VERSION 5.8 ;
BUSBITCHARS "[]" ;
DIVIDERCHAR "/" ;
UNITS
    DATABASE MICRONS 1000 ;
END UNITS

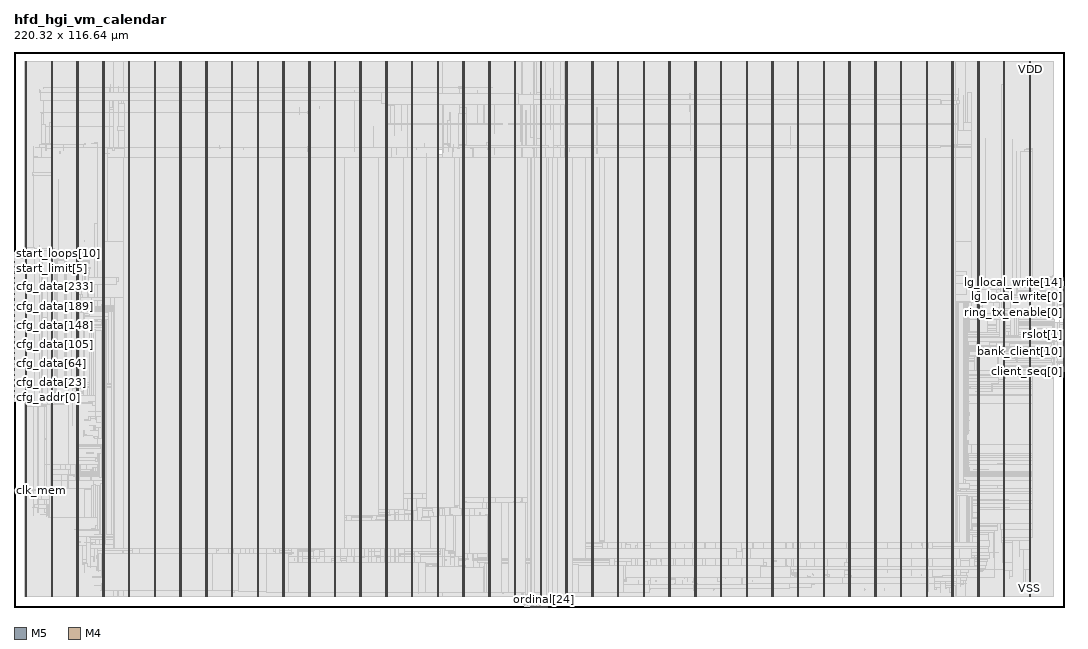
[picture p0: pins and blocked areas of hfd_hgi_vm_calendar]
MACRO hfd_hgi_vm_calendar
  FOREIGN hfd_hgi_vm_calendar 0 0 ;
  CLASS BLOCK ;
  SIZE 220.32 BY 116.64 ;
  PIN active
    DIRECTION OUTPUT ;
    USE SIGNAL ;
    PORT
      LAYER M5 ;
        RECT  108.576 0 108.6 0.084 ;
    END
  END active
  PIN bank_client[0]
    DIRECTION OUTPUT ;
    USE SIGNAL ;
    PORT
      LAYER M4 ;
        RECT  220.236 52.56 220.32 52.584 ;
    END
  END bank_client[0]
  PIN bank_client[10]
    DIRECTION OUTPUT ;
    USE SIGNAL ;
    PORT
      LAYER M4 ;
        RECT  220.236 53.52 220.32 53.544 ;
    END
  END bank_client[10]
  PIN bank_client[11]
    DIRECTION OUTPUT ;
    USE SIGNAL ;
    PORT
      LAYER M4 ;
        RECT  220.236 53.616 220.32 53.64 ;
    END
  END bank_client[11]
  PIN bank_client[12]
    DIRECTION OUTPUT ;
    USE SIGNAL ;
    PORT
      LAYER M4 ;
        RECT  220.236 53.712 220.32 53.736 ;
    END
  END bank_client[12]
  PIN bank_client[13]
    DIRECTION OUTPUT ;
    USE SIGNAL ;
    PORT
      LAYER M4 ;
        RECT  220.236 53.808 220.32 53.832 ;
    END
  END bank_client[13]
  PIN bank_client[14]
    DIRECTION OUTPUT ;
    USE SIGNAL ;
    PORT
      LAYER M4 ;
        RECT  220.236 53.904 220.32 53.928 ;
    END
  END bank_client[14]
  PIN bank_client[15]
    DIRECTION OUTPUT ;
    USE SIGNAL ;
    PORT
      LAYER M4 ;
        RECT  220.236 54 220.32 54.024 ;
    END
  END bank_client[15]
  PIN bank_client[16]
    DIRECTION OUTPUT ;
    USE SIGNAL ;
    PORT
      LAYER M4 ;
        RECT  220.236 54.096 220.32 54.12 ;
    END
  END bank_client[16]
  PIN bank_client[17]
    DIRECTION OUTPUT ;
    USE SIGNAL ;
    PORT
      LAYER M4 ;
        RECT  220.236 54.192 220.32 54.216 ;
    END
  END bank_client[17]
  PIN bank_client[18]
    DIRECTION OUTPUT ;
    USE SIGNAL ;
    PORT
      LAYER M4 ;
        RECT  220.236 54.288 220.32 54.312 ;
    END
  END bank_client[18]
  PIN bank_client[19]
    DIRECTION OUTPUT ;
    USE SIGNAL ;
    PORT
      LAYER M4 ;
        RECT  220.236 54.384 220.32 54.408 ;
    END
  END bank_client[19]
  PIN bank_client[1]
    DIRECTION OUTPUT ;
    USE SIGNAL ;
    PORT
      LAYER M4 ;
        RECT  220.236 52.656 220.32 52.68 ;
    END
  END bank_client[1]
  PIN bank_client[20]
    DIRECTION OUTPUT ;
    USE SIGNAL ;
    PORT
      LAYER M4 ;
        RECT  220.236 54.48 220.32 54.504 ;
    END
  END bank_client[20]
  PIN bank_client[21]
    DIRECTION OUTPUT ;
    USE SIGNAL ;
    PORT
      LAYER M4 ;
        RECT  220.236 54.576 220.32 54.6 ;
    END
  END bank_client[21]
  PIN bank_client[22]
    DIRECTION OUTPUT ;
    USE SIGNAL ;
    PORT
      LAYER M4 ;
        RECT  220.236 54.672 220.32 54.696 ;
    END
  END bank_client[22]
  PIN bank_client[23]
    DIRECTION OUTPUT ;
    USE SIGNAL ;
    PORT
      LAYER M4 ;
        RECT  220.236 54.768 220.32 54.792 ;
    END
  END bank_client[23]
  PIN bank_client[2]
    DIRECTION OUTPUT ;
    USE SIGNAL ;
    PORT
      LAYER M4 ;
        RECT  220.236 52.752 220.32 52.776 ;
    END
  END bank_client[2]
  PIN bank_client[3]
    DIRECTION OUTPUT ;
    USE SIGNAL ;
    PORT
      LAYER M4 ;
        RECT  220.236 52.848 220.32 52.872 ;
    END
  END bank_client[3]
  PIN bank_client[4]
    DIRECTION OUTPUT ;
    USE SIGNAL ;
    PORT
      LAYER M4 ;
        RECT  220.236 52.944 220.32 52.968 ;
    END
  END bank_client[4]
  PIN bank_client[5]
    DIRECTION OUTPUT ;
    USE SIGNAL ;
    PORT
      LAYER M4 ;
        RECT  220.236 53.04 220.32 53.064 ;
    END
  END bank_client[5]
  PIN bank_client[6]
    DIRECTION OUTPUT ;
    USE SIGNAL ;
    PORT
      LAYER M4 ;
        RECT  220.236 53.136 220.32 53.16 ;
    END
  END bank_client[6]
  PIN bank_client[7]
    DIRECTION OUTPUT ;
    USE SIGNAL ;
    PORT
      LAYER M4 ;
        RECT  220.236 53.232 220.32 53.256 ;
    END
  END bank_client[7]
  PIN bank_client[8]
    DIRECTION OUTPUT ;
    USE SIGNAL ;
    PORT
      LAYER M4 ;
        RECT  220.236 53.328 220.32 53.352 ;
    END
  END bank_client[8]
  PIN bank_client[9]
    DIRECTION OUTPUT ;
    USE SIGNAL ;
    PORT
      LAYER M4 ;
        RECT  220.236 53.424 220.32 53.448 ;
    END
  END bank_client[9]
  PIN bank_enable[0]
    DIRECTION OUTPUT ;
    USE SIGNAL ;
    PORT
      LAYER M4 ;
        RECT  220.236 51.792 220.32 51.816 ;
    END
  END bank_enable[0]
  PIN bank_enable[1]
    DIRECTION OUTPUT ;
    USE SIGNAL ;
    PORT
      LAYER M4 ;
        RECT  220.236 51.888 220.32 51.912 ;
    END
  END bank_enable[1]
  PIN bank_enable[2]
    DIRECTION OUTPUT ;
    USE SIGNAL ;
    PORT
      LAYER M4 ;
        RECT  220.236 51.984 220.32 52.008 ;
    END
  END bank_enable[2]
  PIN bank_enable[3]
    DIRECTION OUTPUT ;
    USE SIGNAL ;
    PORT
      LAYER M4 ;
        RECT  220.236 52.08 220.32 52.104 ;
    END
  END bank_enable[3]
  PIN bank_enable[4]
    DIRECTION OUTPUT ;
    USE SIGNAL ;
    PORT
      LAYER M4 ;
        RECT  220.236 52.176 220.32 52.2 ;
    END
  END bank_enable[4]
  PIN bank_enable[5]
    DIRECTION OUTPUT ;
    USE SIGNAL ;
    PORT
      LAYER M4 ;
        RECT  220.236 52.272 220.32 52.296 ;
    END
  END bank_enable[5]
  PIN bank_enable[6]
    DIRECTION OUTPUT ;
    USE SIGNAL ;
    PORT
      LAYER M4 ;
        RECT  220.236 52.368 220.32 52.392 ;
    END
  END bank_enable[6]
  PIN bank_enable[7]
    DIRECTION OUTPUT ;
    USE SIGNAL ;
    PORT
      LAYER M4 ;
        RECT  220.236 52.464 220.32 52.488 ;
    END
  END bank_enable[7]
  PIN calendar_v
    DIRECTION OUTPUT ;
    USE SIGNAL ;
    PORT
      LAYER M5 ;
        RECT  108.48 0 108.504 0.084 ;
    END
  END calendar_v
  PIN cfg_addr[0]
    DIRECTION INPUT ;
    USE SIGNAL ;
    PORT
      LAYER M4 ;
        RECT  0 43.968 0.084 43.992 ;
    END
  END cfg_addr[0]
  PIN cfg_addr[1]
    DIRECTION INPUT ;
    USE SIGNAL ;
    PORT
      LAYER M4 ;
        RECT  0 44.064 0.084 44.088 ;
    END
  END cfg_addr[1]
  PIN cfg_addr[2]
    DIRECTION INPUT ;
    USE SIGNAL ;
    PORT
      LAYER M4 ;
        RECT  0 44.16 0.084 44.184 ;
    END
  END cfg_addr[2]
  PIN cfg_addr[3]
    DIRECTION INPUT ;
    USE SIGNAL ;
    PORT
      LAYER M4 ;
        RECT  0 44.256 0.084 44.28 ;
    END
  END cfg_addr[3]
  PIN cfg_addr[4]
    DIRECTION INPUT ;
    USE SIGNAL ;
    PORT
      LAYER M4 ;
        RECT  0 44.352 0.084 44.376 ;
    END
  END cfg_addr[4]
  PIN cfg_addr[5]
    DIRECTION INPUT ;
    USE SIGNAL ;
    PORT
      LAYER M4 ;
        RECT  0 44.448 0.084 44.472 ;
    END
  END cfg_addr[5]
  PIN cfg_addr[6]
    DIRECTION INPUT ;
    USE SIGNAL ;
    PORT
      LAYER M4 ;
        RECT  0 44.544 0.084 44.568 ;
    END
  END cfg_addr[6]
  PIN cfg_addr[7]
    DIRECTION INPUT ;
    USE SIGNAL ;
    PORT
      LAYER M4 ;
        RECT  0 44.64 0.084 44.664 ;
    END
  END cfg_addr[7]
  PIN cfg_addr[8]
    DIRECTION INPUT ;
    USE SIGNAL ;
    PORT
      LAYER M4 ;
        RECT  0 44.736 0.084 44.76 ;
    END
  END cfg_addr[8]
  PIN cfg_addr[9]
    DIRECTION INPUT ;
    USE SIGNAL ;
    PORT
      LAYER M4 ;
        RECT  0 44.832 0.084 44.856 ;
    END
  END cfg_addr[9]
  PIN cfg_data[0]
    DIRECTION INPUT ;
    USE SIGNAL ;
    PORT
      LAYER M4 ;
        RECT  0 44.928 0.084 44.952 ;
    END
  END cfg_data[0]
  PIN cfg_data[100]
    DIRECTION INPUT ;
    USE SIGNAL ;
    PORT
      LAYER M4 ;
        RECT  0 54.528 0.084 54.552 ;
    END
  END cfg_data[100]
  PIN cfg_data[101]
    DIRECTION INPUT ;
    USE SIGNAL ;
    PORT
      LAYER M4 ;
        RECT  0 54.624 0.084 54.648 ;
    END
  END cfg_data[101]
  PIN cfg_data[102]
    DIRECTION INPUT ;
    USE SIGNAL ;
    PORT
      LAYER M4 ;
        RECT  0 54.72 0.084 54.744 ;
    END
  END cfg_data[102]
  PIN cfg_data[103]
    DIRECTION INPUT ;
    USE SIGNAL ;
    PORT
      LAYER M4 ;
        RECT  0 54.816 0.084 54.84 ;
    END
  END cfg_data[103]
  PIN cfg_data[104]
    DIRECTION INPUT ;
    USE SIGNAL ;
    PORT
      LAYER M4 ;
        RECT  0 54.912 0.084 54.936 ;
    END
  END cfg_data[104]
  PIN cfg_data[105]
    DIRECTION INPUT ;
    USE SIGNAL ;
    PORT
      LAYER M4 ;
        RECT  0 55.008 0.084 55.032 ;
    END
  END cfg_data[105]
  PIN cfg_data[106]
    DIRECTION INPUT ;
    USE SIGNAL ;
    PORT
      LAYER M4 ;
        RECT  0 55.104 0.084 55.128 ;
    END
  END cfg_data[106]
  PIN cfg_data[107]
    DIRECTION INPUT ;
    USE SIGNAL ;
    PORT
      LAYER M4 ;
        RECT  0 55.2 0.084 55.224 ;
    END
  END cfg_data[107]
  PIN cfg_data[108]
    DIRECTION INPUT ;
    USE SIGNAL ;
    PORT
      LAYER M4 ;
        RECT  0 55.296 0.084 55.32 ;
    END
  END cfg_data[108]
  PIN cfg_data[109]
    DIRECTION INPUT ;
    USE SIGNAL ;
    PORT
      LAYER M4 ;
        RECT  0 55.392 0.084 55.416 ;
    END
  END cfg_data[109]
  PIN cfg_data[10]
    DIRECTION INPUT ;
    USE SIGNAL ;
    PORT
      LAYER M4 ;
        RECT  0 45.888 0.084 45.912 ;
    END
  END cfg_data[10]
  PIN cfg_data[110]
    DIRECTION INPUT ;
    USE SIGNAL ;
    PORT
      LAYER M4 ;
        RECT  0 55.488 0.084 55.512 ;
    END
  END cfg_data[110]
  PIN cfg_data[111]
    DIRECTION INPUT ;
    USE SIGNAL ;
    PORT
      LAYER M4 ;
        RECT  0 55.584 0.084 55.608 ;
    END
  END cfg_data[111]
  PIN cfg_data[112]
    DIRECTION INPUT ;
    USE SIGNAL ;
    PORT
      LAYER M4 ;
        RECT  0 55.68 0.084 55.704 ;
    END
  END cfg_data[112]
  PIN cfg_data[113]
    DIRECTION INPUT ;
    USE SIGNAL ;
    PORT
      LAYER M4 ;
        RECT  0 55.776 0.084 55.8 ;
    END
  END cfg_data[113]
  PIN cfg_data[114]
    DIRECTION INPUT ;
    USE SIGNAL ;
    PORT
      LAYER M4 ;
        RECT  0 55.872 0.084 55.896 ;
    END
  END cfg_data[114]
  PIN cfg_data[115]
    DIRECTION INPUT ;
    USE SIGNAL ;
    PORT
      LAYER M4 ;
        RECT  0 55.968 0.084 55.992 ;
    END
  END cfg_data[115]
  PIN cfg_data[116]
    DIRECTION INPUT ;
    USE SIGNAL ;
    PORT
      LAYER M4 ;
        RECT  0 56.064 0.084 56.088 ;
    END
  END cfg_data[116]
  PIN cfg_data[117]
    DIRECTION INPUT ;
    USE SIGNAL ;
    PORT
      LAYER M4 ;
        RECT  0 56.16 0.084 56.184 ;
    END
  END cfg_data[117]
  PIN cfg_data[118]
    DIRECTION INPUT ;
    USE SIGNAL ;
    PORT
      LAYER M4 ;
        RECT  0 56.256 0.084 56.28 ;
    END
  END cfg_data[118]
  PIN cfg_data[119]
    DIRECTION INPUT ;
    USE SIGNAL ;
    PORT
      LAYER M4 ;
        RECT  0 56.352 0.084 56.376 ;
    END
  END cfg_data[119]
  PIN cfg_data[11]
    DIRECTION INPUT ;
    USE SIGNAL ;
    PORT
      LAYER M4 ;
        RECT  0 45.984 0.084 46.008 ;
    END
  END cfg_data[11]
  PIN cfg_data[120]
    DIRECTION INPUT ;
    USE SIGNAL ;
    PORT
      LAYER M4 ;
        RECT  0 56.448 0.084 56.472 ;
    END
  END cfg_data[120]
  PIN cfg_data[121]
    DIRECTION INPUT ;
    USE SIGNAL ;
    PORT
      LAYER M4 ;
        RECT  0 56.544 0.084 56.568 ;
    END
  END cfg_data[121]
  PIN cfg_data[122]
    DIRECTION INPUT ;
    USE SIGNAL ;
    PORT
      LAYER M4 ;
        RECT  0 56.64 0.084 56.664 ;
    END
  END cfg_data[122]
  PIN cfg_data[123]
    DIRECTION INPUT ;
    USE SIGNAL ;
    PORT
      LAYER M4 ;
        RECT  0 56.736 0.084 56.76 ;
    END
  END cfg_data[123]
  PIN cfg_data[124]
    DIRECTION INPUT ;
    USE SIGNAL ;
    PORT
      LAYER M4 ;
        RECT  0 56.832 0.084 56.856 ;
    END
  END cfg_data[124]
  PIN cfg_data[125]
    DIRECTION INPUT ;
    USE SIGNAL ;
    PORT
      LAYER M4 ;
        RECT  0 56.928 0.084 56.952 ;
    END
  END cfg_data[125]
  PIN cfg_data[126]
    DIRECTION INPUT ;
    USE SIGNAL ;
    PORT
      LAYER M4 ;
        RECT  0 57.024 0.084 57.048 ;
    END
  END cfg_data[126]
  PIN cfg_data[127]
    DIRECTION INPUT ;
    USE SIGNAL ;
    PORT
      LAYER M4 ;
        RECT  0 57.12 0.084 57.144 ;
    END
  END cfg_data[127]
  PIN cfg_data[128]
    DIRECTION INPUT ;
    USE SIGNAL ;
    PORT
      LAYER M4 ;
        RECT  0 57.216 0.084 57.24 ;
    END
  END cfg_data[128]
  PIN cfg_data[129]
    DIRECTION INPUT ;
    USE SIGNAL ;
    PORT
      LAYER M4 ;
        RECT  0 57.312 0.084 57.336 ;
    END
  END cfg_data[129]
  PIN cfg_data[12]
    DIRECTION INPUT ;
    USE SIGNAL ;
    PORT
      LAYER M4 ;
        RECT  0 46.08 0.084 46.104 ;
    END
  END cfg_data[12]
  PIN cfg_data[130]
    DIRECTION INPUT ;
    USE SIGNAL ;
    PORT
      LAYER M4 ;
        RECT  0 57.408 0.084 57.432 ;
    END
  END cfg_data[130]
  PIN cfg_data[131]
    DIRECTION INPUT ;
    USE SIGNAL ;
    PORT
      LAYER M4 ;
        RECT  0 57.504 0.084 57.528 ;
    END
  END cfg_data[131]
  PIN cfg_data[132]
    DIRECTION INPUT ;
    USE SIGNAL ;
    PORT
      LAYER M4 ;
        RECT  0 57.6 0.084 57.624 ;
    END
  END cfg_data[132]
  PIN cfg_data[133]
    DIRECTION INPUT ;
    USE SIGNAL ;
    PORT
      LAYER M4 ;
        RECT  0 57.696 0.084 57.72 ;
    END
  END cfg_data[133]
  PIN cfg_data[134]
    DIRECTION INPUT ;
    USE SIGNAL ;
    PORT
      LAYER M4 ;
        RECT  0 57.792 0.084 57.816 ;
    END
  END cfg_data[134]
  PIN cfg_data[135]
    DIRECTION INPUT ;
    USE SIGNAL ;
    PORT
      LAYER M4 ;
        RECT  0 57.888 0.084 57.912 ;
    END
  END cfg_data[135]
  PIN cfg_data[136]
    DIRECTION INPUT ;
    USE SIGNAL ;
    PORT
      LAYER M4 ;
        RECT  0 57.984 0.084 58.008 ;
    END
  END cfg_data[136]
  PIN cfg_data[137]
    DIRECTION INPUT ;
    USE SIGNAL ;
    PORT
      LAYER M4 ;
        RECT  0 58.08 0.084 58.104 ;
    END
  END cfg_data[137]
  PIN cfg_data[138]
    DIRECTION INPUT ;
    USE SIGNAL ;
    PORT
      LAYER M4 ;
        RECT  0 58.176 0.084 58.2 ;
    END
  END cfg_data[138]
  PIN cfg_data[139]
    DIRECTION INPUT ;
    USE SIGNAL ;
    PORT
      LAYER M4 ;
        RECT  0 58.272 0.084 58.296 ;
    END
  END cfg_data[139]
  PIN cfg_data[13]
    DIRECTION INPUT ;
    USE SIGNAL ;
    PORT
      LAYER M4 ;
        RECT  0 46.176 0.084 46.2 ;
    END
  END cfg_data[13]
  PIN cfg_data[140]
    DIRECTION INPUT ;
    USE SIGNAL ;
    PORT
      LAYER M4 ;
        RECT  0 58.368 0.084 58.392 ;
    END
  END cfg_data[140]
  PIN cfg_data[141]
    DIRECTION INPUT ;
    USE SIGNAL ;
    PORT
      LAYER M4 ;
        RECT  0 58.464 0.084 58.488 ;
    END
  END cfg_data[141]
  PIN cfg_data[142]
    DIRECTION INPUT ;
    USE SIGNAL ;
    PORT
      LAYER M4 ;
        RECT  0 58.56 0.084 58.584 ;
    END
  END cfg_data[142]
  PIN cfg_data[143]
    DIRECTION INPUT ;
    USE SIGNAL ;
    PORT
      LAYER M4 ;
        RECT  0 58.656 0.084 58.68 ;
    END
  END cfg_data[143]
  PIN cfg_data[144]
    DIRECTION INPUT ;
    USE SIGNAL ;
    PORT
      LAYER M4 ;
        RECT  0 58.752 0.084 58.776 ;
    END
  END cfg_data[144]
  PIN cfg_data[145]
    DIRECTION INPUT ;
    USE SIGNAL ;
    PORT
      LAYER M4 ;
        RECT  0 58.848 0.084 58.872 ;
    END
  END cfg_data[145]
  PIN cfg_data[146]
    DIRECTION INPUT ;
    USE SIGNAL ;
    PORT
      LAYER M4 ;
        RECT  0 58.944 0.084 58.968 ;
    END
  END cfg_data[146]
  PIN cfg_data[147]
    DIRECTION INPUT ;
    USE SIGNAL ;
    PORT
      LAYER M4 ;
        RECT  0 59.04 0.084 59.064 ;
    END
  END cfg_data[147]
  PIN cfg_data[148]
    DIRECTION INPUT ;
    USE SIGNAL ;
    PORT
      LAYER M4 ;
        RECT  0 59.136 0.084 59.16 ;
    END
  END cfg_data[148]
  PIN cfg_data[149]
    DIRECTION INPUT ;
    USE SIGNAL ;
    PORT
      LAYER M4 ;
        RECT  0 59.232 0.084 59.256 ;
    END
  END cfg_data[149]
  PIN cfg_data[14]
    DIRECTION INPUT ;
    USE SIGNAL ;
    PORT
      LAYER M4 ;
        RECT  0 46.272 0.084 46.296 ;
    END
  END cfg_data[14]
  PIN cfg_data[150]
    DIRECTION INPUT ;
    USE SIGNAL ;
    PORT
      LAYER M4 ;
        RECT  0 59.328 0.084 59.352 ;
    END
  END cfg_data[150]
  PIN cfg_data[151]
    DIRECTION INPUT ;
    USE SIGNAL ;
    PORT
      LAYER M4 ;
        RECT  0 59.424 0.084 59.448 ;
    END
  END cfg_data[151]
  PIN cfg_data[152]
    DIRECTION INPUT ;
    USE SIGNAL ;
    PORT
      LAYER M4 ;
        RECT  0 59.52 0.084 59.544 ;
    END
  END cfg_data[152]
  PIN cfg_data[153]
    DIRECTION INPUT ;
    USE SIGNAL ;
    PORT
      LAYER M4 ;
        RECT  0 59.616 0.084 59.64 ;
    END
  END cfg_data[153]
  PIN cfg_data[154]
    DIRECTION INPUT ;
    USE SIGNAL ;
    PORT
      LAYER M4 ;
        RECT  0 59.712 0.084 59.736 ;
    END
  END cfg_data[154]
  PIN cfg_data[155]
    DIRECTION INPUT ;
    USE SIGNAL ;
    PORT
      LAYER M4 ;
        RECT  0 59.808 0.084 59.832 ;
    END
  END cfg_data[155]
  PIN cfg_data[156]
    DIRECTION INPUT ;
    USE SIGNAL ;
    PORT
      LAYER M4 ;
        RECT  0 59.904 0.084 59.928 ;
    END
  END cfg_data[156]
  PIN cfg_data[157]
    DIRECTION INPUT ;
    USE SIGNAL ;
    PORT
      LAYER M4 ;
        RECT  0 60 0.084 60.024 ;
    END
  END cfg_data[157]
  PIN cfg_data[158]
    DIRECTION INPUT ;
    USE SIGNAL ;
    PORT
      LAYER M4 ;
        RECT  0 60.096 0.084 60.12 ;
    END
  END cfg_data[158]
  PIN cfg_data[159]
    DIRECTION INPUT ;
    USE SIGNAL ;
    PORT
      LAYER M4 ;
        RECT  0 60.192 0.084 60.216 ;
    END
  END cfg_data[159]
  PIN cfg_data[15]
    DIRECTION INPUT ;
    USE SIGNAL ;
    PORT
      LAYER M4 ;
        RECT  0 46.368 0.084 46.392 ;
    END
  END cfg_data[15]
  PIN cfg_data[160]
    DIRECTION INPUT ;
    USE SIGNAL ;
    PORT
      LAYER M4 ;
        RECT  0 60.288 0.084 60.312 ;
    END
  END cfg_data[160]
  PIN cfg_data[161]
    DIRECTION INPUT ;
    USE SIGNAL ;
    PORT
      LAYER M4 ;
        RECT  0 60.384 0.084 60.408 ;
    END
  END cfg_data[161]
  PIN cfg_data[162]
    DIRECTION INPUT ;
    USE SIGNAL ;
    PORT
      LAYER M4 ;
        RECT  0 60.48 0.084 60.504 ;
    END
  END cfg_data[162]
  PIN cfg_data[163]
    DIRECTION INPUT ;
    USE SIGNAL ;
    PORT
      LAYER M4 ;
        RECT  0 60.576 0.084 60.6 ;
    END
  END cfg_data[163]
  PIN cfg_data[164]
    DIRECTION INPUT ;
    USE SIGNAL ;
    PORT
      LAYER M4 ;
        RECT  0 60.672 0.084 60.696 ;
    END
  END cfg_data[164]
  PIN cfg_data[165]
    DIRECTION INPUT ;
    USE SIGNAL ;
    PORT
      LAYER M4 ;
        RECT  0 60.768 0.084 60.792 ;
    END
  END cfg_data[165]
  PIN cfg_data[166]
    DIRECTION INPUT ;
    USE SIGNAL ;
    PORT
      LAYER M4 ;
        RECT  0 60.864 0.084 60.888 ;
    END
  END cfg_data[166]
  PIN cfg_data[167]
    DIRECTION INPUT ;
    USE SIGNAL ;
    PORT
      LAYER M4 ;
        RECT  0 60.96 0.084 60.984 ;
    END
  END cfg_data[167]
  PIN cfg_data[168]
    DIRECTION INPUT ;
    USE SIGNAL ;
    PORT
      LAYER M4 ;
        RECT  0 61.056 0.084 61.08 ;
    END
  END cfg_data[168]
  PIN cfg_data[169]
    DIRECTION INPUT ;
    USE SIGNAL ;
    PORT
      LAYER M4 ;
        RECT  0 61.152 0.084 61.176 ;
    END
  END cfg_data[169]
  PIN cfg_data[16]
    DIRECTION INPUT ;
    USE SIGNAL ;
    PORT
      LAYER M4 ;
        RECT  0 46.464 0.084 46.488 ;
    END
  END cfg_data[16]
  PIN cfg_data[170]
    DIRECTION INPUT ;
    USE SIGNAL ;
    PORT
      LAYER M4 ;
        RECT  0 61.248 0.084 61.272 ;
    END
  END cfg_data[170]
  PIN cfg_data[171]
    DIRECTION INPUT ;
    USE SIGNAL ;
    PORT
      LAYER M4 ;
        RECT  0 61.344 0.084 61.368 ;
    END
  END cfg_data[171]
  PIN cfg_data[172]
    DIRECTION INPUT ;
    USE SIGNAL ;
    PORT
      LAYER M4 ;
        RECT  0 61.44 0.084 61.464 ;
    END
  END cfg_data[172]
  PIN cfg_data[173]
    DIRECTION INPUT ;
    USE SIGNAL ;
    PORT
      LAYER M4 ;
        RECT  0 61.536 0.084 61.56 ;
    END
  END cfg_data[173]
  PIN cfg_data[174]
    DIRECTION INPUT ;
    USE SIGNAL ;
    PORT
      LAYER M4 ;
        RECT  0 61.632 0.084 61.656 ;
    END
  END cfg_data[174]
  PIN cfg_data[175]
    DIRECTION INPUT ;
    USE SIGNAL ;
    PORT
      LAYER M4 ;
        RECT  0 61.728 0.084 61.752 ;
    END
  END cfg_data[175]
  PIN cfg_data[176]
    DIRECTION INPUT ;
    USE SIGNAL ;
    PORT
      LAYER M4 ;
        RECT  0 61.824 0.084 61.848 ;
    END
  END cfg_data[176]
  PIN cfg_data[177]
    DIRECTION INPUT ;
    USE SIGNAL ;
    PORT
      LAYER M4 ;
        RECT  0 61.92 0.084 61.944 ;
    END
  END cfg_data[177]
  PIN cfg_data[178]
    DIRECTION INPUT ;
    USE SIGNAL ;
    PORT
      LAYER M4 ;
        RECT  0 62.016 0.084 62.04 ;
    END
  END cfg_data[178]
  PIN cfg_data[179]
    DIRECTION INPUT ;
    USE SIGNAL ;
    PORT
      LAYER M4 ;
        RECT  0 62.112 0.084 62.136 ;
    END
  END cfg_data[179]
  PIN cfg_data[17]
    DIRECTION INPUT ;
    USE SIGNAL ;
    PORT
      LAYER M4 ;
        RECT  0 46.56 0.084 46.584 ;
    END
  END cfg_data[17]
  PIN cfg_data[180]
    DIRECTION INPUT ;
    USE SIGNAL ;
    PORT
      LAYER M4 ;
        RECT  0 62.208 0.084 62.232 ;
    END
  END cfg_data[180]
  PIN cfg_data[181]
    DIRECTION INPUT ;
    USE SIGNAL ;
    PORT
      LAYER M4 ;
        RECT  0 62.304 0.084 62.328 ;
    END
  END cfg_data[181]
  PIN cfg_data[182]
    DIRECTION INPUT ;
    USE SIGNAL ;
    PORT
      LAYER M4 ;
        RECT  0 62.4 0.084 62.424 ;
    END
  END cfg_data[182]
  PIN cfg_data[183]
    DIRECTION INPUT ;
    USE SIGNAL ;
    PORT
      LAYER M4 ;
        RECT  0 62.496 0.084 62.52 ;
    END
  END cfg_data[183]
  PIN cfg_data[184]
    DIRECTION INPUT ;
    USE SIGNAL ;
    PORT
      LAYER M4 ;
        RECT  0 62.592 0.084 62.616 ;
    END
  END cfg_data[184]
  PIN cfg_data[185]
    DIRECTION INPUT ;
    USE SIGNAL ;
    PORT
      LAYER M4 ;
        RECT  0 62.688 0.084 62.712 ;
    END
  END cfg_data[185]
  PIN cfg_data[186]
    DIRECTION INPUT ;
    USE SIGNAL ;
    PORT
      LAYER M4 ;
        RECT  0 62.784 0.084 62.808 ;
    END
  END cfg_data[186]
  PIN cfg_data[187]
    DIRECTION INPUT ;
    USE SIGNAL ;
    PORT
      LAYER M4 ;
        RECT  0 62.88 0.084 62.904 ;
    END
  END cfg_data[187]
  PIN cfg_data[188]
    DIRECTION INPUT ;
    USE SIGNAL ;
    PORT
      LAYER M4 ;
        RECT  0 62.976 0.084 63 ;
    END
  END cfg_data[188]
  PIN cfg_data[189]
    DIRECTION INPUT ;
    USE SIGNAL ;
    PORT
      LAYER M4 ;
        RECT  0 63.072 0.084 63.096 ;
    END
  END cfg_data[189]
  PIN cfg_data[18]
    DIRECTION INPUT ;
    USE SIGNAL ;
    PORT
      LAYER M4 ;
        RECT  0 46.656 0.084 46.68 ;
    END
  END cfg_data[18]
  PIN cfg_data[190]
    DIRECTION INPUT ;
    USE SIGNAL ;
    PORT
      LAYER M4 ;
        RECT  0 63.168 0.084 63.192 ;
    END
  END cfg_data[190]
  PIN cfg_data[191]
    DIRECTION INPUT ;
    USE SIGNAL ;
    PORT
      LAYER M4 ;
        RECT  0 63.264 0.084 63.288 ;
    END
  END cfg_data[191]
  PIN cfg_data[192]
    DIRECTION INPUT ;
    USE SIGNAL ;
    PORT
      LAYER M4 ;
        RECT  0 63.36 0.084 63.384 ;
    END
  END cfg_data[192]
  PIN cfg_data[193]
    DIRECTION INPUT ;
    USE SIGNAL ;
    PORT
      LAYER M4 ;
        RECT  0 63.456 0.084 63.48 ;
    END
  END cfg_data[193]
  PIN cfg_data[194]
    DIRECTION INPUT ;
    USE SIGNAL ;
    PORT
      LAYER M4 ;
        RECT  0 63.552 0.084 63.576 ;
    END
  END cfg_data[194]
  PIN cfg_data[195]
    DIRECTION INPUT ;
    USE SIGNAL ;
    PORT
      LAYER M4 ;
        RECT  0 63.648 0.084 63.672 ;
    END
  END cfg_data[195]
  PIN cfg_data[196]
    DIRECTION INPUT ;
    USE SIGNAL ;
    PORT
      LAYER M4 ;
        RECT  0 63.744 0.084 63.768 ;
    END
  END cfg_data[196]
  PIN cfg_data[197]
    DIRECTION INPUT ;
    USE SIGNAL ;
    PORT
      LAYER M4 ;
        RECT  0 63.84 0.084 63.864 ;
    END
  END cfg_data[197]
  PIN cfg_data[198]
    DIRECTION INPUT ;
    USE SIGNAL ;
    PORT
      LAYER M4 ;
        RECT  0 63.936 0.084 63.96 ;
    END
  END cfg_data[198]
  PIN cfg_data[199]
    DIRECTION INPUT ;
    USE SIGNAL ;
    PORT
      LAYER M4 ;
        RECT  0 64.032 0.084 64.056 ;
    END
  END cfg_data[199]
  PIN cfg_data[19]
    DIRECTION INPUT ;
    USE SIGNAL ;
    PORT
      LAYER M4 ;
        RECT  0 46.752 0.084 46.776 ;
    END
  END cfg_data[19]
  PIN cfg_data[1]
    DIRECTION INPUT ;
    USE SIGNAL ;
    PORT
      LAYER M4 ;
        RECT  0 45.024 0.084 45.048 ;
    END
  END cfg_data[1]
  PIN cfg_data[200]
    DIRECTION INPUT ;
    USE SIGNAL ;
    PORT
      LAYER M4 ;
        RECT  0 64.128 0.084 64.152 ;
    END
  END cfg_data[200]
  PIN cfg_data[201]
    DIRECTION INPUT ;
    USE SIGNAL ;
    PORT
      LAYER M4 ;
        RECT  0 64.224 0.084 64.248 ;
    END
  END cfg_data[201]
  PIN cfg_data[202]
    DIRECTION INPUT ;
    USE SIGNAL ;
    PORT
      LAYER M4 ;
        RECT  0 64.32 0.084 64.344 ;
    END
  END cfg_data[202]
  PIN cfg_data[203]
    DIRECTION INPUT ;
    USE SIGNAL ;
    PORT
      LAYER M4 ;
        RECT  0 64.416 0.084 64.44 ;
    END
  END cfg_data[203]
  PIN cfg_data[204]
    DIRECTION INPUT ;
    USE SIGNAL ;
    PORT
      LAYER M4 ;
        RECT  0 64.512 0.084 64.536 ;
    END
  END cfg_data[204]
  PIN cfg_data[205]
    DIRECTION INPUT ;
    USE SIGNAL ;
    PORT
      LAYER M4 ;
        RECT  0 64.608 0.084 64.632 ;
    END
  END cfg_data[205]
  PIN cfg_data[206]
    DIRECTION INPUT ;
    USE SIGNAL ;
    PORT
      LAYER M4 ;
        RECT  0 64.704 0.084 64.728 ;
    END
  END cfg_data[206]
  PIN cfg_data[207]
    DIRECTION INPUT ;
    USE SIGNAL ;
    PORT
      LAYER M4 ;
        RECT  0 64.8 0.084 64.824 ;
    END
  END cfg_data[207]
  PIN cfg_data[208]
    DIRECTION INPUT ;
    USE SIGNAL ;
    PORT
      LAYER M4 ;
        RECT  0 64.896 0.084 64.92 ;
    END
  END cfg_data[208]
  PIN cfg_data[209]
    DIRECTION INPUT ;
    USE SIGNAL ;
    PORT
      LAYER M4 ;
        RECT  0 64.992 0.084 65.016 ;
    END
  END cfg_data[209]
  PIN cfg_data[20]
    DIRECTION INPUT ;
    USE SIGNAL ;
    PORT
      LAYER M4 ;
        RECT  0 46.848 0.084 46.872 ;
    END
  END cfg_data[20]
  PIN cfg_data[210]
    DIRECTION INPUT ;
    USE SIGNAL ;
    PORT
      LAYER M4 ;
        RECT  0 65.088 0.084 65.112 ;
    END
  END cfg_data[210]
  PIN cfg_data[211]
    DIRECTION INPUT ;
    USE SIGNAL ;
    PORT
      LAYER M4 ;
        RECT  0 65.184 0.084 65.208 ;
    END
  END cfg_data[211]
  PIN cfg_data[212]
    DIRECTION INPUT ;
    USE SIGNAL ;
    PORT
      LAYER M4 ;
        RECT  0 65.28 0.084 65.304 ;
    END
  END cfg_data[212]
  PIN cfg_data[213]
    DIRECTION INPUT ;
    USE SIGNAL ;
    PORT
      LAYER M4 ;
        RECT  0 65.376 0.084 65.4 ;
    END
  END cfg_data[213]
  PIN cfg_data[214]
    DIRECTION INPUT ;
    USE SIGNAL ;
    PORT
      LAYER M4 ;
        RECT  0 65.472 0.084 65.496 ;
    END
  END cfg_data[214]
  PIN cfg_data[215]
    DIRECTION INPUT ;
    USE SIGNAL ;
    PORT
      LAYER M4 ;
        RECT  0 65.568 0.084 65.592 ;
    END
  END cfg_data[215]
  PIN cfg_data[216]
    DIRECTION INPUT ;
    USE SIGNAL ;
    PORT
      LAYER M4 ;
        RECT  0 65.664 0.084 65.688 ;
    END
  END cfg_data[216]
  PIN cfg_data[217]
    DIRECTION INPUT ;
    USE SIGNAL ;
    PORT
      LAYER M4 ;
        RECT  0 65.76 0.084 65.784 ;
    END
  END cfg_data[217]
  PIN cfg_data[218]
    DIRECTION INPUT ;
    USE SIGNAL ;
    PORT
      LAYER M4 ;
        RECT  0 65.856 0.084 65.88 ;
    END
  END cfg_data[218]
  PIN cfg_data[219]
    DIRECTION INPUT ;
    USE SIGNAL ;
    PORT
      LAYER M4 ;
        RECT  0 65.952 0.084 65.976 ;
    END
  END cfg_data[219]
  PIN cfg_data[21]
    DIRECTION INPUT ;
    USE SIGNAL ;
    PORT
      LAYER M4 ;
        RECT  0 46.944 0.084 46.968 ;
    END
  END cfg_data[21]
  PIN cfg_data[220]
    DIRECTION INPUT ;
    USE SIGNAL ;
    PORT
      LAYER M4 ;
        RECT  0 66.048 0.084 66.072 ;
    END
  END cfg_data[220]
  PIN cfg_data[221]
    DIRECTION INPUT ;
    USE SIGNAL ;
    PORT
      LAYER M4 ;
        RECT  0 66.144 0.084 66.168 ;
    END
  END cfg_data[221]
  PIN cfg_data[222]
    DIRECTION INPUT ;
    USE SIGNAL ;
    PORT
      LAYER M4 ;
        RECT  0 66.24 0.084 66.264 ;
    END
  END cfg_data[222]
  PIN cfg_data[223]
    DIRECTION INPUT ;
    USE SIGNAL ;
    PORT
      LAYER M4 ;
        RECT  0 66.336 0.084 66.36 ;
    END
  END cfg_data[223]
  PIN cfg_data[224]
    DIRECTION INPUT ;
    USE SIGNAL ;
    PORT
      LAYER M4 ;
        RECT  0 66.432 0.084 66.456 ;
    END
  END cfg_data[224]
  PIN cfg_data[225]
    DIRECTION INPUT ;
    USE SIGNAL ;
    PORT
      LAYER M4 ;
        RECT  0 66.528 0.084 66.552 ;
    END
  END cfg_data[225]
  PIN cfg_data[226]
    DIRECTION INPUT ;
    USE SIGNAL ;
    PORT
      LAYER M4 ;
        RECT  0 66.624 0.084 66.648 ;
    END
  END cfg_data[226]
  PIN cfg_data[227]
    DIRECTION INPUT ;
    USE SIGNAL ;
    PORT
      LAYER M4 ;
        RECT  0 66.72 0.084 66.744 ;
    END
  END cfg_data[227]
  PIN cfg_data[228]
    DIRECTION INPUT ;
    USE SIGNAL ;
    PORT
      LAYER M4 ;
        RECT  0 66.816 0.084 66.84 ;
    END
  END cfg_data[228]
  PIN cfg_data[229]
    DIRECTION INPUT ;
    USE SIGNAL ;
    PORT
      LAYER M4 ;
        RECT  0 66.912 0.084 66.936 ;
    END
  END cfg_data[229]
  PIN cfg_data[22]
    DIRECTION INPUT ;
    USE SIGNAL ;
    PORT
      LAYER M4 ;
        RECT  0 47.04 0.084 47.064 ;
    END
  END cfg_data[22]
  PIN cfg_data[230]
    DIRECTION INPUT ;
    USE SIGNAL ;
    PORT
      LAYER M4 ;
        RECT  0 67.008 0.084 67.032 ;
    END
  END cfg_data[230]
  PIN cfg_data[231]
    DIRECTION INPUT ;
    USE SIGNAL ;
    PORT
      LAYER M4 ;
        RECT  0 67.104 0.084 67.128 ;
    END
  END cfg_data[231]
  PIN cfg_data[232]
    DIRECTION INPUT ;
    USE SIGNAL ;
    PORT
      LAYER M4 ;
        RECT  0 67.2 0.084 67.224 ;
    END
  END cfg_data[232]
  PIN cfg_data[233]
    DIRECTION INPUT ;
    USE SIGNAL ;
    PORT
      LAYER M4 ;
        RECT  0 67.296 0.084 67.32 ;
    END
  END cfg_data[233]
  PIN cfg_data[234]
    DIRECTION INPUT ;
    USE SIGNAL ;
    PORT
      LAYER M4 ;
        RECT  0 67.392 0.084 67.416 ;
    END
  END cfg_data[234]
  PIN cfg_data[235]
    DIRECTION INPUT ;
    USE SIGNAL ;
    PORT
      LAYER M4 ;
        RECT  0 67.488 0.084 67.512 ;
    END
  END cfg_data[235]
  PIN cfg_data[236]
    DIRECTION INPUT ;
    USE SIGNAL ;
    PORT
      LAYER M4 ;
        RECT  0 67.584 0.084 67.608 ;
    END
  END cfg_data[236]
  PIN cfg_data[237]
    DIRECTION INPUT ;
    USE SIGNAL ;
    PORT
      LAYER M4 ;
        RECT  0 67.68 0.084 67.704 ;
    END
  END cfg_data[237]
  PIN cfg_data[238]
    DIRECTION INPUT ;
    USE SIGNAL ;
    PORT
      LAYER M4 ;
        RECT  0 67.776 0.084 67.8 ;
    END
  END cfg_data[238]
  PIN cfg_data[239]
    DIRECTION INPUT ;
    USE SIGNAL ;
    PORT
      LAYER M4 ;
        RECT  0 67.872 0.084 67.896 ;
    END
  END cfg_data[239]
  PIN cfg_data[23]
    DIRECTION INPUT ;
    USE SIGNAL ;
    PORT
      LAYER M4 ;
        RECT  0 47.136 0.084 47.16 ;
    END
  END cfg_data[23]
  PIN cfg_data[240]
    DIRECTION INPUT ;
    USE SIGNAL ;
    PORT
      LAYER M4 ;
        RECT  0 67.968 0.084 67.992 ;
    END
  END cfg_data[240]
  PIN cfg_data[241]
    DIRECTION INPUT ;
    USE SIGNAL ;
    PORT
      LAYER M4 ;
        RECT  0 68.064 0.084 68.088 ;
    END
  END cfg_data[241]
  PIN cfg_data[242]
    DIRECTION INPUT ;
    USE SIGNAL ;
    PORT
      LAYER M4 ;
        RECT  0 68.16 0.084 68.184 ;
    END
  END cfg_data[242]
  PIN cfg_data[243]
    DIRECTION INPUT ;
    USE SIGNAL ;
    PORT
      LAYER M4 ;
        RECT  0 68.256 0.084 68.28 ;
    END
  END cfg_data[243]
  PIN cfg_data[244]
    DIRECTION INPUT ;
    USE SIGNAL ;
    PORT
      LAYER M4 ;
        RECT  0 68.352 0.084 68.376 ;
    END
  END cfg_data[244]
  PIN cfg_data[245]
    DIRECTION INPUT ;
    USE SIGNAL ;
    PORT
      LAYER M4 ;
        RECT  0 68.448 0.084 68.472 ;
    END
  END cfg_data[245]
  PIN cfg_data[246]
    DIRECTION INPUT ;
    USE SIGNAL ;
    PORT
      LAYER M4 ;
        RECT  0 68.544 0.084 68.568 ;
    END
  END cfg_data[246]
  PIN cfg_data[247]
    DIRECTION INPUT ;
    USE SIGNAL ;
    PORT
      LAYER M4 ;
        RECT  0 68.64 0.084 68.664 ;
    END
  END cfg_data[247]
  PIN cfg_data[248]
    DIRECTION INPUT ;
    USE SIGNAL ;
    PORT
      LAYER M4 ;
        RECT  0 68.736 0.084 68.76 ;
    END
  END cfg_data[248]
  PIN cfg_data[249]
    DIRECTION INPUT ;
    USE SIGNAL ;
    PORT
      LAYER M4 ;
        RECT  0 68.832 0.084 68.856 ;
    END
  END cfg_data[249]
  PIN cfg_data[24]
    DIRECTION INPUT ;
    USE SIGNAL ;
    PORT
      LAYER M4 ;
        RECT  0 47.232 0.084 47.256 ;
    END
  END cfg_data[24]
  PIN cfg_data[250]
    DIRECTION INPUT ;
    USE SIGNAL ;
    PORT
      LAYER M4 ;
        RECT  0 68.928 0.084 68.952 ;
    END
  END cfg_data[250]
  PIN cfg_data[251]
    DIRECTION INPUT ;
    USE SIGNAL ;
    PORT
      LAYER M4 ;
        RECT  0 69.024 0.084 69.048 ;
    END
  END cfg_data[251]
  PIN cfg_data[252]
    DIRECTION INPUT ;
    USE SIGNAL ;
    PORT
      LAYER M4 ;
        RECT  0 69.12 0.084 69.144 ;
    END
  END cfg_data[252]
  PIN cfg_data[253]
    DIRECTION INPUT ;
    USE SIGNAL ;
    PORT
      LAYER M4 ;
        RECT  0 69.216 0.084 69.24 ;
    END
  END cfg_data[253]
  PIN cfg_data[254]
    DIRECTION INPUT ;
    USE SIGNAL ;
    PORT
      LAYER M4 ;
        RECT  0 69.312 0.084 69.336 ;
    END
  END cfg_data[254]
  PIN cfg_data[255]
    DIRECTION INPUT ;
    USE SIGNAL ;
    PORT
      LAYER M4 ;
        RECT  0 69.408 0.084 69.432 ;
    END
  END cfg_data[255]
  PIN cfg_data[25]
    DIRECTION INPUT ;
    USE SIGNAL ;
    PORT
      LAYER M4 ;
        RECT  0 47.328 0.084 47.352 ;
    END
  END cfg_data[25]
  PIN cfg_data[26]
    DIRECTION INPUT ;
    USE SIGNAL ;
    PORT
      LAYER M4 ;
        RECT  0 47.424 0.084 47.448 ;
    END
  END cfg_data[26]
  PIN cfg_data[27]
    DIRECTION INPUT ;
    USE SIGNAL ;
    PORT
      LAYER M4 ;
        RECT  0 47.52 0.084 47.544 ;
    END
  END cfg_data[27]
  PIN cfg_data[28]
    DIRECTION INPUT ;
    USE SIGNAL ;
    PORT
      LAYER M4 ;
        RECT  0 47.616 0.084 47.64 ;
    END
  END cfg_data[28]
  PIN cfg_data[29]
    DIRECTION INPUT ;
    USE SIGNAL ;
    PORT
      LAYER M4 ;
        RECT  0 47.712 0.084 47.736 ;
    END
  END cfg_data[29]
  PIN cfg_data[2]
    DIRECTION INPUT ;
    USE SIGNAL ;
    PORT
      LAYER M4 ;
        RECT  0 45.12 0.084 45.144 ;
    END
  END cfg_data[2]
  PIN cfg_data[30]
    DIRECTION INPUT ;
    USE SIGNAL ;
    PORT
      LAYER M4 ;
        RECT  0 47.808 0.084 47.832 ;
    END
  END cfg_data[30]
  PIN cfg_data[31]
    DIRECTION INPUT ;
    USE SIGNAL ;
    PORT
      LAYER M4 ;
        RECT  0 47.904 0.084 47.928 ;
    END
  END cfg_data[31]
  PIN cfg_data[32]
    DIRECTION INPUT ;
    USE SIGNAL ;
    PORT
      LAYER M4 ;
        RECT  0 48 0.084 48.024 ;
    END
  END cfg_data[32]
  PIN cfg_data[33]
    DIRECTION INPUT ;
    USE SIGNAL ;
    PORT
      LAYER M4 ;
        RECT  0 48.096 0.084 48.12 ;
    END
  END cfg_data[33]
  PIN cfg_data[34]
    DIRECTION INPUT ;
    USE SIGNAL ;
    PORT
      LAYER M4 ;
        RECT  0 48.192 0.084 48.216 ;
    END
  END cfg_data[34]
  PIN cfg_data[35]
    DIRECTION INPUT ;
    USE SIGNAL ;
    PORT
      LAYER M4 ;
        RECT  0 48.288 0.084 48.312 ;
    END
  END cfg_data[35]
  PIN cfg_data[36]
    DIRECTION INPUT ;
    USE SIGNAL ;
    PORT
      LAYER M4 ;
        RECT  0 48.384 0.084 48.408 ;
    END
  END cfg_data[36]
  PIN cfg_data[37]
    DIRECTION INPUT ;
    USE SIGNAL ;
    PORT
      LAYER M4 ;
        RECT  0 48.48 0.084 48.504 ;
    END
  END cfg_data[37]
  PIN cfg_data[38]
    DIRECTION INPUT ;
    USE SIGNAL ;
    PORT
      LAYER M4 ;
        RECT  0 48.576 0.084 48.6 ;
    END
  END cfg_data[38]
  PIN cfg_data[39]
    DIRECTION INPUT ;
    USE SIGNAL ;
    PORT
      LAYER M4 ;
        RECT  0 48.672 0.084 48.696 ;
    END
  END cfg_data[39]
  PIN cfg_data[3]
    DIRECTION INPUT ;
    USE SIGNAL ;
    PORT
      LAYER M4 ;
        RECT  0 45.216 0.084 45.24 ;
    END
  END cfg_data[3]
  PIN cfg_data[40]
    DIRECTION INPUT ;
    USE SIGNAL ;
    PORT
      LAYER M4 ;
        RECT  0 48.768 0.084 48.792 ;
    END
  END cfg_data[40]
  PIN cfg_data[41]
    DIRECTION INPUT ;
    USE SIGNAL ;
    PORT
      LAYER M4 ;
        RECT  0 48.864 0.084 48.888 ;
    END
  END cfg_data[41]
  PIN cfg_data[42]
    DIRECTION INPUT ;
    USE SIGNAL ;
    PORT
      LAYER M4 ;
        RECT  0 48.96 0.084 48.984 ;
    END
  END cfg_data[42]
  PIN cfg_data[43]
    DIRECTION INPUT ;
    USE SIGNAL ;
    PORT
      LAYER M4 ;
        RECT  0 49.056 0.084 49.08 ;
    END
  END cfg_data[43]
  PIN cfg_data[44]
    DIRECTION INPUT ;
    USE SIGNAL ;
    PORT
      LAYER M4 ;
        RECT  0 49.152 0.084 49.176 ;
    END
  END cfg_data[44]
  PIN cfg_data[45]
    DIRECTION INPUT ;
    USE SIGNAL ;
    PORT
      LAYER M4 ;
        RECT  0 49.248 0.084 49.272 ;
    END
  END cfg_data[45]
  PIN cfg_data[46]
    DIRECTION INPUT ;
    USE SIGNAL ;
    PORT
      LAYER M4 ;
        RECT  0 49.344 0.084 49.368 ;
    END
  END cfg_data[46]
  PIN cfg_data[47]
    DIRECTION INPUT ;
    USE SIGNAL ;
    PORT
      LAYER M4 ;
        RECT  0 49.44 0.084 49.464 ;
    END
  END cfg_data[47]
  PIN cfg_data[48]
    DIRECTION INPUT ;
    USE SIGNAL ;
    PORT
      LAYER M4 ;
        RECT  0 49.536 0.084 49.56 ;
    END
  END cfg_data[48]
  PIN cfg_data[49]
    DIRECTION INPUT ;
    USE SIGNAL ;
    PORT
      LAYER M4 ;
        RECT  0 49.632 0.084 49.656 ;
    END
  END cfg_data[49]
  PIN cfg_data[4]
    DIRECTION INPUT ;
    USE SIGNAL ;
    PORT
      LAYER M4 ;
        RECT  0 45.312 0.084 45.336 ;
    END
  END cfg_data[4]
  PIN cfg_data[50]
    DIRECTION INPUT ;
    USE SIGNAL ;
    PORT
      LAYER M4 ;
        RECT  0 49.728 0.084 49.752 ;
    END
  END cfg_data[50]
  PIN cfg_data[51]
    DIRECTION INPUT ;
    USE SIGNAL ;
    PORT
      LAYER M4 ;
        RECT  0 49.824 0.084 49.848 ;
    END
  END cfg_data[51]
  PIN cfg_data[52]
    DIRECTION INPUT ;
    USE SIGNAL ;
    PORT
      LAYER M4 ;
        RECT  0 49.92 0.084 49.944 ;
    END
  END cfg_data[52]
  PIN cfg_data[53]
    DIRECTION INPUT ;
    USE SIGNAL ;
    PORT
      LAYER M4 ;
        RECT  0 50.016 0.084 50.04 ;
    END
  END cfg_data[53]
  PIN cfg_data[54]
    DIRECTION INPUT ;
    USE SIGNAL ;
    PORT
      LAYER M4 ;
        RECT  0 50.112 0.084 50.136 ;
    END
  END cfg_data[54]
  PIN cfg_data[55]
    DIRECTION INPUT ;
    USE SIGNAL ;
    PORT
      LAYER M4 ;
        RECT  0 50.208 0.084 50.232 ;
    END
  END cfg_data[55]
  PIN cfg_data[56]
    DIRECTION INPUT ;
    USE SIGNAL ;
    PORT
      LAYER M4 ;
        RECT  0 50.304 0.084 50.328 ;
    END
  END cfg_data[56]
  PIN cfg_data[57]
    DIRECTION INPUT ;
    USE SIGNAL ;
    PORT
      LAYER M4 ;
        RECT  0 50.4 0.084 50.424 ;
    END
  END cfg_data[57]
  PIN cfg_data[58]
    DIRECTION INPUT ;
    USE SIGNAL ;
    PORT
      LAYER M4 ;
        RECT  0 50.496 0.084 50.52 ;
    END
  END cfg_data[58]
  PIN cfg_data[59]
    DIRECTION INPUT ;
    USE SIGNAL ;
    PORT
      LAYER M4 ;
        RECT  0 50.592 0.084 50.616 ;
    END
  END cfg_data[59]
  PIN cfg_data[5]
    DIRECTION INPUT ;
    USE SIGNAL ;
    PORT
      LAYER M4 ;
        RECT  0 45.408 0.084 45.432 ;
    END
  END cfg_data[5]
  PIN cfg_data[60]
    DIRECTION INPUT ;
    USE SIGNAL ;
    PORT
      LAYER M4 ;
        RECT  0 50.688 0.084 50.712 ;
    END
  END cfg_data[60]
  PIN cfg_data[61]
    DIRECTION INPUT ;
    USE SIGNAL ;
    PORT
      LAYER M4 ;
        RECT  0 50.784 0.084 50.808 ;
    END
  END cfg_data[61]
  PIN cfg_data[62]
    DIRECTION INPUT ;
    USE SIGNAL ;
    PORT
      LAYER M4 ;
        RECT  0 50.88 0.084 50.904 ;
    END
  END cfg_data[62]
  PIN cfg_data[63]
    DIRECTION INPUT ;
    USE SIGNAL ;
    PORT
      LAYER M4 ;
        RECT  0 50.976 0.084 51 ;
    END
  END cfg_data[63]
  PIN cfg_data[64]
    DIRECTION INPUT ;
    USE SIGNAL ;
    PORT
      LAYER M4 ;
        RECT  0 51.072 0.084 51.096 ;
    END
  END cfg_data[64]
  PIN cfg_data[65]
    DIRECTION INPUT ;
    USE SIGNAL ;
    PORT
      LAYER M4 ;
        RECT  0 51.168 0.084 51.192 ;
    END
  END cfg_data[65]
  PIN cfg_data[66]
    DIRECTION INPUT ;
    USE SIGNAL ;
    PORT
      LAYER M4 ;
        RECT  0 51.264 0.084 51.288 ;
    END
  END cfg_data[66]
  PIN cfg_data[67]
    DIRECTION INPUT ;
    USE SIGNAL ;
    PORT
      LAYER M4 ;
        RECT  0 51.36 0.084 51.384 ;
    END
  END cfg_data[67]
  PIN cfg_data[68]
    DIRECTION INPUT ;
    USE SIGNAL ;
    PORT
      LAYER M4 ;
        RECT  0 51.456 0.084 51.48 ;
    END
  END cfg_data[68]
  PIN cfg_data[69]
    DIRECTION INPUT ;
    USE SIGNAL ;
    PORT
      LAYER M4 ;
        RECT  0 51.552 0.084 51.576 ;
    END
  END cfg_data[69]
  PIN cfg_data[6]
    DIRECTION INPUT ;
    USE SIGNAL ;
    PORT
      LAYER M4 ;
        RECT  0 45.504 0.084 45.528 ;
    END
  END cfg_data[6]
  PIN cfg_data[70]
    DIRECTION INPUT ;
    USE SIGNAL ;
    PORT
      LAYER M4 ;
        RECT  0 51.648 0.084 51.672 ;
    END
  END cfg_data[70]
  PIN cfg_data[71]
    DIRECTION INPUT ;
    USE SIGNAL ;
    PORT
      LAYER M4 ;
        RECT  0 51.744 0.084 51.768 ;
    END
  END cfg_data[71]
  PIN cfg_data[72]
    DIRECTION INPUT ;
    USE SIGNAL ;
    PORT
      LAYER M4 ;
        RECT  0 51.84 0.084 51.864 ;
    END
  END cfg_data[72]
  PIN cfg_data[73]
    DIRECTION INPUT ;
    USE SIGNAL ;
    PORT
      LAYER M4 ;
        RECT  0 51.936 0.084 51.96 ;
    END
  END cfg_data[73]
  PIN cfg_data[74]
    DIRECTION INPUT ;
    USE SIGNAL ;
    PORT
      LAYER M4 ;
        RECT  0 52.032 0.084 52.056 ;
    END
  END cfg_data[74]
  PIN cfg_data[75]
    DIRECTION INPUT ;
    USE SIGNAL ;
    PORT
      LAYER M4 ;
        RECT  0 52.128 0.084 52.152 ;
    END
  END cfg_data[75]
  PIN cfg_data[76]
    DIRECTION INPUT ;
    USE SIGNAL ;
    PORT
      LAYER M4 ;
        RECT  0 52.224 0.084 52.248 ;
    END
  END cfg_data[76]
  PIN cfg_data[77]
    DIRECTION INPUT ;
    USE SIGNAL ;
    PORT
      LAYER M4 ;
        RECT  0 52.32 0.084 52.344 ;
    END
  END cfg_data[77]
  PIN cfg_data[78]
    DIRECTION INPUT ;
    USE SIGNAL ;
    PORT
      LAYER M4 ;
        RECT  0 52.416 0.084 52.44 ;
    END
  END cfg_data[78]
  PIN cfg_data[79]
    DIRECTION INPUT ;
    USE SIGNAL ;
    PORT
      LAYER M4 ;
        RECT  0 52.512 0.084 52.536 ;
    END
  END cfg_data[79]
  PIN cfg_data[7]
    DIRECTION INPUT ;
    USE SIGNAL ;
    PORT
      LAYER M4 ;
        RECT  0 45.6 0.084 45.624 ;
    END
  END cfg_data[7]
  PIN cfg_data[80]
    DIRECTION INPUT ;
    USE SIGNAL ;
    PORT
      LAYER M4 ;
        RECT  0 52.608 0.084 52.632 ;
    END
  END cfg_data[80]
  PIN cfg_data[81]
    DIRECTION INPUT ;
    USE SIGNAL ;
    PORT
      LAYER M4 ;
        RECT  0 52.704 0.084 52.728 ;
    END
  END cfg_data[81]
  PIN cfg_data[82]
    DIRECTION INPUT ;
    USE SIGNAL ;
    PORT
      LAYER M4 ;
        RECT  0 52.8 0.084 52.824 ;
    END
  END cfg_data[82]
  PIN cfg_data[83]
    DIRECTION INPUT ;
    USE SIGNAL ;
    PORT
      LAYER M4 ;
        RECT  0 52.896 0.084 52.92 ;
    END
  END cfg_data[83]
  PIN cfg_data[84]
    DIRECTION INPUT ;
    USE SIGNAL ;
    PORT
      LAYER M4 ;
        RECT  0 52.992 0.084 53.016 ;
    END
  END cfg_data[84]
  PIN cfg_data[85]
    DIRECTION INPUT ;
    USE SIGNAL ;
    PORT
      LAYER M4 ;
        RECT  0 53.088 0.084 53.112 ;
    END
  END cfg_data[85]
  PIN cfg_data[86]
    DIRECTION INPUT ;
    USE SIGNAL ;
    PORT
      LAYER M4 ;
        RECT  0 53.184 0.084 53.208 ;
    END
  END cfg_data[86]
  PIN cfg_data[87]
    DIRECTION INPUT ;
    USE SIGNAL ;
    PORT
      LAYER M4 ;
        RECT  0 53.28 0.084 53.304 ;
    END
  END cfg_data[87]
  PIN cfg_data[88]
    DIRECTION INPUT ;
    USE SIGNAL ;
    PORT
      LAYER M4 ;
        RECT  0 53.376 0.084 53.4 ;
    END
  END cfg_data[88]
  PIN cfg_data[89]
    DIRECTION INPUT ;
    USE SIGNAL ;
    PORT
      LAYER M4 ;
        RECT  0 53.472 0.084 53.496 ;
    END
  END cfg_data[89]
  PIN cfg_data[8]
    DIRECTION INPUT ;
    USE SIGNAL ;
    PORT
      LAYER M4 ;
        RECT  0 45.696 0.084 45.72 ;
    END
  END cfg_data[8]
  PIN cfg_data[90]
    DIRECTION INPUT ;
    USE SIGNAL ;
    PORT
      LAYER M4 ;
        RECT  0 53.568 0.084 53.592 ;
    END
  END cfg_data[90]
  PIN cfg_data[91]
    DIRECTION INPUT ;
    USE SIGNAL ;
    PORT
      LAYER M4 ;
        RECT  0 53.664 0.084 53.688 ;
    END
  END cfg_data[91]
  PIN cfg_data[92]
    DIRECTION INPUT ;
    USE SIGNAL ;
    PORT
      LAYER M4 ;
        RECT  0 53.76 0.084 53.784 ;
    END
  END cfg_data[92]
  PIN cfg_data[93]
    DIRECTION INPUT ;
    USE SIGNAL ;
    PORT
      LAYER M4 ;
        RECT  0 53.856 0.084 53.88 ;
    END
  END cfg_data[93]
  PIN cfg_data[94]
    DIRECTION INPUT ;
    USE SIGNAL ;
    PORT
      LAYER M4 ;
        RECT  0 53.952 0.084 53.976 ;
    END
  END cfg_data[94]
  PIN cfg_data[95]
    DIRECTION INPUT ;
    USE SIGNAL ;
    PORT
      LAYER M4 ;
        RECT  0 54.048 0.084 54.072 ;
    END
  END cfg_data[95]
  PIN cfg_data[96]
    DIRECTION INPUT ;
    USE SIGNAL ;
    PORT
      LAYER M4 ;
        RECT  0 54.144 0.084 54.168 ;
    END
  END cfg_data[96]
  PIN cfg_data[97]
    DIRECTION INPUT ;
    USE SIGNAL ;
    PORT
      LAYER M4 ;
        RECT  0 54.24 0.084 54.264 ;
    END
  END cfg_data[97]
  PIN cfg_data[98]
    DIRECTION INPUT ;
    USE SIGNAL ;
    PORT
      LAYER M4 ;
        RECT  0 54.336 0.084 54.36 ;
    END
  END cfg_data[98]
  PIN cfg_data[99]
    DIRECTION INPUT ;
    USE SIGNAL ;
    PORT
      LAYER M4 ;
        RECT  0 54.432 0.084 54.456 ;
    END
  END cfg_data[99]
  PIN cfg_data[9]
    DIRECTION INPUT ;
    USE SIGNAL ;
    PORT
      LAYER M4 ;
        RECT  0 45.792 0.084 45.816 ;
    END
  END cfg_data[9]
  PIN cfg_we
    DIRECTION INPUT ;
    USE SIGNAL ;
    PORT
      LAYER M4 ;
        RECT  0 43.872 0.084 43.896 ;
    END
  END cfg_we
  PIN client_seq[0]
    DIRECTION OUTPUT ;
    USE SIGNAL ;
    PORT
      LAYER M4 ;
        RECT  220.236 49.392 220.32 49.416 ;
    END
  END client_seq[0]
  PIN client_seq[1]
    DIRECTION OUTPUT ;
    USE SIGNAL ;
    PORT
      LAYER M4 ;
        RECT  220.236 49.488 220.32 49.512 ;
    END
  END client_seq[1]
  PIN client_seq[2]
    DIRECTION OUTPUT ;
    USE SIGNAL ;
    PORT
      LAYER M4 ;
        RECT  220.236 49.584 220.32 49.608 ;
    END
  END client_seq[2]
  PIN client_seq[3]
    DIRECTION OUTPUT ;
    USE SIGNAL ;
    PORT
      LAYER M4 ;
        RECT  220.236 49.68 220.32 49.704 ;
    END
  END client_seq[3]
  PIN client_seq[4]
    DIRECTION OUTPUT ;
    USE SIGNAL ;
    PORT
      LAYER M4 ;
        RECT  220.236 49.776 220.32 49.8 ;
    END
  END client_seq[4]
  PIN client_seq[5]
    DIRECTION OUTPUT ;
    USE SIGNAL ;
    PORT
      LAYER M4 ;
        RECT  220.236 49.872 220.32 49.896 ;
    END
  END client_seq[5]
  PIN client_seq[6]
    DIRECTION OUTPUT ;
    USE SIGNAL ;
    PORT
      LAYER M4 ;
        RECT  220.236 49.968 220.32 49.992 ;
    END
  END client_seq[6]
  PIN client_seq[7]
    DIRECTION OUTPUT ;
    USE SIGNAL ;
    PORT
      LAYER M4 ;
        RECT  220.236 50.064 220.32 50.088 ;
    END
  END client_seq[7]
  PIN client_seq[8]
    DIRECTION OUTPUT ;
    USE SIGNAL ;
    PORT
      LAYER M4 ;
        RECT  220.236 50.16 220.32 50.184 ;
    END
  END client_seq[8]
  PIN client_seq[9]
    DIRECTION OUTPUT ;
    USE SIGNAL ;
    PORT
      LAYER M4 ;
        RECT  220.236 50.256 220.32 50.28 ;
    END
  END client_seq[9]
  PIN clk
    DIRECTION INPUT ;
    USE SIGNAL ;
    PORT
      LAYER M5 ;
        RECT  108.384 0 108.408 0.084 ;
    END
  END clk
  PIN clk_cap
    DIRECTION INPUT ;
    USE SIGNAL ;
    PORT
      LAYER M4 ;
        RECT  0 43.68 0.084 43.704 ;
    END
  END clk_cap
  PIN clk_mem
    DIRECTION INPUT ;
    USE SIGNAL ;
    PORT
      LAYER M4 ;
        RECT  0 24.528 0.084 24.552 ;
    END
  END clk_mem
  PIN done
    DIRECTION OUTPUT ;
    USE SIGNAL ;
    PORT
      LAYER M5 ;
        RECT  108.672 0 108.696 0.084 ;
    END
  END done
  PIN fault
    DIRECTION OUTPUT ;
    USE SIGNAL ;
    PORT
      LAYER M5 ;
        RECT  108.768 0 108.792 0.084 ;
    END
  END fault
  PIN hub_ring_client[0]
    DIRECTION OUTPUT ;
    USE SIGNAL ;
    PORT
      LAYER M4 ;
        RECT  220.236 55.056 220.32 55.08 ;
    END
  END hub_ring_client[0]
  PIN hub_ring_client[1]
    DIRECTION OUTPUT ;
    USE SIGNAL ;
    PORT
      LAYER M4 ;
        RECT  220.236 55.152 220.32 55.176 ;
    END
  END hub_ring_client[1]
  PIN hub_ring_client[2]
    DIRECTION OUTPUT ;
    USE SIGNAL ;
    PORT
      LAYER M4 ;
        RECT  220.236 55.248 220.32 55.272 ;
    END
  END hub_ring_client[2]
  PIN hub_ring_client[3]
    DIRECTION OUTPUT ;
    USE SIGNAL ;
    PORT
      LAYER M4 ;
        RECT  220.236 55.344 220.32 55.368 ;
    END
  END hub_ring_client[3]
  PIN hub_ring_client[4]
    DIRECTION OUTPUT ;
    USE SIGNAL ;
    PORT
      LAYER M4 ;
        RECT  220.236 55.44 220.32 55.464 ;
    END
  END hub_ring_client[4]
  PIN hub_ring_client[5]
    DIRECTION OUTPUT ;
    USE SIGNAL ;
    PORT
      LAYER M4 ;
        RECT  220.236 55.536 220.32 55.56 ;
    END
  END hub_ring_client[5]
  PIN hub_ring_enable[0]
    DIRECTION OUTPUT ;
    USE SIGNAL ;
    PORT
      LAYER M4 ;
        RECT  220.236 54.864 220.32 54.888 ;
    END
  END hub_ring_enable[0]
  PIN hub_ring_enable[1]
    DIRECTION OUTPUT ;
    USE SIGNAL ;
    PORT
      LAYER M4 ;
        RECT  220.236 54.96 220.32 54.984 ;
    END
  END hub_ring_enable[1]
  PIN lg_local_read[0]
    DIRECTION OUTPUT ;
    USE SIGNAL ;
    PORT
      LAYER M4 ;
        RECT  220.236 62.736 220.32 62.76 ;
    END
  END lg_local_read[0]
  PIN lg_local_read[10]
    DIRECTION OUTPUT ;
    USE SIGNAL ;
    PORT
      LAYER M4 ;
        RECT  220.236 63.696 220.32 63.72 ;
    END
  END lg_local_read[10]
  PIN lg_local_read[11]
    DIRECTION OUTPUT ;
    USE SIGNAL ;
    PORT
      LAYER M4 ;
        RECT  220.236 63.792 220.32 63.816 ;
    END
  END lg_local_read[11]
  PIN lg_local_read[12]
    DIRECTION OUTPUT ;
    USE SIGNAL ;
    PORT
      LAYER M4 ;
        RECT  220.236 63.888 220.32 63.912 ;
    END
  END lg_local_read[12]
  PIN lg_local_read[13]
    DIRECTION OUTPUT ;
    USE SIGNAL ;
    PORT
      LAYER M4 ;
        RECT  220.236 63.984 220.32 64.008 ;
    END
  END lg_local_read[13]
  PIN lg_local_read[14]
    DIRECTION OUTPUT ;
    USE SIGNAL ;
    PORT
      LAYER M4 ;
        RECT  220.236 64.08 220.32 64.104 ;
    END
  END lg_local_read[14]
  PIN lg_local_read[15]
    DIRECTION OUTPUT ;
    USE SIGNAL ;
    PORT
      LAYER M4 ;
        RECT  220.236 64.176 220.32 64.2 ;
    END
  END lg_local_read[15]
  PIN lg_local_read[16]
    DIRECTION OUTPUT ;
    USE SIGNAL ;
    PORT
      LAYER M4 ;
        RECT  220.236 64.272 220.32 64.296 ;
    END
  END lg_local_read[16]
  PIN lg_local_read[17]
    DIRECTION OUTPUT ;
    USE SIGNAL ;
    PORT
      LAYER M4 ;
        RECT  220.236 64.368 220.32 64.392 ;
    END
  END lg_local_read[17]
  PIN lg_local_read[18]
    DIRECTION OUTPUT ;
    USE SIGNAL ;
    PORT
      LAYER M4 ;
        RECT  220.236 64.464 220.32 64.488 ;
    END
  END lg_local_read[18]
  PIN lg_local_read[19]
    DIRECTION OUTPUT ;
    USE SIGNAL ;
    PORT
      LAYER M4 ;
        RECT  220.236 64.56 220.32 64.584 ;
    END
  END lg_local_read[19]
  PIN lg_local_read[1]
    DIRECTION OUTPUT ;
    USE SIGNAL ;
    PORT
      LAYER M4 ;
        RECT  220.236 62.832 220.32 62.856 ;
    END
  END lg_local_read[1]
  PIN lg_local_read[20]
    DIRECTION OUTPUT ;
    USE SIGNAL ;
    PORT
      LAYER M4 ;
        RECT  220.236 64.656 220.32 64.68 ;
    END
  END lg_local_read[20]
  PIN lg_local_read[21]
    DIRECTION OUTPUT ;
    USE SIGNAL ;
    PORT
      LAYER M4 ;
        RECT  220.236 64.752 220.32 64.776 ;
    END
  END lg_local_read[21]
  PIN lg_local_read[22]
    DIRECTION OUTPUT ;
    USE SIGNAL ;
    PORT
      LAYER M4 ;
        RECT  220.236 64.848 220.32 64.872 ;
    END
  END lg_local_read[22]
  PIN lg_local_read[23]
    DIRECTION OUTPUT ;
    USE SIGNAL ;
    PORT
      LAYER M4 ;
        RECT  220.236 64.944 220.32 64.968 ;
    END
  END lg_local_read[23]
  PIN lg_local_read[2]
    DIRECTION OUTPUT ;
    USE SIGNAL ;
    PORT
      LAYER M4 ;
        RECT  220.236 62.928 220.32 62.952 ;
    END
  END lg_local_read[2]
  PIN lg_local_read[3]
    DIRECTION OUTPUT ;
    USE SIGNAL ;
    PORT
      LAYER M4 ;
        RECT  220.236 63.024 220.32 63.048 ;
    END
  END lg_local_read[3]
  PIN lg_local_read[4]
    DIRECTION OUTPUT ;
    USE SIGNAL ;
    PORT
      LAYER M4 ;
        RECT  220.236 63.12 220.32 63.144 ;
    END
  END lg_local_read[4]
  PIN lg_local_read[5]
    DIRECTION OUTPUT ;
    USE SIGNAL ;
    PORT
      LAYER M4 ;
        RECT  220.236 63.216 220.32 63.24 ;
    END
  END lg_local_read[5]
  PIN lg_local_read[6]
    DIRECTION OUTPUT ;
    USE SIGNAL ;
    PORT
      LAYER M4 ;
        RECT  220.236 63.312 220.32 63.336 ;
    END
  END lg_local_read[6]
  PIN lg_local_read[7]
    DIRECTION OUTPUT ;
    USE SIGNAL ;
    PORT
      LAYER M4 ;
        RECT  220.236 63.408 220.32 63.432 ;
    END
  END lg_local_read[7]
  PIN lg_local_read[8]
    DIRECTION OUTPUT ;
    USE SIGNAL ;
    PORT
      LAYER M4 ;
        RECT  220.236 63.504 220.32 63.528 ;
    END
  END lg_local_read[8]
  PIN lg_local_read[9]
    DIRECTION OUTPUT ;
    USE SIGNAL ;
    PORT
      LAYER M4 ;
        RECT  220.236 63.6 220.32 63.624 ;
    END
  END lg_local_read[9]
  PIN lg_local_write[0]
    DIRECTION OUTPUT ;
    USE SIGNAL ;
    PORT
      LAYER M4 ;
        RECT  220.236 65.04 220.32 65.064 ;
    END
  END lg_local_write[0]
  PIN lg_local_write[10]
    DIRECTION OUTPUT ;
    USE SIGNAL ;
    PORT
      LAYER M4 ;
        RECT  220.236 66 220.32 66.024 ;
    END
  END lg_local_write[10]
  PIN lg_local_write[11]
    DIRECTION OUTPUT ;
    USE SIGNAL ;
    PORT
      LAYER M4 ;
        RECT  220.236 66.096 220.32 66.12 ;
    END
  END lg_local_write[11]
  PIN lg_local_write[12]
    DIRECTION OUTPUT ;
    USE SIGNAL ;
    PORT
      LAYER M4 ;
        RECT  220.236 66.192 220.32 66.216 ;
    END
  END lg_local_write[12]
  PIN lg_local_write[13]
    DIRECTION OUTPUT ;
    USE SIGNAL ;
    PORT
      LAYER M4 ;
        RECT  220.236 66.288 220.32 66.312 ;
    END
  END lg_local_write[13]
  PIN lg_local_write[14]
    DIRECTION OUTPUT ;
    USE SIGNAL ;
    PORT
      LAYER M4 ;
        RECT  220.236 66.384 220.32 66.408 ;
    END
  END lg_local_write[14]
  PIN lg_local_write[15]
    DIRECTION OUTPUT ;
    USE SIGNAL ;
    PORT
      LAYER M4 ;
        RECT  220.236 66.48 220.32 66.504 ;
    END
  END lg_local_write[15]
  PIN lg_local_write[16]
    DIRECTION OUTPUT ;
    USE SIGNAL ;
    PORT
      LAYER M4 ;
        RECT  220.236 66.576 220.32 66.6 ;
    END
  END lg_local_write[16]
  PIN lg_local_write[17]
    DIRECTION OUTPUT ;
    USE SIGNAL ;
    PORT
      LAYER M4 ;
        RECT  220.236 66.672 220.32 66.696 ;
    END
  END lg_local_write[17]
  PIN lg_local_write[18]
    DIRECTION OUTPUT ;
    USE SIGNAL ;
    PORT
      LAYER M4 ;
        RECT  220.236 66.768 220.32 66.792 ;
    END
  END lg_local_write[18]
  PIN lg_local_write[19]
    DIRECTION OUTPUT ;
    USE SIGNAL ;
    PORT
      LAYER M4 ;
        RECT  220.236 66.864 220.32 66.888 ;
    END
  END lg_local_write[19]
  PIN lg_local_write[1]
    DIRECTION OUTPUT ;
    USE SIGNAL ;
    PORT
      LAYER M4 ;
        RECT  220.236 65.136 220.32 65.16 ;
    END
  END lg_local_write[1]
  PIN lg_local_write[20]
    DIRECTION OUTPUT ;
    USE SIGNAL ;
    PORT
      LAYER M4 ;
        RECT  220.236 66.96 220.32 66.984 ;
    END
  END lg_local_write[20]
  PIN lg_local_write[21]
    DIRECTION OUTPUT ;
    USE SIGNAL ;
    PORT
      LAYER M4 ;
        RECT  220.236 67.056 220.32 67.08 ;
    END
  END lg_local_write[21]
  PIN lg_local_write[22]
    DIRECTION OUTPUT ;
    USE SIGNAL ;
    PORT
      LAYER M4 ;
        RECT  220.236 67.152 220.32 67.176 ;
    END
  END lg_local_write[22]
  PIN lg_local_write[23]
    DIRECTION OUTPUT ;
    USE SIGNAL ;
    PORT
      LAYER M4 ;
        RECT  220.236 67.248 220.32 67.272 ;
    END
  END lg_local_write[23]
  PIN lg_local_write[2]
    DIRECTION OUTPUT ;
    USE SIGNAL ;
    PORT
      LAYER M4 ;
        RECT  220.236 65.232 220.32 65.256 ;
    END
  END lg_local_write[2]
  PIN lg_local_write[3]
    DIRECTION OUTPUT ;
    USE SIGNAL ;
    PORT
      LAYER M4 ;
        RECT  220.236 65.328 220.32 65.352 ;
    END
  END lg_local_write[3]
  PIN lg_local_write[4]
    DIRECTION OUTPUT ;
    USE SIGNAL ;
    PORT
      LAYER M4 ;
        RECT  220.236 65.424 220.32 65.448 ;
    END
  END lg_local_write[4]
  PIN lg_local_write[5]
    DIRECTION OUTPUT ;
    USE SIGNAL ;
    PORT
      LAYER M4 ;
        RECT  220.236 65.52 220.32 65.544 ;
    END
  END lg_local_write[5]
  PIN lg_local_write[6]
    DIRECTION OUTPUT ;
    USE SIGNAL ;
    PORT
      LAYER M4 ;
        RECT  220.236 65.616 220.32 65.64 ;
    END
  END lg_local_write[6]
  PIN lg_local_write[7]
    DIRECTION OUTPUT ;
    USE SIGNAL ;
    PORT
      LAYER M4 ;
        RECT  220.236 65.712 220.32 65.736 ;
    END
  END lg_local_write[7]
  PIN lg_local_write[8]
    DIRECTION OUTPUT ;
    USE SIGNAL ;
    PORT
      LAYER M4 ;
        RECT  220.236 65.808 220.32 65.832 ;
    END
  END lg_local_write[8]
  PIN lg_local_write[9]
    DIRECTION OUTPUT ;
    USE SIGNAL ;
    PORT
      LAYER M4 ;
        RECT  220.236 65.904 220.32 65.928 ;
    END
  END lg_local_write[9]
  PIN ordinal[0]
    DIRECTION OUTPUT ;
    USE SIGNAL ;
    PORT
      LAYER M5 ;
        RECT  108.864 0 108.888 0.084 ;
    END
  END ordinal[0]
  PIN ordinal[10]
    DIRECTION OUTPUT ;
    USE SIGNAL ;
    PORT
      LAYER M5 ;
        RECT  109.824 0 109.848 0.084 ;
    END
  END ordinal[10]
  PIN ordinal[11]
    DIRECTION OUTPUT ;
    USE SIGNAL ;
    PORT
      LAYER M5 ;
        RECT  109.92 0 109.944 0.084 ;
    END
  END ordinal[11]
  PIN ordinal[12]
    DIRECTION OUTPUT ;
    USE SIGNAL ;
    PORT
      LAYER M5 ;
        RECT  110.016 0 110.04 0.084 ;
    END
  END ordinal[12]
  PIN ordinal[13]
    DIRECTION OUTPUT ;
    USE SIGNAL ;
    PORT
      LAYER M5 ;
        RECT  110.112 0 110.136 0.084 ;
    END
  END ordinal[13]
  PIN ordinal[14]
    DIRECTION OUTPUT ;
    USE SIGNAL ;
    PORT
      LAYER M5 ;
        RECT  110.208 0 110.232 0.084 ;
    END
  END ordinal[14]
  PIN ordinal[15]
    DIRECTION OUTPUT ;
    USE SIGNAL ;
    PORT
      LAYER M5 ;
        RECT  110.304 0 110.328 0.084 ;
    END
  END ordinal[15]
  PIN ordinal[16]
    DIRECTION OUTPUT ;
    USE SIGNAL ;
    PORT
      LAYER M5 ;
        RECT  110.4 0 110.424 0.084 ;
    END
  END ordinal[16]
  PIN ordinal[17]
    DIRECTION OUTPUT ;
    USE SIGNAL ;
    PORT
      LAYER M5 ;
        RECT  110.496 0 110.52 0.084 ;
    END
  END ordinal[17]
  PIN ordinal[18]
    DIRECTION OUTPUT ;
    USE SIGNAL ;
    PORT
      LAYER M5 ;
        RECT  110.592 0 110.616 0.084 ;
    END
  END ordinal[18]
  PIN ordinal[19]
    DIRECTION OUTPUT ;
    USE SIGNAL ;
    PORT
      LAYER M5 ;
        RECT  110.688 0 110.712 0.084 ;
    END
  END ordinal[19]
  PIN ordinal[1]
    DIRECTION OUTPUT ;
    USE SIGNAL ;
    PORT
      LAYER M5 ;
        RECT  108.96 0 108.984 0.084 ;
    END
  END ordinal[1]
  PIN ordinal[20]
    DIRECTION OUTPUT ;
    USE SIGNAL ;
    PORT
      LAYER M5 ;
        RECT  110.784 0 110.808 0.084 ;
    END
  END ordinal[20]
  PIN ordinal[21]
    DIRECTION OUTPUT ;
    USE SIGNAL ;
    PORT
      LAYER M5 ;
        RECT  110.88 0 110.904 0.084 ;
    END
  END ordinal[21]
  PIN ordinal[22]
    DIRECTION OUTPUT ;
    USE SIGNAL ;
    PORT
      LAYER M5 ;
        RECT  110.976 0 111 0.084 ;
    END
  END ordinal[22]
  PIN ordinal[23]
    DIRECTION OUTPUT ;
    USE SIGNAL ;
    PORT
      LAYER M5 ;
        RECT  111.072 0 111.096 0.084 ;
    END
  END ordinal[23]
  PIN ordinal[24]
    DIRECTION OUTPUT ;
    USE SIGNAL ;
    PORT
      LAYER M5 ;
        RECT  111.168 0 111.192 0.084 ;
    END
  END ordinal[24]
  PIN ordinal[25]
    DIRECTION OUTPUT ;
    USE SIGNAL ;
    PORT
      LAYER M5 ;
        RECT  111.264 0 111.288 0.084 ;
    END
  END ordinal[25]
  PIN ordinal[26]
    DIRECTION OUTPUT ;
    USE SIGNAL ;
    PORT
      LAYER M5 ;
        RECT  111.36 0 111.384 0.084 ;
    END
  END ordinal[26]
  PIN ordinal[27]
    DIRECTION OUTPUT ;
    USE SIGNAL ;
    PORT
      LAYER M5 ;
        RECT  111.456 0 111.48 0.084 ;
    END
  END ordinal[27]
  PIN ordinal[28]
    DIRECTION OUTPUT ;
    USE SIGNAL ;
    PORT
      LAYER M5 ;
        RECT  111.552 0 111.576 0.084 ;
    END
  END ordinal[28]
  PIN ordinal[29]
    DIRECTION OUTPUT ;
    USE SIGNAL ;
    PORT
      LAYER M5 ;
        RECT  111.648 0 111.672 0.084 ;
    END
  END ordinal[29]
  PIN ordinal[2]
    DIRECTION OUTPUT ;
    USE SIGNAL ;
    PORT
      LAYER M5 ;
        RECT  109.056 0 109.08 0.084 ;
    END
  END ordinal[2]
  PIN ordinal[30]
    DIRECTION OUTPUT ;
    USE SIGNAL ;
    PORT
      LAYER M5 ;
        RECT  111.744 0 111.768 0.084 ;
    END
  END ordinal[30]
  PIN ordinal[31]
    DIRECTION OUTPUT ;
    USE SIGNAL ;
    PORT
      LAYER M5 ;
        RECT  111.84 0 111.864 0.084 ;
    END
  END ordinal[31]
  PIN ordinal[3]
    DIRECTION OUTPUT ;
    USE SIGNAL ;
    PORT
      LAYER M5 ;
        RECT  109.152 0 109.176 0.084 ;
    END
  END ordinal[3]
  PIN ordinal[4]
    DIRECTION OUTPUT ;
    USE SIGNAL ;
    PORT
      LAYER M5 ;
        RECT  109.248 0 109.272 0.084 ;
    END
  END ordinal[4]
  PIN ordinal[5]
    DIRECTION OUTPUT ;
    USE SIGNAL ;
    PORT
      LAYER M5 ;
        RECT  109.344 0 109.368 0.084 ;
    END
  END ordinal[5]
  PIN ordinal[6]
    DIRECTION OUTPUT ;
    USE SIGNAL ;
    PORT
      LAYER M5 ;
        RECT  109.44 0 109.464 0.084 ;
    END
  END ordinal[6]
  PIN ordinal[7]
    DIRECTION OUTPUT ;
    USE SIGNAL ;
    PORT
      LAYER M5 ;
        RECT  109.536 0 109.56 0.084 ;
    END
  END ordinal[7]
  PIN ordinal[8]
    DIRECTION OUTPUT ;
    USE SIGNAL ;
    PORT
      LAYER M5 ;
        RECT  109.632 0 109.656 0.084 ;
    END
  END ordinal[8]
  PIN ordinal[9]
    DIRECTION OUTPUT ;
    USE SIGNAL ;
    PORT
      LAYER M5 ;
        RECT  109.728 0 109.752 0.084 ;
    END
  END ordinal[9]
  PIN replay_enable
    DIRECTION OUTPUT ;
    USE SIGNAL ;
    PORT
      LAYER M4 ;
        RECT  220.236 62.544 220.32 62.568 ;
    END
  END replay_enable
  PIN replay_source
    DIRECTION OUTPUT ;
    USE SIGNAL ;
    PORT
      LAYER M4 ;
        RECT  220.236 62.64 220.32 62.664 ;
    END
  END replay_source
  PIN response_enable[0]
    DIRECTION OUTPUT ;
    USE SIGNAL ;
    PORT
      LAYER M4 ;
        RECT  220.236 50.352 220.32 50.376 ;
    END
  END response_enable[0]
  PIN response_enable[1]
    DIRECTION OUTPUT ;
    USE SIGNAL ;
    PORT
      LAYER M4 ;
        RECT  220.236 50.448 220.32 50.472 ;
    END
  END response_enable[1]
  PIN response_enable[2]
    DIRECTION OUTPUT ;
    USE SIGNAL ;
    PORT
      LAYER M4 ;
        RECT  220.236 50.544 220.32 50.568 ;
    END
  END response_enable[2]
  PIN response_enable[3]
    DIRECTION OUTPUT ;
    USE SIGNAL ;
    PORT
      LAYER M4 ;
        RECT  220.236 50.64 220.32 50.664 ;
    END
  END response_enable[3]
  PIN response_enable[4]
    DIRECTION OUTPUT ;
    USE SIGNAL ;
    PORT
      LAYER M4 ;
        RECT  220.236 50.736 220.32 50.76 ;
    END
  END response_enable[4]
  PIN response_seq[0]
    DIRECTION OUTPUT ;
    USE SIGNAL ;
    PORT
      LAYER M4 ;
        RECT  220.236 50.832 220.32 50.856 ;
    END
  END response_seq[0]
  PIN response_seq[1]
    DIRECTION OUTPUT ;
    USE SIGNAL ;
    PORT
      LAYER M4 ;
        RECT  220.236 50.928 220.32 50.952 ;
    END
  END response_seq[1]
  PIN response_seq[2]
    DIRECTION OUTPUT ;
    USE SIGNAL ;
    PORT
      LAYER M4 ;
        RECT  220.236 51.024 220.32 51.048 ;
    END
  END response_seq[2]
  PIN response_seq[3]
    DIRECTION OUTPUT ;
    USE SIGNAL ;
    PORT
      LAYER M4 ;
        RECT  220.236 51.12 220.32 51.144 ;
    END
  END response_seq[3]
  PIN response_seq[4]
    DIRECTION OUTPUT ;
    USE SIGNAL ;
    PORT
      LAYER M4 ;
        RECT  220.236 51.216 220.32 51.24 ;
    END
  END response_seq[4]
  PIN response_seq[5]
    DIRECTION OUTPUT ;
    USE SIGNAL ;
    PORT
      LAYER M4 ;
        RECT  220.236 51.312 220.32 51.336 ;
    END
  END response_seq[5]
  PIN response_seq[6]
    DIRECTION OUTPUT ;
    USE SIGNAL ;
    PORT
      LAYER M4 ;
        RECT  220.236 51.408 220.32 51.432 ;
    END
  END response_seq[6]
  PIN response_seq[7]
    DIRECTION OUTPUT ;
    USE SIGNAL ;
    PORT
      LAYER M4 ;
        RECT  220.236 51.504 220.32 51.528 ;
    END
  END response_seq[7]
  PIN response_seq[8]
    DIRECTION OUTPUT ;
    USE SIGNAL ;
    PORT
      LAYER M4 ;
        RECT  220.236 51.6 220.32 51.624 ;
    END
  END response_seq[8]
  PIN response_seq[9]
    DIRECTION OUTPUT ;
    USE SIGNAL ;
    PORT
      LAYER M4 ;
        RECT  220.236 51.696 220.32 51.72 ;
    END
  END response_seq[9]
  PIN ring_tx_enable[0]
    DIRECTION OUTPUT ;
    USE SIGNAL ;
    PORT
      LAYER M4 ;
        RECT  220.236 61.776 220.32 61.8 ;
    END
  END ring_tx_enable[0]
  PIN ring_tx_enable[1]
    DIRECTION OUTPUT ;
    USE SIGNAL ;
    PORT
      LAYER M4 ;
        RECT  220.236 61.872 220.32 61.896 ;
    END
  END ring_tx_enable[1]
  PIN ring_tx_source[0]
    DIRECTION OUTPUT ;
    USE SIGNAL ;
    PORT
      LAYER M4 ;
        RECT  220.236 61.968 220.32 61.992 ;
    END
  END ring_tx_source[0]
  PIN ring_tx_source[1]
    DIRECTION OUTPUT ;
    USE SIGNAL ;
    PORT
      LAYER M4 ;
        RECT  220.236 62.064 220.32 62.088 ;
    END
  END ring_tx_source[1]
  PIN ring_tx_source[2]
    DIRECTION OUTPUT ;
    USE SIGNAL ;
    PORT
      LAYER M4 ;
        RECT  220.236 62.16 220.32 62.184 ;
    END
  END ring_tx_source[2]
  PIN ring_tx_source[3]
    DIRECTION OUTPUT ;
    USE SIGNAL ;
    PORT
      LAYER M4 ;
        RECT  220.236 62.256 220.32 62.28 ;
    END
  END ring_tx_source[3]
  PIN ring_tx_source[4]
    DIRECTION OUTPUT ;
    USE SIGNAL ;
    PORT
      LAYER M4 ;
        RECT  220.236 62.352 220.32 62.376 ;
    END
  END ring_tx_source[4]
  PIN ring_tx_source[5]
    DIRECTION OUTPUT ;
    USE SIGNAL ;
    PORT
      LAYER M4 ;
        RECT  220.236 62.448 220.32 62.472 ;
    END
  END ring_tx_source[5]
  PIN rslot[0]
    DIRECTION OUTPUT ;
    USE SIGNAL ;
    PORT
      LAYER M4 ;
        RECT  220.236 57.168 220.32 57.192 ;
    END
  END rslot[0]
  PIN rslot[10]
    DIRECTION OUTPUT ;
    USE SIGNAL ;
    PORT
      LAYER M4 ;
        RECT  220.236 58.128 220.32 58.152 ;
    END
  END rslot[10]
  PIN rslot[11]
    DIRECTION OUTPUT ;
    USE SIGNAL ;
    PORT
      LAYER M4 ;
        RECT  220.236 58.224 220.32 58.248 ;
    END
  END rslot[11]
  PIN rslot[12]
    DIRECTION OUTPUT ;
    USE SIGNAL ;
    PORT
      LAYER M4 ;
        RECT  220.236 58.32 220.32 58.344 ;
    END
  END rslot[12]
  PIN rslot[13]
    DIRECTION OUTPUT ;
    USE SIGNAL ;
    PORT
      LAYER M4 ;
        RECT  220.236 58.416 220.32 58.44 ;
    END
  END rslot[13]
  PIN rslot[14]
    DIRECTION OUTPUT ;
    USE SIGNAL ;
    PORT
      LAYER M4 ;
        RECT  220.236 58.512 220.32 58.536 ;
    END
  END rslot[14]
  PIN rslot[15]
    DIRECTION OUTPUT ;
    USE SIGNAL ;
    PORT
      LAYER M4 ;
        RECT  220.236 58.608 220.32 58.632 ;
    END
  END rslot[15]
  PIN rslot[16]
    DIRECTION OUTPUT ;
    USE SIGNAL ;
    PORT
      LAYER M4 ;
        RECT  220.236 58.704 220.32 58.728 ;
    END
  END rslot[16]
  PIN rslot[17]
    DIRECTION OUTPUT ;
    USE SIGNAL ;
    PORT
      LAYER M4 ;
        RECT  220.236 58.8 220.32 58.824 ;
    END
  END rslot[17]
  PIN rslot[18]
    DIRECTION OUTPUT ;
    USE SIGNAL ;
    PORT
      LAYER M4 ;
        RECT  220.236 58.896 220.32 58.92 ;
    END
  END rslot[18]
  PIN rslot[19]
    DIRECTION OUTPUT ;
    USE SIGNAL ;
    PORT
      LAYER M4 ;
        RECT  220.236 58.992 220.32 59.016 ;
    END
  END rslot[19]
  PIN rslot[1]
    DIRECTION OUTPUT ;
    USE SIGNAL ;
    PORT
      LAYER M4 ;
        RECT  220.236 57.264 220.32 57.288 ;
    END
  END rslot[1]
  PIN rslot[20]
    DIRECTION OUTPUT ;
    USE SIGNAL ;
    PORT
      LAYER M4 ;
        RECT  220.236 59.088 220.32 59.112 ;
    END
  END rslot[20]
  PIN rslot[21]
    DIRECTION OUTPUT ;
    USE SIGNAL ;
    PORT
      LAYER M4 ;
        RECT  220.236 59.184 220.32 59.208 ;
    END
  END rslot[21]
  PIN rslot[22]
    DIRECTION OUTPUT ;
    USE SIGNAL ;
    PORT
      LAYER M4 ;
        RECT  220.236 59.28 220.32 59.304 ;
    END
  END rslot[22]
  PIN rslot[23]
    DIRECTION OUTPUT ;
    USE SIGNAL ;
    PORT
      LAYER M4 ;
        RECT  220.236 59.376 220.32 59.4 ;
    END
  END rslot[23]
  PIN rslot[2]
    DIRECTION OUTPUT ;
    USE SIGNAL ;
    PORT
      LAYER M4 ;
        RECT  220.236 57.36 220.32 57.384 ;
    END
  END rslot[2]
  PIN rslot[3]
    DIRECTION OUTPUT ;
    USE SIGNAL ;
    PORT
      LAYER M4 ;
        RECT  220.236 57.456 220.32 57.48 ;
    END
  END rslot[3]
  PIN rslot[4]
    DIRECTION OUTPUT ;
    USE SIGNAL ;
    PORT
      LAYER M4 ;
        RECT  220.236 57.552 220.32 57.576 ;
    END
  END rslot[4]
  PIN rslot[5]
    DIRECTION OUTPUT ;
    USE SIGNAL ;
    PORT
      LAYER M4 ;
        RECT  220.236 57.648 220.32 57.672 ;
    END
  END rslot[5]
  PIN rslot[6]
    DIRECTION OUTPUT ;
    USE SIGNAL ;
    PORT
      LAYER M4 ;
        RECT  220.236 57.744 220.32 57.768 ;
    END
  END rslot[6]
  PIN rslot[7]
    DIRECTION OUTPUT ;
    USE SIGNAL ;
    PORT
      LAYER M4 ;
        RECT  220.236 57.84 220.32 57.864 ;
    END
  END rslot[7]
  PIN rslot[8]
    DIRECTION OUTPUT ;
    USE SIGNAL ;
    PORT
      LAYER M4 ;
        RECT  220.236 57.936 220.32 57.96 ;
    END
  END rslot[8]
  PIN rslot[9]
    DIRECTION OUTPUT ;
    USE SIGNAL ;
    PORT
      LAYER M4 ;
        RECT  220.236 58.032 220.32 58.056 ;
    END
  END rslot[9]
  PIN rslot_v[0]
    DIRECTION OUTPUT ;
    USE SIGNAL ;
    PORT
      LAYER M4 ;
        RECT  220.236 55.632 220.32 55.656 ;
    END
  END rslot_v[0]
  PIN rslot_v[1]
    DIRECTION OUTPUT ;
    USE SIGNAL ;
    PORT
      LAYER M4 ;
        RECT  220.236 55.728 220.32 55.752 ;
    END
  END rslot_v[1]
  PIN rslot_v[2]
    DIRECTION OUTPUT ;
    USE SIGNAL ;
    PORT
      LAYER M4 ;
        RECT  220.236 55.824 220.32 55.848 ;
    END
  END rslot_v[2]
  PIN rslot_v[3]
    DIRECTION OUTPUT ;
    USE SIGNAL ;
    PORT
      LAYER M4 ;
        RECT  220.236 55.92 220.32 55.944 ;
    END
  END rslot_v[3]
  PIN rslot_v[4]
    DIRECTION OUTPUT ;
    USE SIGNAL ;
    PORT
      LAYER M4 ;
        RECT  220.236 56.016 220.32 56.04 ;
    END
  END rslot_v[4]
  PIN rslot_v[5]
    DIRECTION OUTPUT ;
    USE SIGNAL ;
    PORT
      LAYER M4 ;
        RECT  220.236 56.112 220.32 56.136 ;
    END
  END rslot_v[5]
  PIN rslot_v[6]
    DIRECTION OUTPUT ;
    USE SIGNAL ;
    PORT
      LAYER M4 ;
        RECT  220.236 56.208 220.32 56.232 ;
    END
  END rslot_v[6]
  PIN rslot_v[7]
    DIRECTION OUTPUT ;
    USE SIGNAL ;
    PORT
      LAYER M4 ;
        RECT  220.236 56.304 220.32 56.328 ;
    END
  END rslot_v[7]
  PIN rst_n
    DIRECTION INPUT ;
    USE SIGNAL ;
    PORT
      LAYER M4 ;
        RECT  0 43.776 0.084 43.8 ;
    END
  END rst_n
  PIN start_base[0]
    DIRECTION INPUT ;
    USE SIGNAL ;
    PORT
      LAYER M4 ;
        RECT  0 69.6 0.084 69.624 ;
    END
  END start_base[0]
  PIN start_base[1]
    DIRECTION INPUT ;
    USE SIGNAL ;
    PORT
      LAYER M4 ;
        RECT  0 69.696 0.084 69.72 ;
    END
  END start_base[1]
  PIN start_base[2]
    DIRECTION INPUT ;
    USE SIGNAL ;
    PORT
      LAYER M4 ;
        RECT  0 69.792 0.084 69.816 ;
    END
  END start_base[2]
  PIN start_base[3]
    DIRECTION INPUT ;
    USE SIGNAL ;
    PORT
      LAYER M4 ;
        RECT  0 69.888 0.084 69.912 ;
    END
  END start_base[3]
  PIN start_base[4]
    DIRECTION INPUT ;
    USE SIGNAL ;
    PORT
      LAYER M4 ;
        RECT  0 69.984 0.084 70.008 ;
    END
  END start_base[4]
  PIN start_base[5]
    DIRECTION INPUT ;
    USE SIGNAL ;
    PORT
      LAYER M4 ;
        RECT  0 70.08 0.084 70.104 ;
    END
  END start_base[5]
  PIN start_base[6]
    DIRECTION INPUT ;
    USE SIGNAL ;
    PORT
      LAYER M4 ;
        RECT  0 70.176 0.084 70.2 ;
    END
  END start_base[6]
  PIN start_base[7]
    DIRECTION INPUT ;
    USE SIGNAL ;
    PORT
      LAYER M4 ;
        RECT  0 70.272 0.084 70.296 ;
    END
  END start_base[7]
  PIN start_base[8]
    DIRECTION INPUT ;
    USE SIGNAL ;
    PORT
      LAYER M4 ;
        RECT  0 70.368 0.084 70.392 ;
    END
  END start_base[8]
  PIN start_base[9]
    DIRECTION INPUT ;
    USE SIGNAL ;
    PORT
      LAYER M4 ;
        RECT  0 70.464 0.084 70.488 ;
    END
  END start_base[9]
  PIN start_limit[0]
    DIRECTION INPUT ;
    USE SIGNAL ;
    PORT
      LAYER M4 ;
        RECT  0 70.56 0.084 70.584 ;
    END
  END start_limit[0]
  PIN start_limit[10]
    DIRECTION INPUT ;
    USE SIGNAL ;
    PORT
      LAYER M4 ;
        RECT  0 71.52 0.084 71.544 ;
    END
  END start_limit[10]
  PIN start_limit[1]
    DIRECTION INPUT ;
    USE SIGNAL ;
    PORT
      LAYER M4 ;
        RECT  0 70.656 0.084 70.68 ;
    END
  END start_limit[1]
  PIN start_limit[2]
    DIRECTION INPUT ;
    USE SIGNAL ;
    PORT
      LAYER M4 ;
        RECT  0 70.752 0.084 70.776 ;
    END
  END start_limit[2]
  PIN start_limit[3]
    DIRECTION INPUT ;
    USE SIGNAL ;
    PORT
      LAYER M4 ;
        RECT  0 70.848 0.084 70.872 ;
    END
  END start_limit[3]
  PIN start_limit[4]
    DIRECTION INPUT ;
    USE SIGNAL ;
    PORT
      LAYER M4 ;
        RECT  0 70.944 0.084 70.968 ;
    END
  END start_limit[4]
  PIN start_limit[5]
    DIRECTION INPUT ;
    USE SIGNAL ;
    PORT
      LAYER M4 ;
        RECT  0 71.04 0.084 71.064 ;
    END
  END start_limit[5]
  PIN start_limit[6]
    DIRECTION INPUT ;
    USE SIGNAL ;
    PORT
      LAYER M4 ;
        RECT  0 71.136 0.084 71.16 ;
    END
  END start_limit[6]
  PIN start_limit[7]
    DIRECTION INPUT ;
    USE SIGNAL ;
    PORT
      LAYER M4 ;
        RECT  0 71.232 0.084 71.256 ;
    END
  END start_limit[7]
  PIN start_limit[8]
    DIRECTION INPUT ;
    USE SIGNAL ;
    PORT
      LAYER M4 ;
        RECT  0 71.328 0.084 71.352 ;
    END
  END start_limit[8]
  PIN start_limit[9]
    DIRECTION INPUT ;
    USE SIGNAL ;
    PORT
      LAYER M4 ;
        RECT  0 71.424 0.084 71.448 ;
    END
  END start_limit[9]
  PIN start_loops[0]
    DIRECTION INPUT ;
    USE SIGNAL ;
    PORT
      LAYER M4 ;
        RECT  0 71.616 0.084 71.64 ;
    END
  END start_loops[0]
  PIN start_loops[10]
    DIRECTION INPUT ;
    USE SIGNAL ;
    PORT
      LAYER M4 ;
        RECT  0 72.576 0.084 72.6 ;
    END
  END start_loops[10]
  PIN start_loops[11]
    DIRECTION INPUT ;
    USE SIGNAL ;
    PORT
      LAYER M4 ;
        RECT  0 72.672 0.084 72.696 ;
    END
  END start_loops[11]
  PIN start_loops[12]
    DIRECTION INPUT ;
    USE SIGNAL ;
    PORT
      LAYER M4 ;
        RECT  0 72.768 0.084 72.792 ;
    END
  END start_loops[12]
  PIN start_loops[13]
    DIRECTION INPUT ;
    USE SIGNAL ;
    PORT
      LAYER M4 ;
        RECT  0 72.864 0.084 72.888 ;
    END
  END start_loops[13]
  PIN start_loops[14]
    DIRECTION INPUT ;
    USE SIGNAL ;
    PORT
      LAYER M4 ;
        RECT  0 72.96 0.084 72.984 ;
    END
  END start_loops[14]
  PIN start_loops[15]
    DIRECTION INPUT ;
    USE SIGNAL ;
    PORT
      LAYER M4 ;
        RECT  0 73.056 0.084 73.08 ;
    END
  END start_loops[15]
  PIN start_loops[1]
    DIRECTION INPUT ;
    USE SIGNAL ;
    PORT
      LAYER M4 ;
        RECT  0 71.712 0.084 71.736 ;
    END
  END start_loops[1]
  PIN start_loops[2]
    DIRECTION INPUT ;
    USE SIGNAL ;
    PORT
      LAYER M4 ;
        RECT  0 71.808 0.084 71.832 ;
    END
  END start_loops[2]
  PIN start_loops[3]
    DIRECTION INPUT ;
    USE SIGNAL ;
    PORT
      LAYER M4 ;
        RECT  0 71.904 0.084 71.928 ;
    END
  END start_loops[3]
  PIN start_loops[4]
    DIRECTION INPUT ;
    USE SIGNAL ;
    PORT
      LAYER M4 ;
        RECT  0 72 0.084 72.024 ;
    END
  END start_loops[4]
  PIN start_loops[5]
    DIRECTION INPUT ;
    USE SIGNAL ;
    PORT
      LAYER M4 ;
        RECT  0 72.096 0.084 72.12 ;
    END
  END start_loops[5]
  PIN start_loops[6]
    DIRECTION INPUT ;
    USE SIGNAL ;
    PORT
      LAYER M4 ;
        RECT  0 72.192 0.084 72.216 ;
    END
  END start_loops[6]
  PIN start_loops[7]
    DIRECTION INPUT ;
    USE SIGNAL ;
    PORT
      LAYER M4 ;
        RECT  0 72.288 0.084 72.312 ;
    END
  END start_loops[7]
  PIN start_loops[8]
    DIRECTION INPUT ;
    USE SIGNAL ;
    PORT
      LAYER M4 ;
        RECT  0 72.384 0.084 72.408 ;
    END
  END start_loops[8]
  PIN start_loops[9]
    DIRECTION INPUT ;
    USE SIGNAL ;
    PORT
      LAYER M4 ;
        RECT  0 72.48 0.084 72.504 ;
    END
  END start_loops[9]
  PIN start_v
    DIRECTION INPUT ;
    USE SIGNAL ;
    PORT
      LAYER M4 ;
        RECT  0 69.504 0.084 69.528 ;
    END
  END start_v
  PIN wslot[0]
    DIRECTION OUTPUT ;
    USE SIGNAL ;
    PORT
      LAYER M4 ;
        RECT  220.236 59.472 220.32 59.496 ;
    END
  END wslot[0]
  PIN wslot[10]
    DIRECTION OUTPUT ;
    USE SIGNAL ;
    PORT
      LAYER M4 ;
        RECT  220.236 60.432 220.32 60.456 ;
    END
  END wslot[10]
  PIN wslot[11]
    DIRECTION OUTPUT ;
    USE SIGNAL ;
    PORT
      LAYER M4 ;
        RECT  220.236 60.528 220.32 60.552 ;
    END
  END wslot[11]
  PIN wslot[12]
    DIRECTION OUTPUT ;
    USE SIGNAL ;
    PORT
      LAYER M4 ;
        RECT  220.236 60.624 220.32 60.648 ;
    END
  END wslot[12]
  PIN wslot[13]
    DIRECTION OUTPUT ;
    USE SIGNAL ;
    PORT
      LAYER M4 ;
        RECT  220.236 60.72 220.32 60.744 ;
    END
  END wslot[13]
  PIN wslot[14]
    DIRECTION OUTPUT ;
    USE SIGNAL ;
    PORT
      LAYER M4 ;
        RECT  220.236 60.816 220.32 60.84 ;
    END
  END wslot[14]
  PIN wslot[15]
    DIRECTION OUTPUT ;
    USE SIGNAL ;
    PORT
      LAYER M4 ;
        RECT  220.236 60.912 220.32 60.936 ;
    END
  END wslot[15]
  PIN wslot[16]
    DIRECTION OUTPUT ;
    USE SIGNAL ;
    PORT
      LAYER M4 ;
        RECT  220.236 61.008 220.32 61.032 ;
    END
  END wslot[16]
  PIN wslot[17]
    DIRECTION OUTPUT ;
    USE SIGNAL ;
    PORT
      LAYER M4 ;
        RECT  220.236 61.104 220.32 61.128 ;
    END
  END wslot[17]
  PIN wslot[18]
    DIRECTION OUTPUT ;
    USE SIGNAL ;
    PORT
      LAYER M4 ;
        RECT  220.236 61.2 220.32 61.224 ;
    END
  END wslot[18]
  PIN wslot[19]
    DIRECTION OUTPUT ;
    USE SIGNAL ;
    PORT
      LAYER M4 ;
        RECT  220.236 61.296 220.32 61.32 ;
    END
  END wslot[19]
  PIN wslot[1]
    DIRECTION OUTPUT ;
    USE SIGNAL ;
    PORT
      LAYER M4 ;
        RECT  220.236 59.568 220.32 59.592 ;
    END
  END wslot[1]
  PIN wslot[20]
    DIRECTION OUTPUT ;
    USE SIGNAL ;
    PORT
      LAYER M4 ;
        RECT  220.236 61.392 220.32 61.416 ;
    END
  END wslot[20]
  PIN wslot[21]
    DIRECTION OUTPUT ;
    USE SIGNAL ;
    PORT
      LAYER M4 ;
        RECT  220.236 61.488 220.32 61.512 ;
    END
  END wslot[21]
  PIN wslot[22]
    DIRECTION OUTPUT ;
    USE SIGNAL ;
    PORT
      LAYER M4 ;
        RECT  220.236 61.584 220.32 61.608 ;
    END
  END wslot[22]
  PIN wslot[23]
    DIRECTION OUTPUT ;
    USE SIGNAL ;
    PORT
      LAYER M4 ;
        RECT  220.236 61.68 220.32 61.704 ;
    END
  END wslot[23]
  PIN wslot[2]
    DIRECTION OUTPUT ;
    USE SIGNAL ;
    PORT
      LAYER M4 ;
        RECT  220.236 59.664 220.32 59.688 ;
    END
  END wslot[2]
  PIN wslot[3]
    DIRECTION OUTPUT ;
    USE SIGNAL ;
    PORT
      LAYER M4 ;
        RECT  220.236 59.76 220.32 59.784 ;
    END
  END wslot[3]
  PIN wslot[4]
    DIRECTION OUTPUT ;
    USE SIGNAL ;
    PORT
      LAYER M4 ;
        RECT  220.236 59.856 220.32 59.88 ;
    END
  END wslot[4]
  PIN wslot[5]
    DIRECTION OUTPUT ;
    USE SIGNAL ;
    PORT
      LAYER M4 ;
        RECT  220.236 59.952 220.32 59.976 ;
    END
  END wslot[5]
  PIN wslot[6]
    DIRECTION OUTPUT ;
    USE SIGNAL ;
    PORT
      LAYER M4 ;
        RECT  220.236 60.048 220.32 60.072 ;
    END
  END wslot[6]
  PIN wslot[7]
    DIRECTION OUTPUT ;
    USE SIGNAL ;
    PORT
      LAYER M4 ;
        RECT  220.236 60.144 220.32 60.168 ;
    END
  END wslot[7]
  PIN wslot[8]
    DIRECTION OUTPUT ;
    USE SIGNAL ;
    PORT
      LAYER M4 ;
        RECT  220.236 60.24 220.32 60.264 ;
    END
  END wslot[8]
  PIN wslot[9]
    DIRECTION OUTPUT ;
    USE SIGNAL ;
    PORT
      LAYER M4 ;
        RECT  220.236 60.336 220.32 60.36 ;
    END
  END wslot[9]
  PIN wslot_v[0]
    DIRECTION OUTPUT ;
    USE SIGNAL ;
    PORT
      LAYER M4 ;
        RECT  220.236 56.4 220.32 56.424 ;
    END
  END wslot_v[0]
  PIN wslot_v[1]
    DIRECTION OUTPUT ;
    USE SIGNAL ;
    PORT
      LAYER M4 ;
        RECT  220.236 56.496 220.32 56.52 ;
    END
  END wslot_v[1]
  PIN wslot_v[2]
    DIRECTION OUTPUT ;
    USE SIGNAL ;
    PORT
      LAYER M4 ;
        RECT  220.236 56.592 220.32 56.616 ;
    END
  END wslot_v[2]
  PIN wslot_v[3]
    DIRECTION OUTPUT ;
    USE SIGNAL ;
    PORT
      LAYER M4 ;
        RECT  220.236 56.688 220.32 56.712 ;
    END
  END wslot_v[3]
  PIN wslot_v[4]
    DIRECTION OUTPUT ;
    USE SIGNAL ;
    PORT
      LAYER M4 ;
        RECT  220.236 56.784 220.32 56.808 ;
    END
  END wslot_v[4]
  PIN wslot_v[5]
    DIRECTION OUTPUT ;
    USE SIGNAL ;
    PORT
      LAYER M4 ;
        RECT  220.236 56.88 220.32 56.904 ;
    END
  END wslot_v[5]
  PIN wslot_v[6]
    DIRECTION OUTPUT ;
    USE SIGNAL ;
    PORT
      LAYER M4 ;
        RECT  220.236 56.976 220.32 57 ;
    END
  END wslot_v[6]
  PIN wslot_v[7]
    DIRECTION OUTPUT ;
    USE SIGNAL ;
    PORT
      LAYER M4 ;
        RECT  220.236 57.072 220.32 57.096 ;
    END
  END wslot_v[7]
  PIN VDD
    DIRECTION INOUT ;
    USE POWER ;
    PORT
      LAYER M5 ;
        RECT  213.192 2.151 213.312 114.489 ;
        RECT  207.792 2.151 207.912 114.489 ;
        RECT  202.392 2.151 202.512 114.489 ;
        RECT  196.992 2.151 197.112 114.489 ;
        RECT  191.592 2.151 191.712 114.489 ;
        RECT  186.192 2.151 186.312 114.489 ;
        RECT  180.792 2.151 180.912 114.489 ;
        RECT  175.392 2.151 175.512 114.489 ;
        RECT  169.992 2.151 170.112 114.489 ;
        RECT  164.592 2.151 164.712 114.489 ;
        RECT  159.192 2.151 159.312 114.489 ;
        RECT  153.792 2.151 153.912 114.489 ;
        RECT  148.392 2.151 148.512 114.489 ;
        RECT  142.992 2.151 143.112 114.489 ;
        RECT  137.592 2.151 137.712 114.489 ;
        RECT  132.192 2.151 132.312 114.489 ;
        RECT  126.792 2.151 126.912 114.489 ;
        RECT  121.392 2.151 121.512 114.489 ;
        RECT  115.992 2.151 116.112 114.489 ;
        RECT  110.592 2.151 110.712 114.489 ;
        RECT  105.192 2.151 105.312 114.489 ;
        RECT  99.792 2.151 99.912 114.489 ;
        RECT  94.392 2.151 94.512 114.489 ;
        RECT  88.992 2.151 89.112 114.489 ;
        RECT  83.592 2.151 83.712 114.489 ;
        RECT  78.192 2.151 78.312 114.489 ;
        RECT  72.792 2.151 72.912 114.489 ;
        RECT  67.392 2.151 67.512 114.489 ;
        RECT  61.992 2.151 62.112 114.489 ;
        RECT  56.592 2.151 56.712 114.489 ;
        RECT  51.192 2.151 51.312 114.489 ;
        RECT  45.792 2.151 45.912 114.489 ;
        RECT  40.392 2.151 40.512 114.489 ;
        RECT  34.992 2.151 35.112 114.489 ;
        RECT  29.592 2.151 29.712 114.489 ;
        RECT  24.192 2.151 24.312 114.489 ;
        RECT  18.792 2.151 18.912 114.489 ;
        RECT  13.392 2.151 13.512 114.489 ;
        RECT  7.992 2.151 8.112 114.489 ;
        RECT  2.592 2.151 2.712 114.489 ;
    END
  END VDD
  PIN VSS
    DIRECTION INOUT ;
    USE GROUND ;
    PORT
      LAYER M5 ;
        RECT  213 2.137 213.12 114.503 ;
        RECT  207.6 2.137 207.72 114.503 ;
        RECT  202.2 2.137 202.32 114.503 ;
        RECT  196.8 2.137 196.92 114.503 ;
        RECT  191.4 2.137 191.52 114.503 ;
        RECT  186 2.137 186.12 114.503 ;
        RECT  180.6 2.137 180.72 114.503 ;
        RECT  175.2 2.137 175.32 114.503 ;
        RECT  169.8 2.137 169.92 114.503 ;
        RECT  164.4 2.137 164.52 114.503 ;
        RECT  159 2.137 159.12 114.503 ;
        RECT  153.6 2.137 153.72 114.503 ;
        RECT  148.2 2.137 148.32 114.503 ;
        RECT  142.8 2.137 142.92 114.503 ;
        RECT  137.4 2.137 137.52 114.503 ;
        RECT  132 2.137 132.12 114.503 ;
        RECT  126.6 2.137 126.72 114.503 ;
        RECT  121.2 2.137 121.32 114.503 ;
        RECT  115.8 2.137 115.92 114.503 ;
        RECT  110.4 2.137 110.52 114.503 ;
        RECT  105 2.137 105.12 114.503 ;
        RECT  99.6 2.137 99.72 114.503 ;
        RECT  94.2 2.137 94.32 114.503 ;
        RECT  88.8 2.137 88.92 114.503 ;
        RECT  83.4 2.137 83.52 114.503 ;
        RECT  78 2.137 78.12 114.503 ;
        RECT  72.6 2.137 72.72 114.503 ;
        RECT  67.2 2.137 67.32 114.503 ;
        RECT  61.8 2.137 61.92 114.503 ;
        RECT  56.4 2.137 56.52 114.503 ;
        RECT  51 2.137 51.12 114.503 ;
        RECT  45.6 2.137 45.72 114.503 ;
        RECT  40.2 2.137 40.32 114.503 ;
        RECT  34.8 2.137 34.92 114.503 ;
        RECT  29.4 2.137 29.52 114.503 ;
        RECT  24 2.137 24.12 114.503 ;
        RECT  18.6 2.137 18.72 114.503 ;
        RECT  13.2 2.137 13.32 114.503 ;
        RECT  7.8 2.137 7.92 114.503 ;
        RECT  2.4 2.137 2.52 114.503 ;
    END
  END VSS
  OBS
    LAYER RVTN ;
     RECT  2.16 2.16 218.16 2.295 ;
     RECT  2.16 2.565 218.16 2.835 ;
     RECT  2.16 3.105 218.16 3.375 ;
     RECT  2.16 3.645 218.16 3.915 ;
     RECT  2.16 4.185 218.16 4.455 ;
     RECT  2.16 4.725 218.16 4.995 ;
     RECT  2.16 5.265 218.16 5.535 ;
     RECT  2.16 5.805 218.16 6.075 ;
     RECT  2.16 6.345 218.16 6.615 ;
     RECT  2.16 6.885 218.16 7.155 ;
     RECT  2.16 7.425 218.16 7.695 ;
     RECT  2.16 7.965 218.16 8.235 ;
     RECT  2.16 8.505 218.16 8.775 ;
     RECT  2.16 9.045 218.16 9.315 ;
     RECT  2.16 9.585 218.16 9.855 ;
     RECT  2.16 10.125 218.16 10.395 ;
     RECT  2.16 10.665 218.16 10.935 ;
     RECT  2.16 11.205 218.16 11.475 ;
     RECT  2.16 11.745 218.16 12.015 ;
     RECT  2.16 12.285 218.16 12.555 ;
     RECT  2.16 12.825 218.16 13.095 ;
     RECT  2.16 13.365 218.16 13.635 ;
     RECT  2.16 13.905 218.16 14.175 ;
     RECT  2.16 14.445 218.16 14.715 ;
     RECT  2.16 14.985 218.16 15.255 ;
     RECT  2.16 15.525 218.16 15.795 ;
     RECT  2.16 16.065 218.16 16.335 ;
     RECT  2.16 16.605 218.16 16.875 ;
     RECT  2.16 17.145 218.16 17.415 ;
     RECT  2.16 17.685 218.16 17.955 ;
     RECT  2.16 18.225 218.16 18.495 ;
     RECT  2.16 18.765 218.16 19.035 ;
     RECT  2.16 19.305 218.16 19.575 ;
     RECT  2.16 19.845 218.16 20.115 ;
     RECT  2.16 20.385 218.16 20.655 ;
     RECT  2.16 20.925 218.16 21.195 ;
     RECT  2.16 21.465 218.16 21.6 ;
     RECT  2.16 21.6 20.844 21.735 ;
     RECT  199.692 21.6 218.16 21.735 ;
     RECT  2.16 22.005 20.844 22.275 ;
     RECT  199.692 22.005 218.16 22.275 ;
     RECT  2.16 22.545 20.844 22.815 ;
     RECT  199.692 22.545 218.16 22.815 ;
     RECT  2.16 23.085 20.844 23.355 ;
     RECT  199.692 23.085 218.16 23.355 ;
     RECT  2.16 23.625 20.844 23.895 ;
     RECT  199.692 23.625 218.16 23.895 ;
     RECT  2.16 24.165 20.844 24.435 ;
     RECT  199.692 24.165 218.16 24.435 ;
     RECT  2.16 24.705 20.844 24.975 ;
     RECT  199.692 24.705 218.16 24.975 ;
     RECT  2.16 25.245 20.844 25.515 ;
     RECT  199.692 25.245 218.16 25.515 ;
     RECT  2.16 25.785 20.844 26.055 ;
     RECT  199.692 25.785 218.16 26.055 ;
     RECT  2.16 26.325 20.844 26.595 ;
     RECT  199.692 26.325 218.16 26.595 ;
     RECT  2.16 26.865 20.844 27.135 ;
     RECT  199.692 26.865 218.16 27.135 ;
     RECT  2.16 27.405 20.844 27.675 ;
     RECT  199.692 27.405 218.16 27.675 ;
     RECT  2.16 27.945 20.844 28.215 ;
     RECT  199.692 27.945 218.16 28.215 ;
     RECT  2.16 28.485 20.844 28.755 ;
     RECT  199.692 28.485 218.16 28.755 ;
     RECT  2.16 29.025 20.844 29.295 ;
     RECT  199.692 29.025 218.16 29.295 ;
     RECT  2.16 29.565 20.844 29.835 ;
     RECT  199.692 29.565 218.16 29.835 ;
     RECT  2.16 30.105 20.844 30.375 ;
     RECT  199.692 30.105 218.16 30.375 ;
     RECT  2.16 30.645 20.844 30.915 ;
     RECT  199.692 30.645 218.16 30.915 ;
     RECT  2.16 31.185 20.844 31.455 ;
     RECT  199.692 31.185 218.16 31.455 ;
     RECT  2.16 31.725 20.844 31.995 ;
     RECT  199.692 31.725 218.16 31.995 ;
     RECT  2.16 32.265 20.844 32.535 ;
     RECT  199.692 32.265 218.16 32.535 ;
     RECT  2.16 32.805 20.844 33.075 ;
     RECT  199.692 32.805 218.16 33.075 ;
     RECT  2.16 33.345 20.844 33.615 ;
     RECT  199.692 33.345 218.16 33.615 ;
     RECT  2.16 33.885 20.844 34.155 ;
     RECT  199.692 33.885 218.16 34.155 ;
     RECT  2.16 34.425 20.844 34.695 ;
     RECT  199.692 34.425 218.16 34.695 ;
     RECT  2.16 34.965 20.844 35.235 ;
     RECT  199.692 34.965 218.16 35.235 ;
     RECT  2.16 35.505 20.844 35.775 ;
     RECT  199.692 35.505 218.16 35.775 ;
     RECT  2.16 36.045 20.844 36.315 ;
     RECT  199.692 36.045 218.16 36.315 ;
     RECT  2.16 36.585 20.844 36.855 ;
     RECT  199.692 36.585 218.16 36.855 ;
     RECT  2.16 37.125 20.844 37.395 ;
     RECT  199.692 37.125 218.16 37.395 ;
     RECT  2.16 37.665 20.844 37.935 ;
     RECT  199.692 37.665 218.16 37.935 ;
     RECT  2.16 38.205 20.844 38.475 ;
     RECT  199.692 38.205 218.16 38.475 ;
     RECT  2.16 38.745 20.844 39.015 ;
     RECT  199.692 38.745 218.16 39.015 ;
     RECT  2.16 39.285 20.844 39.555 ;
     RECT  199.692 39.285 218.16 39.555 ;
     RECT  2.16 39.825 20.844 40.095 ;
     RECT  199.692 39.825 218.16 40.095 ;
     RECT  2.16 40.365 20.844 40.635 ;
     RECT  199.692 40.365 218.16 40.635 ;
     RECT  2.16 40.905 20.844 41.175 ;
     RECT  199.692 40.905 218.16 41.175 ;
     RECT  2.16 41.445 20.844 41.715 ;
     RECT  199.692 41.445 218.16 41.715 ;
     RECT  2.16 41.985 20.844 42.255 ;
     RECT  199.692 41.985 218.16 42.255 ;
     RECT  2.16 42.525 20.844 42.795 ;
     RECT  199.692 42.525 218.16 42.795 ;
     RECT  2.16 43.065 20.844 43.335 ;
     RECT  199.692 43.065 218.16 43.335 ;
     RECT  2.16 43.605 20.844 43.875 ;
     RECT  199.692 43.605 218.16 43.875 ;
     RECT  2.16 44.145 20.844 44.415 ;
     RECT  199.692 44.145 218.16 44.415 ;
     RECT  2.16 44.685 20.844 44.955 ;
     RECT  199.692 44.685 218.16 44.955 ;
     RECT  2.16 45.225 20.844 45.495 ;
     RECT  199.692 45.225 218.16 45.495 ;
     RECT  2.16 45.765 20.844 46.035 ;
     RECT  199.692 45.765 218.16 46.035 ;
     RECT  2.16 46.305 20.844 46.575 ;
     RECT  199.692 46.305 218.16 46.575 ;
     RECT  2.16 46.845 20.844 47.115 ;
     RECT  199.692 46.845 218.16 47.115 ;
     RECT  2.16 47.385 20.844 47.655 ;
     RECT  199.692 47.385 218.16 47.655 ;
     RECT  2.16 47.925 20.844 48.195 ;
     RECT  199.692 47.925 218.16 48.195 ;
     RECT  2.16 48.465 20.844 48.735 ;
     RECT  199.692 48.465 218.16 48.735 ;
     RECT  2.16 49.005 20.844 49.275 ;
     RECT  199.692 49.005 218.16 49.275 ;
     RECT  2.16 49.545 20.844 49.815 ;
     RECT  199.692 49.545 218.16 49.815 ;
     RECT  2.16 50.085 20.844 50.355 ;
     RECT  199.692 50.085 218.16 50.355 ;
     RECT  2.16 50.625 20.844 50.895 ;
     RECT  199.692 50.625 218.16 50.895 ;
     RECT  2.16 51.165 20.844 51.435 ;
     RECT  199.692 51.165 218.16 51.435 ;
     RECT  2.16 51.705 20.844 51.975 ;
     RECT  199.692 51.705 218.16 51.975 ;
     RECT  2.16 52.245 20.844 52.515 ;
     RECT  199.692 52.245 218.16 52.515 ;
     RECT  2.16 52.785 20.844 53.055 ;
     RECT  199.692 52.785 218.16 53.055 ;
     RECT  2.16 53.325 20.844 53.595 ;
     RECT  199.692 53.325 218.16 53.595 ;
     RECT  2.16 53.865 20.844 54.135 ;
     RECT  199.692 53.865 218.16 54.135 ;
     RECT  2.16 54.405 20.844 54.675 ;
     RECT  199.692 54.405 218.16 54.675 ;
     RECT  2.16 54.945 20.844 55.215 ;
     RECT  199.692 54.945 218.16 55.215 ;
     RECT  2.16 55.485 20.844 55.755 ;
     RECT  199.692 55.485 218.16 55.755 ;
     RECT  2.16 56.025 20.844 56.295 ;
     RECT  199.692 56.025 218.16 56.295 ;
     RECT  2.16 56.565 20.844 56.835 ;
     RECT  199.692 56.565 218.16 56.835 ;
     RECT  2.16 57.105 20.844 57.375 ;
     RECT  199.692 57.105 218.16 57.375 ;
     RECT  2.16 57.645 20.844 57.915 ;
     RECT  199.692 57.645 218.16 57.915 ;
     RECT  2.16 58.185 20.844 58.455 ;
     RECT  199.692 58.185 218.16 58.455 ;
     RECT  2.16 58.725 20.844 58.995 ;
     RECT  199.692 58.725 218.16 58.995 ;
     RECT  2.16 59.265 20.844 59.535 ;
     RECT  199.692 59.265 218.16 59.535 ;
     RECT  2.16 59.805 20.844 60.075 ;
     RECT  199.692 59.805 218.16 60.075 ;
     RECT  2.16 60.345 20.844 60.615 ;
     RECT  199.692 60.345 218.16 60.615 ;
     RECT  2.16 60.885 20.844 61.155 ;
     RECT  199.692 60.885 218.16 61.155 ;
     RECT  2.16 61.425 20.844 61.695 ;
     RECT  199.692 61.425 218.16 61.695 ;
     RECT  2.16 61.965 20.844 62.235 ;
     RECT  199.692 61.965 218.16 62.235 ;
     RECT  2.16 62.505 20.844 62.775 ;
     RECT  199.692 62.505 218.16 62.775 ;
     RECT  2.16 63.045 20.844 63.315 ;
     RECT  199.692 63.045 218.16 63.315 ;
     RECT  2.16 63.585 20.844 63.855 ;
     RECT  199.692 63.585 218.16 63.855 ;
     RECT  2.16 64.125 20.844 64.395 ;
     RECT  199.692 64.125 218.16 64.395 ;
     RECT  2.16 64.665 20.844 64.935 ;
     RECT  199.692 64.665 218.16 64.935 ;
     RECT  2.16 65.205 20.844 65.475 ;
     RECT  199.692 65.205 218.16 65.475 ;
     RECT  2.16 65.745 20.844 66.015 ;
     RECT  199.692 65.745 218.16 66.015 ;
     RECT  2.16 66.285 20.844 66.555 ;
     RECT  199.692 66.285 218.16 66.555 ;
     RECT  2.16 66.825 20.844 67.095 ;
     RECT  199.692 66.825 218.16 67.095 ;
     RECT  2.16 67.365 20.844 67.635 ;
     RECT  199.692 67.365 218.16 67.635 ;
     RECT  2.16 67.905 20.844 68.175 ;
     RECT  199.692 67.905 218.16 68.175 ;
     RECT  2.16 68.445 20.844 68.715 ;
     RECT  199.692 68.445 218.16 68.715 ;
     RECT  2.16 68.985 20.844 69.255 ;
     RECT  199.692 68.985 218.16 69.255 ;
     RECT  2.16 69.525 20.844 69.795 ;
     RECT  199.692 69.525 218.16 69.795 ;
     RECT  2.16 70.065 20.844 70.335 ;
     RECT  199.692 70.065 218.16 70.335 ;
     RECT  2.16 70.605 20.844 70.875 ;
     RECT  199.692 70.605 218.16 70.875 ;
     RECT  2.16 71.145 20.844 71.415 ;
     RECT  199.692 71.145 218.16 71.415 ;
     RECT  2.16 71.685 20.844 71.955 ;
     RECT  199.692 71.685 218.16 71.955 ;
     RECT  2.16 72.225 20.844 72.495 ;
     RECT  199.692 72.225 218.16 72.495 ;
     RECT  2.16 72.765 20.844 73.035 ;
     RECT  199.692 72.765 218.16 73.035 ;
     RECT  2.16 73.305 20.844 73.575 ;
     RECT  199.692 73.305 218.16 73.575 ;
     RECT  2.16 73.845 20.844 74.115 ;
     RECT  199.692 73.845 218.16 74.115 ;
     RECT  2.16 74.385 20.844 74.655 ;
     RECT  199.692 74.385 218.16 74.655 ;
     RECT  2.16 74.925 20.844 75.195 ;
     RECT  199.692 74.925 218.16 75.195 ;
     RECT  2.16 75.465 20.844 75.735 ;
     RECT  199.692 75.465 218.16 75.735 ;
     RECT  2.16 76.005 20.844 76.275 ;
     RECT  199.692 76.005 218.16 76.275 ;
     RECT  2.16 76.545 20.844 76.815 ;
     RECT  199.692 76.545 218.16 76.815 ;
     RECT  2.16 77.085 20.844 77.355 ;
     RECT  199.692 77.085 218.16 77.355 ;
     RECT  2.16 77.625 20.844 77.895 ;
     RECT  199.692 77.625 218.16 77.895 ;
     RECT  2.16 78.165 20.844 78.435 ;
     RECT  199.692 78.165 218.16 78.435 ;
     RECT  2.16 78.705 20.844 78.975 ;
     RECT  199.692 78.705 218.16 78.975 ;
     RECT  2.16 79.245 20.844 79.515 ;
     RECT  199.692 79.245 218.16 79.515 ;
     RECT  2.16 79.785 20.844 80.055 ;
     RECT  199.692 79.785 218.16 80.055 ;
     RECT  2.16 80.325 20.844 80.595 ;
     RECT  199.692 80.325 218.16 80.595 ;
     RECT  2.16 80.865 20.844 81.135 ;
     RECT  199.692 80.865 218.16 81.135 ;
     RECT  2.16 81.405 20.844 81.675 ;
     RECT  199.692 81.405 218.16 81.675 ;
     RECT  2.16 81.945 20.844 82.215 ;
     RECT  199.692 81.945 218.16 82.215 ;
     RECT  2.16 82.485 20.844 82.755 ;
     RECT  199.692 82.485 218.16 82.755 ;
     RECT  2.16 83.025 20.844 83.295 ;
     RECT  199.692 83.025 218.16 83.295 ;
     RECT  2.16 83.565 20.844 83.835 ;
     RECT  199.692 83.565 218.16 83.835 ;
     RECT  2.16 84.105 20.844 84.375 ;
     RECT  199.692 84.105 218.16 84.375 ;
     RECT  2.16 84.645 20.844 84.915 ;
     RECT  199.692 84.645 218.16 84.915 ;
     RECT  2.16 85.185 20.844 85.455 ;
     RECT  199.692 85.185 218.16 85.455 ;
     RECT  2.16 85.725 20.844 85.995 ;
     RECT  199.692 85.725 218.16 85.995 ;
     RECT  2.16 86.265 20.844 86.535 ;
     RECT  199.692 86.265 218.16 86.535 ;
     RECT  2.16 86.805 20.844 87.075 ;
     RECT  199.692 86.805 218.16 87.075 ;
     RECT  2.16 87.345 20.844 87.615 ;
     RECT  199.692 87.345 218.16 87.615 ;
     RECT  2.16 87.885 20.844 88.155 ;
     RECT  199.692 87.885 218.16 88.155 ;
     RECT  2.16 88.425 20.844 88.695 ;
     RECT  199.692 88.425 218.16 88.695 ;
     RECT  2.16 88.965 20.844 89.235 ;
     RECT  199.692 88.965 218.16 89.235 ;
     RECT  2.16 89.505 20.844 89.775 ;
     RECT  199.692 89.505 218.16 89.775 ;
     RECT  2.16 90.045 20.844 90.315 ;
     RECT  199.692 90.045 218.16 90.315 ;
     RECT  2.16 90.585 20.844 90.855 ;
     RECT  199.692 90.585 218.16 90.855 ;
     RECT  2.16 91.125 20.844 91.395 ;
     RECT  199.692 91.125 218.16 91.395 ;
     RECT  2.16 91.665 20.844 91.935 ;
     RECT  199.692 91.665 218.16 91.935 ;
     RECT  2.16 92.205 20.844 92.475 ;
     RECT  199.692 92.205 218.16 92.475 ;
     RECT  2.16 92.745 20.844 93.015 ;
     RECT  199.692 92.745 218.16 93.015 ;
     RECT  2.16 93.285 20.844 93.555 ;
     RECT  199.692 93.285 218.16 93.555 ;
     RECT  2.16 93.825 20.844 94.095 ;
     RECT  199.692 93.825 218.16 94.095 ;
     RECT  2.16 94.365 20.844 94.635 ;
     RECT  199.692 94.365 218.16 94.635 ;
     RECT  2.16 94.905 20.844 95.175 ;
     RECT  199.692 94.905 218.16 95.175 ;
     RECT  2.16 95.445 20.844 95.715 ;
     RECT  199.692 95.445 218.16 95.715 ;
     RECT  2.16 95.985 20.844 96.255 ;
     RECT  199.692 95.985 218.16 96.255 ;
     RECT  2.16 96.525 218.16 96.795 ;
     RECT  2.16 97.065 218.16 97.335 ;
     RECT  2.16 97.605 218.16 97.875 ;
     RECT  2.16 98.145 218.16 98.415 ;
     RECT  2.16 98.685 218.16 98.955 ;
     RECT  2.16 99.225 218.16 99.495 ;
     RECT  2.16 99.765 218.16 100.035 ;
     RECT  2.16 100.305 218.16 100.575 ;
     RECT  2.16 100.845 218.16 101.115 ;
     RECT  2.16 101.385 218.16 101.655 ;
     RECT  2.16 101.925 218.16 102.195 ;
     RECT  2.16 102.465 218.16 102.735 ;
     RECT  2.16 103.005 218.16 103.275 ;
     RECT  2.16 103.545 218.16 103.815 ;
     RECT  2.16 104.085 218.16 104.355 ;
     RECT  2.16 104.625 218.16 104.895 ;
     RECT  2.16 105.165 218.16 105.435 ;
     RECT  2.16 105.705 218.16 105.975 ;
     RECT  2.16 106.245 218.16 106.515 ;
     RECT  2.16 106.785 218.16 107.055 ;
     RECT  2.16 107.325 218.16 107.595 ;
     RECT  2.16 107.865 218.16 108.135 ;
     RECT  2.16 108.405 218.16 108.675 ;
     RECT  2.16 108.945 218.16 109.215 ;
     RECT  2.16 109.485 218.16 109.755 ;
     RECT  2.16 110.025 218.16 110.295 ;
     RECT  2.16 110.565 218.16 110.835 ;
     RECT  2.16 111.105 218.16 111.375 ;
     RECT  2.16 111.645 218.16 111.915 ;
     RECT  2.16 112.185 218.16 112.455 ;
     RECT  2.16 112.725 218.16 112.995 ;
     RECT  2.16 113.265 218.16 113.535 ;
     RECT  2.16 113.805 218.16 114.075 ;
     RECT  2.16 114.345 218.16 114.48 ;
    LAYER RVTP ;
     RECT  2.16 2.295 218.16 2.565 ;
     RECT  2.16 2.835 218.16 3.105 ;
     RECT  2.16 3.375 218.16 3.645 ;
     RECT  2.16 3.915 218.16 4.185 ;
     RECT  2.16 4.455 218.16 4.725 ;
     RECT  2.16 4.995 218.16 5.265 ;
     RECT  2.16 5.535 218.16 5.805 ;
     RECT  2.16 6.075 218.16 6.345 ;
     RECT  2.16 6.615 218.16 6.885 ;
     RECT  2.16 7.155 218.16 7.425 ;
     RECT  2.16 7.695 218.16 7.965 ;
     RECT  2.16 8.235 218.16 8.505 ;
     RECT  2.16 8.775 218.16 9.045 ;
     RECT  2.16 9.315 218.16 9.585 ;
     RECT  2.16 9.855 218.16 10.125 ;
     RECT  2.16 10.395 218.16 10.665 ;
     RECT  2.16 10.935 218.16 11.205 ;
     RECT  2.16 11.475 218.16 11.745 ;
     RECT  2.16 12.015 218.16 12.285 ;
     RECT  2.16 12.555 218.16 12.825 ;
     RECT  2.16 13.095 218.16 13.365 ;
     RECT  2.16 13.635 218.16 13.905 ;
     RECT  2.16 14.175 218.16 14.445 ;
     RECT  2.16 14.715 218.16 14.985 ;
     RECT  2.16 15.255 218.16 15.525 ;
     RECT  2.16 15.795 218.16 16.065 ;
     RECT  2.16 16.335 218.16 16.605 ;
     RECT  2.16 16.875 218.16 17.145 ;
     RECT  2.16 17.415 218.16 17.685 ;
     RECT  2.16 17.955 218.16 18.225 ;
     RECT  2.16 18.495 218.16 18.765 ;
     RECT  2.16 19.035 218.16 19.305 ;
     RECT  2.16 19.575 218.16 19.845 ;
     RECT  2.16 20.115 218.16 20.385 ;
     RECT  2.16 20.655 218.16 20.925 ;
     RECT  2.16 21.195 218.16 21.465 ;
     RECT  2.16 21.735 20.844 22.005 ;
     RECT  199.692 21.735 218.16 22.005 ;
     RECT  2.16 22.275 20.844 22.545 ;
     RECT  199.692 22.275 218.16 22.545 ;
     RECT  2.16 22.815 20.844 23.085 ;
     RECT  199.692 22.815 218.16 23.085 ;
     RECT  2.16 23.355 20.844 23.625 ;
     RECT  199.692 23.355 218.16 23.625 ;
     RECT  2.16 23.895 20.844 24.165 ;
     RECT  199.692 23.895 218.16 24.165 ;
     RECT  2.16 24.435 20.844 24.705 ;
     RECT  199.692 24.435 218.16 24.705 ;
     RECT  2.16 24.975 20.844 25.245 ;
     RECT  199.692 24.975 218.16 25.245 ;
     RECT  2.16 25.515 20.844 25.785 ;
     RECT  199.692 25.515 218.16 25.785 ;
     RECT  2.16 26.055 20.844 26.325 ;
     RECT  199.692 26.055 218.16 26.325 ;
     RECT  2.16 26.595 20.844 26.865 ;
     RECT  199.692 26.595 218.16 26.865 ;
     RECT  2.16 27.135 20.844 27.405 ;
     RECT  199.692 27.135 218.16 27.405 ;
     RECT  2.16 27.675 20.844 27.945 ;
     RECT  199.692 27.675 218.16 27.945 ;
     RECT  2.16 28.215 20.844 28.485 ;
     RECT  199.692 28.215 218.16 28.485 ;
     RECT  2.16 28.755 20.844 29.025 ;
     RECT  199.692 28.755 218.16 29.025 ;
     RECT  2.16 29.295 20.844 29.565 ;
     RECT  199.692 29.295 218.16 29.565 ;
     RECT  2.16 29.835 20.844 30.105 ;
     RECT  199.692 29.835 218.16 30.105 ;
     RECT  2.16 30.375 20.844 30.645 ;
     RECT  199.692 30.375 218.16 30.645 ;
     RECT  2.16 30.915 20.844 31.185 ;
     RECT  199.692 30.915 218.16 31.185 ;
     RECT  2.16 31.455 20.844 31.725 ;
     RECT  199.692 31.455 218.16 31.725 ;
     RECT  2.16 31.995 20.844 32.265 ;
     RECT  199.692 31.995 218.16 32.265 ;
     RECT  2.16 32.535 20.844 32.805 ;
     RECT  199.692 32.535 218.16 32.805 ;
     RECT  2.16 33.075 20.844 33.345 ;
     RECT  199.692 33.075 218.16 33.345 ;
     RECT  2.16 33.615 20.844 33.885 ;
     RECT  199.692 33.615 218.16 33.885 ;
     RECT  2.16 34.155 20.844 34.425 ;
     RECT  199.692 34.155 218.16 34.425 ;
     RECT  2.16 34.695 20.844 34.965 ;
     RECT  199.692 34.695 218.16 34.965 ;
     RECT  2.16 35.235 20.844 35.505 ;
     RECT  199.692 35.235 218.16 35.505 ;
     RECT  2.16 35.775 20.844 36.045 ;
     RECT  199.692 35.775 218.16 36.045 ;
     RECT  2.16 36.315 20.844 36.585 ;
     RECT  199.692 36.315 218.16 36.585 ;
     RECT  2.16 36.855 20.844 37.125 ;
     RECT  199.692 36.855 218.16 37.125 ;
     RECT  2.16 37.395 20.844 37.665 ;
     RECT  199.692 37.395 218.16 37.665 ;
     RECT  2.16 37.935 20.844 38.205 ;
     RECT  199.692 37.935 218.16 38.205 ;
     RECT  2.16 38.475 20.844 38.745 ;
     RECT  199.692 38.475 218.16 38.745 ;
     RECT  2.16 39.015 20.844 39.285 ;
     RECT  199.692 39.015 218.16 39.285 ;
     RECT  2.16 39.555 20.844 39.825 ;
     RECT  199.692 39.555 218.16 39.825 ;
     RECT  2.16 40.095 20.844 40.365 ;
     RECT  199.692 40.095 218.16 40.365 ;
     RECT  2.16 40.635 20.844 40.905 ;
     RECT  199.692 40.635 218.16 40.905 ;
     RECT  2.16 41.175 20.844 41.445 ;
     RECT  199.692 41.175 218.16 41.445 ;
     RECT  2.16 41.715 20.844 41.985 ;
     RECT  199.692 41.715 218.16 41.985 ;
     RECT  2.16 42.255 20.844 42.525 ;
     RECT  199.692 42.255 218.16 42.525 ;
     RECT  2.16 42.795 20.844 43.065 ;
     RECT  199.692 42.795 218.16 43.065 ;
     RECT  2.16 43.335 20.844 43.605 ;
     RECT  199.692 43.335 218.16 43.605 ;
     RECT  2.16 43.875 20.844 44.145 ;
     RECT  199.692 43.875 218.16 44.145 ;
     RECT  2.16 44.415 20.844 44.685 ;
     RECT  199.692 44.415 218.16 44.685 ;
     RECT  2.16 44.955 20.844 45.225 ;
     RECT  199.692 44.955 218.16 45.225 ;
     RECT  2.16 45.495 20.844 45.765 ;
     RECT  199.692 45.495 218.16 45.765 ;
     RECT  2.16 46.035 20.844 46.305 ;
     RECT  199.692 46.035 218.16 46.305 ;
     RECT  2.16 46.575 20.844 46.845 ;
     RECT  199.692 46.575 218.16 46.845 ;
     RECT  2.16 47.115 20.844 47.385 ;
     RECT  199.692 47.115 218.16 47.385 ;
     RECT  2.16 47.655 20.844 47.925 ;
     RECT  199.692 47.655 218.16 47.925 ;
     RECT  2.16 48.195 20.844 48.465 ;
     RECT  199.692 48.195 218.16 48.465 ;
     RECT  2.16 48.735 20.844 49.005 ;
     RECT  199.692 48.735 218.16 49.005 ;
     RECT  2.16 49.275 20.844 49.545 ;
     RECT  199.692 49.275 218.16 49.545 ;
     RECT  2.16 49.815 20.844 50.085 ;
     RECT  199.692 49.815 218.16 50.085 ;
     RECT  2.16 50.355 20.844 50.625 ;
     RECT  199.692 50.355 218.16 50.625 ;
     RECT  2.16 50.895 20.844 51.165 ;
     RECT  199.692 50.895 218.16 51.165 ;
     RECT  2.16 51.435 20.844 51.705 ;
     RECT  199.692 51.435 218.16 51.705 ;
     RECT  2.16 51.975 20.844 52.245 ;
     RECT  199.692 51.975 218.16 52.245 ;
     RECT  2.16 52.515 20.844 52.785 ;
     RECT  199.692 52.515 218.16 52.785 ;
     RECT  2.16 53.055 20.844 53.325 ;
     RECT  199.692 53.055 218.16 53.325 ;
     RECT  2.16 53.595 20.844 53.865 ;
     RECT  199.692 53.595 218.16 53.865 ;
     RECT  2.16 54.135 20.844 54.405 ;
     RECT  199.692 54.135 218.16 54.405 ;
     RECT  2.16 54.675 20.844 54.945 ;
     RECT  199.692 54.675 218.16 54.945 ;
     RECT  2.16 55.215 20.844 55.485 ;
     RECT  199.692 55.215 218.16 55.485 ;
     RECT  2.16 55.755 20.844 56.025 ;
     RECT  199.692 55.755 218.16 56.025 ;
     RECT  2.16 56.295 20.844 56.565 ;
     RECT  199.692 56.295 218.16 56.565 ;
     RECT  2.16 56.835 20.844 57.105 ;
     RECT  199.692 56.835 218.16 57.105 ;
     RECT  2.16 57.375 20.844 57.645 ;
     RECT  199.692 57.375 218.16 57.645 ;
     RECT  2.16 57.915 20.844 58.185 ;
     RECT  199.692 57.915 218.16 58.185 ;
     RECT  2.16 58.455 20.844 58.725 ;
     RECT  199.692 58.455 218.16 58.725 ;
     RECT  2.16 58.995 20.844 59.265 ;
     RECT  199.692 58.995 218.16 59.265 ;
     RECT  2.16 59.535 20.844 59.805 ;
     RECT  199.692 59.535 218.16 59.805 ;
     RECT  2.16 60.075 20.844 60.345 ;
     RECT  199.692 60.075 218.16 60.345 ;
     RECT  2.16 60.615 20.844 60.885 ;
     RECT  199.692 60.615 218.16 60.885 ;
     RECT  2.16 61.155 20.844 61.425 ;
     RECT  199.692 61.155 218.16 61.425 ;
     RECT  2.16 61.695 20.844 61.965 ;
     RECT  199.692 61.695 218.16 61.965 ;
     RECT  2.16 62.235 20.844 62.505 ;
     RECT  199.692 62.235 218.16 62.505 ;
     RECT  2.16 62.775 20.844 63.045 ;
     RECT  199.692 62.775 218.16 63.045 ;
     RECT  2.16 63.315 20.844 63.585 ;
     RECT  199.692 63.315 218.16 63.585 ;
     RECT  2.16 63.855 20.844 64.125 ;
     RECT  199.692 63.855 218.16 64.125 ;
     RECT  2.16 64.395 20.844 64.665 ;
     RECT  199.692 64.395 218.16 64.665 ;
     RECT  2.16 64.935 20.844 65.205 ;
     RECT  199.692 64.935 218.16 65.205 ;
     RECT  2.16 65.475 20.844 65.745 ;
     RECT  199.692 65.475 218.16 65.745 ;
     RECT  2.16 66.015 20.844 66.285 ;
     RECT  199.692 66.015 218.16 66.285 ;
     RECT  2.16 66.555 20.844 66.825 ;
     RECT  199.692 66.555 218.16 66.825 ;
     RECT  2.16 67.095 20.844 67.365 ;
     RECT  199.692 67.095 218.16 67.365 ;
     RECT  2.16 67.635 20.844 67.905 ;
     RECT  199.692 67.635 218.16 67.905 ;
     RECT  2.16 68.175 20.844 68.445 ;
     RECT  199.692 68.175 218.16 68.445 ;
     RECT  2.16 68.715 20.844 68.985 ;
     RECT  199.692 68.715 218.16 68.985 ;
     RECT  2.16 69.255 20.844 69.525 ;
     RECT  199.692 69.255 218.16 69.525 ;
     RECT  2.16 69.795 20.844 70.065 ;
     RECT  199.692 69.795 218.16 70.065 ;
     RECT  2.16 70.335 20.844 70.605 ;
     RECT  199.692 70.335 218.16 70.605 ;
     RECT  2.16 70.875 20.844 71.145 ;
     RECT  199.692 70.875 218.16 71.145 ;
     RECT  2.16 71.415 20.844 71.685 ;
     RECT  199.692 71.415 218.16 71.685 ;
     RECT  2.16 71.955 20.844 72.225 ;
     RECT  199.692 71.955 218.16 72.225 ;
     RECT  2.16 72.495 20.844 72.765 ;
     RECT  199.692 72.495 218.16 72.765 ;
     RECT  2.16 73.035 20.844 73.305 ;
     RECT  199.692 73.035 218.16 73.305 ;
     RECT  2.16 73.575 20.844 73.845 ;
     RECT  199.692 73.575 218.16 73.845 ;
     RECT  2.16 74.115 20.844 74.385 ;
     RECT  199.692 74.115 218.16 74.385 ;
     RECT  2.16 74.655 20.844 74.925 ;
     RECT  199.692 74.655 218.16 74.925 ;
     RECT  2.16 75.195 20.844 75.465 ;
     RECT  199.692 75.195 218.16 75.465 ;
     RECT  2.16 75.735 20.844 76.005 ;
     RECT  199.692 75.735 218.16 76.005 ;
     RECT  2.16 76.275 20.844 76.545 ;
     RECT  199.692 76.275 218.16 76.545 ;
     RECT  2.16 76.815 20.844 77.085 ;
     RECT  199.692 76.815 218.16 77.085 ;
     RECT  2.16 77.355 20.844 77.625 ;
     RECT  199.692 77.355 218.16 77.625 ;
     RECT  2.16 77.895 20.844 78.165 ;
     RECT  199.692 77.895 218.16 78.165 ;
     RECT  2.16 78.435 20.844 78.705 ;
     RECT  199.692 78.435 218.16 78.705 ;
     RECT  2.16 78.975 20.844 79.245 ;
     RECT  199.692 78.975 218.16 79.245 ;
     RECT  2.16 79.515 20.844 79.785 ;
     RECT  199.692 79.515 218.16 79.785 ;
     RECT  2.16 80.055 20.844 80.325 ;
     RECT  199.692 80.055 218.16 80.325 ;
     RECT  2.16 80.595 20.844 80.865 ;
     RECT  199.692 80.595 218.16 80.865 ;
     RECT  2.16 81.135 20.844 81.405 ;
     RECT  199.692 81.135 218.16 81.405 ;
     RECT  2.16 81.675 20.844 81.945 ;
     RECT  199.692 81.675 218.16 81.945 ;
     RECT  2.16 82.215 20.844 82.485 ;
     RECT  199.692 82.215 218.16 82.485 ;
     RECT  2.16 82.755 20.844 83.025 ;
     RECT  199.692 82.755 218.16 83.025 ;
     RECT  2.16 83.295 20.844 83.565 ;
     RECT  199.692 83.295 218.16 83.565 ;
     RECT  2.16 83.835 20.844 84.105 ;
     RECT  199.692 83.835 218.16 84.105 ;
     RECT  2.16 84.375 20.844 84.645 ;
     RECT  199.692 84.375 218.16 84.645 ;
     RECT  2.16 84.915 20.844 85.185 ;
     RECT  199.692 84.915 218.16 85.185 ;
     RECT  2.16 85.455 20.844 85.725 ;
     RECT  199.692 85.455 218.16 85.725 ;
     RECT  2.16 85.995 20.844 86.265 ;
     RECT  199.692 85.995 218.16 86.265 ;
     RECT  2.16 86.535 20.844 86.805 ;
     RECT  199.692 86.535 218.16 86.805 ;
     RECT  2.16 87.075 20.844 87.345 ;
     RECT  199.692 87.075 218.16 87.345 ;
     RECT  2.16 87.615 20.844 87.885 ;
     RECT  199.692 87.615 218.16 87.885 ;
     RECT  2.16 88.155 20.844 88.425 ;
     RECT  199.692 88.155 218.16 88.425 ;
     RECT  2.16 88.695 20.844 88.965 ;
     RECT  199.692 88.695 218.16 88.965 ;
     RECT  2.16 89.235 20.844 89.505 ;
     RECT  199.692 89.235 218.16 89.505 ;
     RECT  2.16 89.775 20.844 90.045 ;
     RECT  199.692 89.775 218.16 90.045 ;
     RECT  2.16 90.315 20.844 90.585 ;
     RECT  199.692 90.315 218.16 90.585 ;
     RECT  2.16 90.855 20.844 91.125 ;
     RECT  199.692 90.855 218.16 91.125 ;
     RECT  2.16 91.395 20.844 91.665 ;
     RECT  199.692 91.395 218.16 91.665 ;
     RECT  2.16 91.935 20.844 92.205 ;
     RECT  199.692 91.935 218.16 92.205 ;
     RECT  2.16 92.475 20.844 92.745 ;
     RECT  199.692 92.475 218.16 92.745 ;
     RECT  2.16 93.015 20.844 93.285 ;
     RECT  199.692 93.015 218.16 93.285 ;
     RECT  2.16 93.555 20.844 93.825 ;
     RECT  199.692 93.555 218.16 93.825 ;
     RECT  2.16 94.095 20.844 94.365 ;
     RECT  199.692 94.095 218.16 94.365 ;
     RECT  2.16 94.635 20.844 94.905 ;
     RECT  199.692 94.635 218.16 94.905 ;
     RECT  2.16 95.175 20.844 95.445 ;
     RECT  199.692 95.175 218.16 95.445 ;
     RECT  2.16 95.715 20.844 95.985 ;
     RECT  199.692 95.715 218.16 95.985 ;
     RECT  2.16 96.255 20.844 96.39 ;
     RECT  199.692 96.255 218.16 96.39 ;
     RECT  2.16 96.39 218.16 96.525 ;
     RECT  2.16 96.795 218.16 97.065 ;
     RECT  2.16 97.335 218.16 97.605 ;
     RECT  2.16 97.875 218.16 98.145 ;
     RECT  2.16 98.415 218.16 98.685 ;
     RECT  2.16 98.955 218.16 99.225 ;
     RECT  2.16 99.495 218.16 99.765 ;
     RECT  2.16 100.035 218.16 100.305 ;
     RECT  2.16 100.575 218.16 100.845 ;
     RECT  2.16 101.115 218.16 101.385 ;
     RECT  2.16 101.655 218.16 101.925 ;
     RECT  2.16 102.195 218.16 102.465 ;
     RECT  2.16 102.735 218.16 103.005 ;
     RECT  2.16 103.275 218.16 103.545 ;
     RECT  2.16 103.815 218.16 104.085 ;
     RECT  2.16 104.355 218.16 104.625 ;
     RECT  2.16 104.895 218.16 105.165 ;
     RECT  2.16 105.435 218.16 105.705 ;
     RECT  2.16 105.975 218.16 106.245 ;
     RECT  2.16 106.515 218.16 106.785 ;
     RECT  2.16 107.055 218.16 107.325 ;
     RECT  2.16 107.595 218.16 107.865 ;
     RECT  2.16 108.135 218.16 108.405 ;
     RECT  2.16 108.675 218.16 108.945 ;
     RECT  2.16 109.215 218.16 109.485 ;
     RECT  2.16 109.755 218.16 110.025 ;
     RECT  2.16 110.295 218.16 110.565 ;
     RECT  2.16 110.835 218.16 111.105 ;
     RECT  2.16 111.375 218.16 111.645 ;
     RECT  2.16 111.915 218.16 112.185 ;
     RECT  2.16 112.455 218.16 112.725 ;
     RECT  2.16 112.995 218.16 113.265 ;
     RECT  2.16 113.535 218.16 113.805 ;
     RECT  2.16 114.075 218.16 114.345 ;
    LAYER M1 ;
     RECT  2.16 2.151 218.16 21.609 ;
     RECT  22.896 23.76 197.64 94.248 ;
     RECT  2.16 21.609 20.844 96.381 ;
     RECT  199.692 21.609 218.16 96.381 ;
     RECT  2.16 96.381 218.16 114.489 ;
    LAYER M2 ;
     RECT  0.103 43.11 0.139 43.128 ;
     RECT  0.103 44.622 0.139 45.18 ;
     RECT  0.103 48.276 0.139 48.42 ;
     RECT  0.103 53.568 0.139 53.586 ;
     RECT  0.103 56.34 0.139 56.628 ;
     RECT  0.103 61.092 0.139 61.92 ;
     RECT  0.103 63.054 0.139 63.954 ;
     RECT  0.103 65.79 0.139 65.808 ;
     RECT  0.103 67.032 0.139 67.05 ;
     RECT  0.103 71.622 0.139 71.64 ;
     RECT  0.139 63.054 0.175 64.656 ;
     RECT  0.139 65.448 0.175 65.808 ;
     RECT  0.139 47.736 0.211 48.42 ;
     RECT  0.103 69.462 0.247 69.48 ;
     RECT  0.175 63.054 0.283 65.808 ;
     RECT  0.103 49.518 0.347 50.04 ;
     RECT  0.139 61.092 0.499 61.992 ;
     RECT  0.139 43.11 0.535 45.18 ;
     RECT  0.347 49.554 0.535 50.04 ;
     RECT  0.139 51.912 0.535 51.93 ;
     RECT  0.139 52.866 0.535 53.586 ;
     RECT  0.103 55.26 0.535 55.278 ;
     RECT  0.139 56.232 0.535 57.06 ;
     RECT  0.103 58.464 0.535 58.95 ;
     RECT  0.499 61.092 0.535 62.154 ;
     RECT  0.247 69.228 0.535 69.48 ;
     RECT  0.103 70.578 0.535 70.596 ;
     RECT  0.139 71.622 0.535 72.18 ;
     RECT  0.463 46.89 0.563 46.908 ;
     RECT  0.535 49.554 1.147 55.278 ;
     RECT  0.535 56.232 1.147 57.708 ;
     RECT  0.535 58.464 1.147 59.364 ;
     RECT  0.535 61.092 1.147 62.298 ;
     RECT  0.283 63.054 1.147 65.97 ;
     RECT  0.535 69.228 1.147 69.786 ;
     RECT  0.175 60.282 1.183 60.3 ;
     RECT  1.147 61.092 1.183 65.97 ;
     RECT  1.147 68.796 1.219 69.786 ;
     RECT  0.535 70.578 1.219 72.18 ;
     RECT  1.219 68.796 1.255 72.18 ;
     RECT  1.147 73.008 1.255 73.026 ;
     RECT  1.147 56.232 1.291 59.364 ;
     RECT  1.183 60.282 1.291 65.97 ;
     RECT  0.103 74.322 1.327 74.34 ;
     RECT  1.291 56.232 1.363 65.97 ;
     RECT  0.103 67.914 1.399 67.932 ;
     RECT  1.255 68.796 1.399 73.026 ;
     RECT  0.139 67.032 1.507 67.086 ;
     RECT  1.399 67.914 1.507 73.098 ;
     RECT  0.211 47.7 1.723 48.42 ;
     RECT  1.147 49.284 1.723 55.278 ;
     RECT  0.103 46.08 1.759 46.098 ;
     RECT  1.723 47.052 1.759 48.42 ;
     RECT  0.535 43.11 2.16 45.288 ;
     RECT  1.759 46.08 2.16 48.42 ;
     RECT  1.723 49.212 2.16 55.278 ;
     RECT  1.363 56.07 2.16 65.97 ;
     RECT  1.507 67.032 2.16 73.098 ;
     RECT  1.327 73.89 2.16 74.34 ;
     RECT  2.16 2.151 20.844 114.489 ;
     RECT  20.844 66.726 21.047 67.662 ;
     RECT  20.844 2.151 21.659 65.232 ;
     RECT  21.659 2.151 21.911 62.874 ;
     RECT  20.844 78.372 21.983 78.39 ;
     RECT  21.911 25.866 22.127 62.874 ;
     RECT  21.911 2.151 22.896 24.768 ;
     RECT  22.127 25.866 22.896 53.82 ;
     RECT  22.127 54.648 22.896 62.874 ;
     RECT  21.659 64.566 22.896 65.232 ;
     RECT  21.047 66.726 22.896 66.744 ;
     RECT  21.047 67.644 22.896 67.662 ;
     RECT  20.844 76.086 22.896 76.734 ;
     RECT  20.844 83.502 22.896 83.52 ;
     RECT  20.844 89.748 22.896 89.766 ;
     RECT  20.844 93.762 22.896 114.489 ;
     RECT  22.896 2.151 88.943 114.489 ;
     RECT  88.943 2.151 89.995 94.968 ;
     RECT  88.943 96.03 89.995 114.489 ;
     RECT  89.995 2.151 106.411 114.489 ;
     RECT  106.411 1.962 106.627 114.489 ;
     RECT  106.627 1.881 108.959 114.489 ;
     RECT  108.959 1.962 109.211 114.489 ;
     RECT  109.211 2.034 109.643 114.489 ;
     RECT  109.643 2.106 111.559 114.489 ;
     RECT  111.559 1.881 113.243 114.489 ;
     RECT  113.243 1.926 114.575 114.489 ;
     RECT  114.575 1.962 115.511 114.489 ;
     RECT  115.511 2.151 197.64 114.489 ;
     RECT  197.64 2.151 197.843 23.994 ;
     RECT  197.64 69.426 198.383 69.516 ;
     RECT  197.64 44.352 198.391 44.37 ;
     RECT  197.64 53.136 198.391 53.388 ;
     RECT  197.64 24.876 198.427 24.894 ;
     RECT  198.427 24.714 198.491 24.894 ;
     RECT  198.491 24.714 198.599 24.804 ;
     RECT  197.64 61.704 198.679 62.028 ;
     RECT  197.64 66.906 198.679 67.824 ;
     RECT  197.64 37.026 198.859 37.494 ;
     RECT  197.64 43.272 198.859 43.29 ;
     RECT  198.391 44.352 198.859 44.442 ;
     RECT  197.64 47.286 198.859 50.688 ;
     RECT  198.599 24.786 198.887 24.804 ;
     RECT  198.859 36.864 198.895 37.494 ;
     RECT  198.859 40.266 198.895 40.824 ;
     RECT  198.823 42.498 198.895 42.516 ;
     RECT  198.859 43.272 198.895 44.442 ;
     RECT  197.64 35.856 198.931 35.874 ;
     RECT  198.895 36.864 198.931 40.968 ;
     RECT  198.895 41.886 198.931 45.018 ;
     RECT  198.859 47.016 198.931 50.688 ;
     RECT  198.391 53.136 198.931 53.424 ;
     RECT  197.64 77.562 199.183 77.58 ;
     RECT  198.383 69.498 199.219 69.516 ;
     RECT  199.147 26.766 199.255 26.784 ;
     RECT  197.64 63.054 199.255 65.574 ;
     RECT  198.679 66.366 199.255 67.824 ;
     RECT  197.64 70.686 199.255 70.866 ;
     RECT  199.255 63.054 199.291 67.824 ;
     RECT  199.219 68.616 199.291 68.634 ;
     RECT  198.931 35.856 199.507 53.424 ;
     RECT  198.751 58.698 199.507 58.716 ;
     RECT  198.715 60.516 199.507 60.534 ;
     RECT  198.679 61.326 199.543 62.028 ;
     RECT  199.291 63.054 199.543 68.634 ;
     RECT  199.255 70.686 199.543 70.974 ;
     RECT  197.843 2.151 199.579 23.814 ;
     RECT  199.255 26.721 199.615 26.784 ;
     RECT  199.219 69.498 199.615 69.894 ;
     RECT  199.543 70.686 199.615 71.064 ;
     RECT  199.543 61.326 199.651 68.634 ;
     RECT  199.615 69.498 199.651 71.064 ;
     RECT  199.579 2.151 199.692 23.922 ;
     RECT  199.615 26.676 199.692 26.784 ;
     RECT  199.291 29.376 199.692 29.394 ;
     RECT  197.64 31.086 199.692 31.104 ;
     RECT  199.507 35.856 199.692 57.564 ;
     RECT  199.507 58.536 199.692 60.534 ;
     RECT  199.651 61.326 199.692 71.064 ;
     RECT  199.183 77.562 199.692 77.652 ;
     RECT  199.183 83.502 199.692 83.52 ;
     RECT  198.607 89.748 199.692 89.766 ;
     RECT  197.64 94.338 199.692 114.489 ;
     RECT  199.692 2.151 218.16 114.489 ;
     RECT  218.16 48.276 218.255 60.3 ;
     RECT  218.255 48.546 218.291 60.3 ;
     RECT  218.16 61.056 218.291 69.174 ;
     RECT  218.291 48.546 218.867 59.724 ;
     RECT  218.291 61.056 218.867 68.742 ;
     RECT  218.867 48.546 218.903 52.074 ;
     RECT  218.867 53.136 218.903 59.724 ;
     RECT  218.903 50.328 218.975 52.038 ;
     RECT  218.903 48.546 219.047 49.536 ;
     RECT  218.867 67.446 219.155 68.742 ;
     RECT  218.903 53.532 219.443 59.724 ;
     RECT  219.047 48.546 219.479 48.564 ;
     RECT  218.975 50.526 219.479 52.038 ;
     RECT  219.443 53.64 219.479 57.096 ;
     RECT  219.443 57.888 219.479 59.724 ;
     RECT  219.479 51.066 219.515 51.624 ;
     RECT  218.867 62.586 219.515 66.654 ;
     RECT  219.515 51.138 219.551 51.624 ;
     RECT  219.479 54.486 219.551 57.096 ;
     RECT  219.551 57.006 219.587 57.096 ;
     RECT  219.587 57.078 219.623 57.096 ;
     RECT  218.867 61.056 219.991 61.254 ;
     RECT  219.991 61.056 220.027 61.344 ;
     RECT  219.515 64.746 220.163 66.654 ;
     RECT  219.551 51.138 220.199 51.156 ;
     RECT  219.551 54.486 220.199 56.214 ;
     RECT  220.027 61.056 220.199 61.488 ;
     RECT  219.515 62.586 220.199 63.612 ;
     RECT  220.163 66.096 220.199 66.654 ;
     RECT  219.155 67.446 220.199 68.274 ;
     RECT  219.479 57.888 220.207 57.906 ;
     RECT  219.047 49.446 220.235 49.536 ;
     RECT  219.479 53.64 220.235 53.658 ;
     RECT  220.199 54.846 220.235 54.864 ;
     RECT  220.199 56.196 220.235 56.214 ;
     RECT  220.207 57.888 220.235 58.176 ;
     RECT  219.479 59.076 220.235 59.526 ;
     RECT  220.199 61.056 220.235 61.254 ;
     RECT  220.199 62.586 220.235 62.604 ;
     RECT  220.199 63.594 220.235 63.612 ;
     RECT  220.163 64.746 220.235 65.268 ;
     RECT  220.199 66.096 220.235 66.582 ;
     RECT  220.199 67.986 220.235 68.274 ;
     RECT  220.235 49.446 220.307 49.464 ;
     RECT  220.207 52.56 220.307 52.578 ;
     RECT  220.235 58.158 220.307 58.176 ;
     RECT  220.235 61.056 220.307 61.074 ;
     RECT  220.235 66.564 220.307 66.582 ;
     RECT  220.235 68.256 220.307 68.274 ;
    LAYER M3 ;
     RECT  108.288 0.139 108.306 0.187 ;
     RECT  109.764 0.091 110.214 0.187 ;
     RECT  108.288 0.187 108.558 0.475 ;
     RECT  109.764 0.187 110.394 0.475 ;
     RECT  107.136 0.091 107.154 0.523 ;
     RECT  108.288 0.475 110.394 0.523 ;
     RECT  107.136 0.523 110.394 0.571 ;
     RECT  112.104 1.147 112.122 1.771 ;
     RECT  112.896 1.723 112.914 1.771 ;
     RECT  111.168 1.723 111.186 1.876 ;
     RECT  112.104 1.771 112.914 1.876 ;
     RECT  106.596 0.571 110.394 1.957 ;
     RECT  114.552 1.921 114.57 1.993 ;
     RECT  114.516 1.993 114.57 2.029 ;
     RECT  115.488 1.957 115.506 2.029 ;
     RECT  111.168 1.876 113.238 2.065 ;
     RECT  114.516 2.029 115.506 2.065 ;
     RECT  106.416 1.957 110.394 2.101 ;
     RECT  111.168 2.065 115.506 2.101 ;
     RECT  106.416 2.101 115.506 2.143 ;
     RECT  106.416 2.143 115.905 2.255 ;
     RECT  2.415 2.143 2.505 2.413 ;
     RECT  7.815 2.143 7.905 2.413 ;
     RECT  13.215 2.143 13.305 2.413 ;
     RECT  18.615 2.143 18.705 2.413 ;
     RECT  24.015 2.143 24.105 2.413 ;
     RECT  29.415 2.143 29.505 2.413 ;
     RECT  34.815 2.143 34.905 2.413 ;
     RECT  40.215 2.143 40.305 2.413 ;
     RECT  45.615 2.143 45.705 2.413 ;
     RECT  51.015 2.143 51.105 2.413 ;
     RECT  56.415 2.143 56.505 2.413 ;
     RECT  61.815 2.143 61.905 2.413 ;
     RECT  67.215 2.143 67.305 2.413 ;
     RECT  72.615 2.143 72.705 2.413 ;
     RECT  78.015 2.143 78.105 2.413 ;
     RECT  83.415 2.143 83.505 2.413 ;
     RECT  88.815 2.143 88.905 2.413 ;
     RECT  94.215 2.143 94.305 2.413 ;
     RECT  99.615 2.143 99.705 2.413 ;
     RECT  105.015 2.143 105.105 2.413 ;
     RECT  106.848 2.255 115.905 2.413 ;
     RECT  121.215 2.143 121.305 2.413 ;
     RECT  126.615 2.143 126.705 2.413 ;
     RECT  132.015 2.143 132.105 2.413 ;
     RECT  137.415 2.143 137.505 2.413 ;
     RECT  142.815 2.143 142.905 2.413 ;
     RECT  148.215 2.143 148.305 2.413 ;
     RECT  153.615 2.143 153.705 2.413 ;
     RECT  159.015 2.143 159.105 2.413 ;
     RECT  164.415 2.143 164.505 2.413 ;
     RECT  169.815 2.143 169.905 2.413 ;
     RECT  175.215 2.143 175.305 2.413 ;
     RECT  180.615 2.143 180.705 2.413 ;
     RECT  186.015 2.143 186.105 2.413 ;
     RECT  191.415 2.143 191.505 2.413 ;
     RECT  196.815 2.143 196.905 2.413 ;
     RECT  202.215 2.143 202.305 2.413 ;
     RECT  207.615 2.143 207.705 2.413 ;
     RECT  213.015 2.143 213.105 2.413 ;
     RECT  84.816 2.731 84.834 2.861 ;
     RECT  106.848 2.413 116.097 3.001 ;
     RECT  45.615 2.413 45.897 3.073 ;
     RECT  196.815 2.413 197.097 3.073 ;
     RECT  61.815 2.413 62.097 3.109 ;
     RECT  106.236 3.001 116.097 3.109 ;
     RECT  105.015 2.413 105.297 3.145 ;
     RECT  106.236 3.109 116.658 3.145 ;
     RECT  102.6 2.911 102.618 3.181 ;
     RECT  191.415 2.413 191.697 3.271 ;
     RECT  91.62 3.307 91.638 3.389 ;
     RECT  105.015 3.145 116.658 3.451 ;
     RECT  117.72 3.415 117.738 3.451 ;
     RECT  132.015 2.413 132.297 3.451 ;
     RECT  142.815 2.413 143.097 3.451 ;
     RECT  105.015 3.451 116.874 3.541 ;
     RECT  146.844 3.451 146.862 3.541 ;
     RECT  194.4 3.001 194.418 3.541 ;
     RECT  146.772 3.541 146.862 3.568 ;
     RECT  182.556 3.451 182.574 3.568 ;
     RECT  182.556 3.568 182.61 3.569 ;
     RECT  178.488 3.451 178.506 3.577 ;
     RECT  133.344 3.064 133.362 3.613 ;
     RECT  146.772 3.568 146.898 3.613 ;
     RECT  142.56 3.451 143.097 3.643 ;
     RECT  142.524 3.643 143.097 3.683 ;
     RECT  178.488 3.577 178.578 3.685 ;
     RECT  182.592 3.569 182.61 3.685 ;
     RECT  193.5 3.577 193.518 3.685 ;
     RECT  146.772 3.613 146.97 3.713 ;
     RECT  178.416 3.685 178.578 3.713 ;
     RECT  182.592 3.685 182.682 3.713 ;
     RECT  102.6 3.181 102.762 3.721 ;
     RECT  104.904 3.541 116.874 3.721 ;
     RECT  132.015 3.451 132.606 3.721 ;
     RECT  133.344 3.613 133.65 3.721 ;
     RECT  45.615 3.073 46.206 3.749 ;
     RECT  142.56 3.683 143.097 3.749 ;
     RECT  146.952 3.713 146.97 3.749 ;
     RECT  132.015 3.721 133.65 3.811 ;
     RECT  118.584 3.451 118.602 3.839 ;
     RECT  122.256 3.451 122.274 3.839 ;
     RECT  132.015 3.811 133.974 3.875 ;
     RECT  178.416 3.713 178.434 3.875 ;
     RECT  182.664 3.713 182.682 3.875 ;
     RECT  18.615 2.413 18.897 3.883 ;
     RECT  103.824 3.721 116.874 3.883 ;
     RECT  117.72 3.451 117.846 3.883 ;
     RECT  130.536 3.721 130.554 3.883 ;
     RECT  102.6 3.721 103.086 3.955 ;
     RECT  103.824 3.883 117.846 3.955 ;
     RECT  83.415 2.413 83.697 3.979 ;
     RECT  130.536 3.883 130.626 3.983 ;
     RECT  133.056 3.875 133.974 3.983 ;
     RECT  52.236 3.451 52.254 3.991 ;
     RECT  52.992 3.067 53.01 3.991 ;
     RECT  159.015 2.413 159.297 3.991 ;
     RECT  126.615 2.413 126.897 4.081 ;
     RECT  130.752 3.991 130.77 4.081 ;
     RECT  195.552 3.811 195.57 4.081 ;
     RECT  196.38 3.073 197.097 4.081 ;
     RECT  163.476 3.991 163.494 4.109 ;
     RECT  126.615 4.081 127.566 4.117 ;
     RECT  156.204 3.919 156.222 4.117 ;
     RECT  162.612 3.979 162.63 4.117 ;
     RECT  78.015 2.413 78.297 4.123 ;
     RECT  83.415 3.979 83.79 4.123 ;
     RECT  130.752 4.081 131.022 4.145 ;
     RECT  193.14 3.685 193.518 4.153 ;
     RECT  194.328 3.541 194.418 4.153 ;
     RECT  162.504 4.117 162.63 4.157 ;
     RECT  21.06 3.577 21.078 4.189 ;
     RECT  69.552 3.643 69.57 4.225 ;
     RECT  102.6 3.955 117.846 4.225 ;
     RECT  69.552 4.225 69.75 4.253 ;
     RECT  78.015 4.123 78.678 4.253 ;
     RECT  126.54 4.117 127.638 4.253 ;
     RECT  61.092 3.109 62.097 4.261 ;
     RECT  99.615 2.413 99.897 4.261 ;
     RECT  66.132 3.883 66.15 4.289 ;
     RECT  155.664 4.117 156.222 4.289 ;
     RECT  158.472 3.991 159.297 4.289 ;
     RECT  163.512 4.189 163.53 4.289 ;
     RECT  99.615 4.261 100.458 4.351 ;
     RECT  18.324 3.883 18.897 4.379 ;
     RECT  152.568 4.225 152.586 4.415 ;
     RECT  167.328 4.123 167.346 4.415 ;
     RECT  19.908 3.721 19.926 4.423 ;
     RECT  21.06 4.189 21.114 4.423 ;
     RECT  195.552 4.081 197.097 4.423 ;
     RECT  133.236 3.983 133.974 4.451 ;
     RECT  101.808 4.117 101.826 4.459 ;
     RECT  126.615 4.253 127.566 4.487 ;
     RECT  120.024 4.459 120.042 4.495 ;
     RECT  211.824 4.459 211.842 4.495 ;
     RECT  120.024 4.495 120.366 4.523 ;
     RECT  156.204 4.289 156.222 4.523 ;
     RECT  101.736 4.459 101.826 4.531 ;
     RECT  120.276 4.523 120.366 4.531 ;
     RECT  121.215 2.413 121.497 4.531 ;
     RECT  17.424 4.495 17.442 4.541 ;
     RECT  102.6 4.225 117.882 4.559 ;
     RECT  99.615 4.351 100.674 4.621 ;
     RECT  101.52 4.531 101.826 4.621 ;
     RECT  198.576 4.351 198.594 4.621 ;
     RECT  98.604 4.411 98.622 4.693 ;
     RECT  164.415 2.413 164.697 4.729 ;
     RECT  47.304 4.171 47.322 4.733 ;
     RECT  138.564 4.693 138.582 4.765 ;
     RECT  167.652 4.621 167.994 4.781 ;
     RECT  24.015 2.413 24.297 4.792 ;
     RECT  34.815 2.413 35.097 4.792 ;
     RECT  138.564 4.765 138.798 4.792 ;
     RECT  140.256 4.693 140.274 4.793 ;
     RECT  166.464 4.621 166.482 4.793 ;
     RECT  167.976 4.781 167.994 4.793 ;
     RECT  142.815 3.749 143.097 4.801 ;
     RECT  23.904 4.792 24.297 4.829 ;
     RECT  34.704 4.792 35.097 4.829 ;
     RECT  42.768 4.699 42.786 4.829 ;
     RECT  157.068 4.657 157.086 4.829 ;
     RECT  163.944 4.729 164.697 4.829 ;
     RECT  82.692 4.123 83.898 4.891 ;
     RECT  152.712 4.531 152.73 4.891 ;
     RECT  153.615 2.413 153.897 4.891 ;
     RECT  175.215 2.413 175.497 4.891 ;
     RECT  186.015 2.413 186.297 4.891 ;
     RECT  21.96 2.767 21.978 4.927 ;
     RECT  153.615 4.891 154.026 4.928 ;
     RECT  164.304 4.829 164.697 4.928 ;
     RECT  175.104 4.891 175.497 4.928 ;
     RECT  185.904 4.891 186.297 4.928 ;
     RECT  138.528 4.792 138.798 4.955 ;
     RECT  142.815 4.801 143.37 4.955 ;
     RECT  99.615 4.621 101.862 4.987 ;
     RECT  102.6 4.559 117.414 4.987 ;
     RECT  82.692 4.891 84.15 4.991 ;
     RECT  182.412 4.891 182.43 4.991 ;
     RECT  98.604 4.693 98.694 4.999 ;
     RECT  99.615 4.987 117.414 4.999 ;
     RECT  94.215 2.413 94.497 5.161 ;
     RECT  142.815 4.955 143.298 5.161 ;
     RECT  22.788 4.693 22.806 5.165 ;
     RECT  52.236 3.991 53.01 5.233 ;
     RECT  122.868 5.197 122.886 5.233 ;
     RECT  97.596 5.224 97.614 5.261 ;
     RECT  142.344 5.161 143.298 5.261 ;
     RECT  45.615 3.749 45.954 5.269 ;
     RECT  126.615 4.487 126.897 5.269 ;
     RECT  98.604 4.999 117.414 5.305 ;
     RECT  118.62 5.197 118.638 5.332 ;
     RECT  122.616 5.233 122.886 5.332 ;
     RECT  118.584 5.332 118.638 5.333 ;
     RECT  94.215 5.161 94.698 5.341 ;
     RECT  119.52 5.305 119.538 5.341 ;
     RECT  120.276 4.531 121.497 5.341 ;
     RECT  148.215 2.413 148.497 5.341 ;
     RECT  126.54 5.269 126.897 5.369 ;
     RECT  21.96 4.927 22.05 5.431 ;
     RECT  81.936 4.747 81.954 5.431 ;
     RECT  82.692 4.991 84.078 5.431 ;
     RECT  97.74 5.305 117.414 5.431 ;
     RECT  124.524 5.197 124.542 5.431 ;
     RECT  128.484 5.341 128.502 5.431 ;
     RECT  193.14 4.153 194.418 5.431 ;
     RECT  195.552 4.423 197.73 5.431 ;
     RECT  122.616 5.332 122.922 5.459 ;
     RECT  97.74 5.431 117.846 5.467 ;
     RECT  118.584 5.333 118.602 5.467 ;
     RECT  119.52 5.341 121.497 5.467 ;
     RECT  131.004 4.145 131.022 5.495 ;
     RECT  72.615 2.413 72.897 5.503 ;
     RECT  94.215 5.341 94.734 5.503 ;
     RECT  81.936 5.431 84.078 5.531 ;
     RECT  134.532 5.431 134.838 5.531 ;
     RECT  154.872 5.341 154.89 5.531 ;
     RECT  124.524 5.431 124.974 5.539 ;
     RECT  127.98 5.431 128.502 5.563 ;
     RECT  72.615 5.503 72.918 5.575 ;
     RECT  72.54 5.575 72.918 5.602 ;
     RECT  94.215 5.503 94.77 5.603 ;
     RECT  127.836 5.563 128.502 5.603 ;
     RECT  133.236 4.451 133.65 5.603 ;
     RECT  69.732 4.253 69.75 5.611 ;
     RECT  72.54 5.602 72.954 5.611 ;
     RECT  119.448 5.467 121.497 5.611 ;
     RECT  198.576 4.621 199.278 5.611 ;
     RECT  134.748 5.531 134.766 5.639 ;
     RECT  140.184 4.801 140.202 5.639 ;
     RECT  72.468 5.611 72.954 5.729 ;
     RECT  88.815 2.413 89.097 5.737 ;
     RECT  54.936 3.955 54.954 5.773 ;
     RECT  122.616 5.459 122.814 5.773 ;
     RECT  138.78 4.955 138.798 5.773 ;
     RECT  60.444 4.261 62.097 5.845 ;
     RECT  119.376 5.611 121.497 5.845 ;
     RECT  122.22 5.773 122.814 5.845 ;
     RECT  137.415 2.413 137.697 5.845 ;
     RECT  138.528 5.773 138.798 5.845 ;
     RECT  141.372 5.431 141.39 5.909 ;
     RECT  45.615 5.269 46.206 5.971 ;
     RECT  88.164 5.737 89.097 5.971 ;
     RECT  97.74 5.467 118.602 5.999 ;
     RECT  45.324 5.971 46.206 6.035 ;
     RECT  137.415 5.845 138.798 6.035 ;
     RECT  19.908 4.423 21.114 6.043 ;
     RECT  21.96 5.431 22.626 6.043 ;
     RECT  88.056 5.971 89.097 6.071 ;
     RECT  173.844 5.233 173.862 6.071 ;
     RECT  72.54 5.729 72.897 6.107 ;
     RECT  198.576 5.611 199.926 6.151 ;
     RECT  130.68 6.151 130.698 6.269 ;
     RECT  90.324 4.621 90.342 6.277 ;
     RECT  142.632 5.261 143.298 6.277 ;
     RECT  144.72 6.241 144.738 6.277 ;
     RECT  167.004 6.151 167.022 6.277 ;
     RECT  170.928 6.151 170.946 6.277 ;
     RECT  49.608 4.657 49.626 6.313 ;
     RECT  51.015 2.413 51.297 6.313 ;
     RECT  126.615 5.369 126.897 6.313 ;
     RECT  149.364 6.079 149.382 6.313 ;
     RECT  153.615 4.928 153.897 6.313 ;
     RECT  174.204 6.115 174.33 6.313 ;
     RECT  175.215 4.928 175.497 6.313 ;
     RECT  49.608 6.313 51.297 6.349 ;
     RECT  90.324 6.277 90.702 6.349 ;
     RECT  95.724 6.277 95.742 6.349 ;
     RECT  132.015 3.875 132.297 6.349 ;
     RECT  167.004 6.277 167.058 6.349 ;
     RECT  170.928 6.277 171.018 6.349 ;
     RECT  193.14 5.431 197.73 6.349 ;
     RECT  152.712 4.891 152.802 6.377 ;
     RECT  54.936 5.773 55.314 6.385 ;
     RECT  127.98 5.603 128.502 6.385 ;
     RECT  130.5 6.313 130.59 6.385 ;
     RECT  149.364 6.313 149.418 6.385 ;
     RECT  159.015 4.289 159.297 6.385 ;
     RECT  164.415 4.928 164.697 6.385 ;
     RECT  169.815 2.413 170.097 6.385 ;
     RECT  170.928 6.349 171.09 6.385 ;
     RECT  174.204 6.313 175.497 6.385 ;
     RECT  208.908 5.881 208.926 6.385 ;
     RECT  94.215 5.603 94.734 6.413 ;
     RECT  166.464 6.349 167.058 6.413 ;
     RECT  90.324 6.349 90.774 6.421 ;
     RECT  95.616 6.349 95.742 6.421 ;
     RECT  149.364 6.385 149.742 6.449 ;
     RECT  95.544 6.421 95.742 6.511 ;
     RECT  90.324 6.421 90.81 6.512 ;
     RECT  130.428 6.385 130.59 6.539 ;
     RECT  166.464 6.413 166.482 6.539 ;
     RECT  82.692 5.531 84.078 6.547 ;
     RECT  126.54 6.313 126.897 6.547 ;
     RECT  144.468 6.277 144.81 6.547 ;
     RECT  149.4 6.449 149.742 6.547 ;
     RECT  158.508 6.385 159.297 6.547 ;
     RECT  94.215 6.413 94.662 6.575 ;
     RECT  131.904 6.349 132.297 6.575 ;
     RECT  54.72 6.385 55.314 6.583 ;
     RECT  56.415 2.413 56.697 6.583 ;
     RECT  69.228 5.611 69.75 6.583 ;
     RECT  54.72 6.583 56.697 6.611 ;
     RECT  85.932 5.881 85.95 6.619 ;
     RECT  86.688 6.583 86.706 6.619 ;
     RECT  87.804 6.547 87.822 6.619 ;
     RECT  92.34 6.583 92.358 6.619 ;
     RECT  94.215 6.575 94.497 6.619 ;
     RECT  49.428 6.349 51.297 6.647 ;
     RECT  90.324 6.512 90.774 6.647 ;
     RECT  95.4 6.511 95.742 6.647 ;
     RECT  60.444 5.845 62.154 6.655 ;
     RECT  62.928 4.729 62.946 6.655 ;
     RECT  82.692 6.547 84.33 6.655 ;
     RECT  119.376 5.845 122.814 6.655 ;
     RECT  123.948 5.539 124.974 6.655 ;
     RECT  126.324 6.547 126.897 6.655 ;
     RECT  162.072 6.547 162.09 6.655 ;
     RECT  163.764 6.385 164.697 6.655 ;
     RECT  82.692 6.655 84.906 6.683 ;
     RECT  87.768 6.619 87.822 6.683 ;
     RECT  174.204 6.385 175.698 6.683 ;
     RECT  85.932 6.619 86.706 6.691 ;
     RECT  119.376 6.655 124.974 6.691 ;
     RECT  146.484 6.547 146.502 6.691 ;
     RECT  160.344 6.619 160.362 6.691 ;
     RECT  162.072 6.655 162.306 6.691 ;
     RECT  149.4 6.547 150.246 6.719 ;
     RECT  158.472 6.547 159.297 6.719 ;
     RECT  174.204 6.683 175.626 6.719 ;
     RECT  45.324 6.035 45.954 6.781 ;
     RECT  69.228 6.583 70.146 6.781 ;
     RECT  167.796 6.691 167.814 6.781 ;
     RECT  52.236 5.233 53.622 6.809 ;
     RECT  87.768 6.683 87.786 6.809 ;
     RECT  90.324 6.647 90.738 6.809 ;
     RECT  141.66 6.277 141.678 6.809 ;
     RECT  153.615 6.313 154.494 6.809 ;
     RECT  160.344 6.691 160.614 6.809 ;
     RECT  167.544 6.781 167.814 6.809 ;
     RECT  169.815 6.385 171.126 6.809 ;
     RECT  190.404 6.583 190.422 6.809 ;
     RECT  18.615 4.379 18.897 6.817 ;
     RECT  19.908 6.043 22.626 6.817 ;
     RECT  95.436 6.647 95.742 6.817 ;
     RECT  162.072 6.691 162.45 6.817 ;
     RECT  90.324 6.809 90.666 6.845 ;
     RECT  95.436 6.817 96.426 6.845 ;
     RECT  146.484 6.691 146.574 6.845 ;
     RECT  149.4 6.719 150.174 6.845 ;
     RECT  160.344 6.809 160.362 6.845 ;
     RECT  174.204 6.719 175.554 6.845 ;
     RECT  158.544 6.719 159.297 6.853 ;
     RECT  161.82 6.817 162.45 6.853 ;
     RECT  149.652 6.845 150.174 6.854 ;
     RECT  74.484 6.853 74.502 6.859 ;
     RECT  97.74 5.999 118.458 6.859 ;
     RECT  55.692 6.611 56.697 6.881 ;
     RECT  92.088 6.619 92.358 6.889 ;
     RECT  97.74 6.859 118.602 6.889 ;
     RECT  163.44 6.655 164.697 6.889 ;
     RECT  78.015 4.253 78.297 6.907 ;
     RECT  161.748 6.853 162.45 6.907 ;
     RECT  163.296 6.889 164.697 6.907 ;
     RECT  67.215 2.413 67.497 6.952 ;
     RECT  146.484 6.845 146.502 6.953 ;
     RECT  149.652 6.854 150.138 6.953 ;
     RECT  167.544 6.809 167.562 6.953 ;
     RECT  60.444 6.655 62.946 6.955 ;
     RECT  142.56 6.277 143.298 6.955 ;
     RECT  74.484 6.859 74.682 6.961 ;
     RECT  130.428 6.539 130.554 6.989 ;
     RECT  158.544 6.853 159.75 6.989 ;
     RECT  67.104 6.952 67.497 7.051 ;
     RECT  142.2 6.955 143.298 7.115 ;
     RECT  159.015 6.989 159.75 7.115 ;
     RECT  78.015 6.907 78.93 7.123 ;
     RECT  161.748 6.907 164.697 7.123 ;
     RECT  84.888 6.683 84.906 7.133 ;
     RECT  45.108 6.781 45.954 7.159 ;
     RECT  60.444 6.955 63.45 7.181 ;
     RECT  81.936 5.531 81.954 7.195 ;
     RECT  82.692 6.683 84.15 7.195 ;
     RECT  147.6 5.341 148.497 7.195 ;
     RECT  198.576 6.151 199.962 7.195 ;
     RECT  58.788 6.691 58.806 7.223 ;
     RECT  66.672 7.051 67.497 7.223 ;
     RECT  161.676 7.123 164.697 7.223 ;
     RECT  77.76 7.123 78.93 7.259 ;
     RECT  159.015 7.115 159.678 7.259 ;
     RECT  161.748 7.223 163.458 7.259 ;
     RECT  125.964 6.655 126.897 7.357 ;
     RECT  127.908 6.385 128.502 7.357 ;
     RECT  95.436 6.845 95.454 7.385 ;
     RECT  161.748 7.259 162.306 7.385 ;
     RECT  79.776 6.619 79.794 7.393 ;
     RECT  74.376 6.961 74.682 7.429 ;
     RECT  93.744 6.619 94.497 7.483 ;
     RECT  93.744 7.483 94.626 7.501 ;
     RECT  202.215 2.413 202.497 7.501 ;
     RECT  125.964 7.357 128.502 7.591 ;
     RECT  174.24 6.845 175.497 7.591 ;
     RECT  97.74 6.889 118.638 7.627 ;
     RECT  119.376 6.691 125.01 7.627 ;
     RECT  92.088 6.889 92.754 7.675 ;
     RECT  93.744 7.501 94.698 7.675 ;
     RECT  97.74 7.627 125.01 7.699 ;
     RECT  125.82 7.591 128.502 7.699 ;
     RECT  207.615 2.413 207.897 7.699 ;
     RECT  208.908 6.385 209.61 7.699 ;
     RECT  92.088 7.675 94.698 7.727 ;
     RECT  149.652 6.953 149.994 7.727 ;
     RECT  71.136 5.035 71.154 7.735 ;
     RECT  202.215 7.501 203.202 7.735 ;
     RECT  88.815 6.071 89.097 7.771 ;
     RECT  164.304 7.223 164.697 7.799 ;
     RECT  211.824 4.495 212.238 7.867 ;
     RECT  213.015 2.413 213.297 7.867 ;
     RECT  55.764 6.881 56.697 7.897 ;
     RECT  88.632 7.771 89.097 7.897 ;
     RECT  159.015 7.259 159.57 7.925 ;
     RECT  130.428 6.989 130.446 7.933 ;
     RECT  18.615 6.817 22.626 7.969 ;
     RECT  153.615 6.809 153.897 7.969 ;
     RECT  202.215 7.735 203.382 8.005 ;
     RECT  92.484 7.727 94.698 8.041 ;
     RECT  192.636 6.349 197.73 8.131 ;
     RECT  198.576 7.195 200.286 8.131 ;
     RECT  92.484 8.041 94.734 8.159 ;
     RECT  68.652 6.781 70.146 8.167 ;
     RECT  76.968 4.123 76.986 8.167 ;
     RECT  77.796 7.259 78.93 8.167 ;
     RECT  202.215 8.005 203.886 8.167 ;
     RECT  97.74 7.699 128.502 8.189 ;
     RECT  76.14 7.771 76.158 8.203 ;
     RECT  192.636 8.131 200.286 8.203 ;
     RECT  192.636 8.203 200.466 8.231 ;
     RECT  125.82 8.189 128.502 8.267 ;
     RECT  79.776 7.393 80.406 8.275 ;
     RECT  90.324 6.845 90.342 8.275 ;
     RECT  130.428 7.933 130.806 8.299 ;
     RECT  79.776 8.275 81.054 8.303 ;
     RECT  155.952 8.041 155.97 8.303 ;
     RECT  132.015 6.575 132.297 8.311 ;
     RECT  44.46 7.159 45.954 8.339 ;
     RECT  80.748 8.303 81.054 8.429 ;
     RECT  92.484 8.159 94.662 8.429 ;
     RECT  130.428 8.299 130.95 8.429 ;
     RECT  90.324 8.275 90.666 8.437 ;
     RECT  132.015 8.311 132.57 8.437 ;
     RECT  157.176 7.195 157.194 8.437 ;
     RECT  153.615 7.969 154.566 8.465 ;
     RECT  17.676 7.501 17.694 8.473 ;
     RECT  18.615 7.969 22.734 8.473 ;
     RECT  68.652 8.167 70.254 8.501 ;
     RECT  132.015 8.437 132.642 8.509 ;
     RECT  90.324 8.437 90.738 8.537 ;
     RECT  153.615 8.465 154.494 8.537 ;
     RECT  47.484 6.007 47.502 8.581 ;
     RECT  48.456 5.341 48.474 8.581 ;
     RECT  88.38 7.897 89.097 8.671 ;
     RECT  201.672 8.167 203.886 8.671 ;
     RECT  71.136 7.735 71.37 8.707 ;
     RECT  81.936 7.195 84.15 8.707 ;
     RECT  88.056 8.671 89.097 8.707 ;
     RECT  157.176 8.437 157.698 8.707 ;
     RECT  201.672 8.671 204.102 8.707 ;
     RECT  17.676 8.473 22.734 8.743 ;
     RECT  156.528 8.707 157.698 8.765 ;
     RECT  161.82 7.385 162.306 8.771 ;
     RECT  55.764 7.897 56.826 8.779 ;
     RECT  85.932 6.691 86.922 8.779 ;
     RECT  87.876 8.707 89.097 8.779 ;
     RECT  157.176 8.765 157.698 8.779 ;
     RECT  93.24 8.429 94.662 8.807 ;
     RECT  14.76 7.159 14.778 8.815 ;
     RECT  85.752 8.779 86.922 8.815 ;
     RECT  87.804 8.779 89.097 8.815 ;
     RECT  76.968 8.167 78.93 8.843 ;
     RECT  67.215 7.223 67.497 8.851 ;
     RECT  25.092 8.005 25.11 8.879 ;
     RECT  70.596 8.707 71.37 9.005 ;
     RECT  81.936 8.707 84.258 9.041 ;
     RECT  85.752 8.815 89.097 9.049 ;
     RECT  159.015 7.925 159.297 9.085 ;
     RECT  14.364 8.815 14.778 9.115 ;
     RECT  70.848 9.005 71.37 9.149 ;
     RECT  70.92 9.149 71.37 9.239 ;
     RECT  97.74 8.189 125.01 9.283 ;
     RECT  174.24 7.591 175.59 9.311 ;
     RECT  55.764 8.779 57.042 9.319 ;
     RECT  149.976 7.727 149.994 9.319 ;
     RECT  60.444 7.181 62.097 9.355 ;
     RECT  62.928 7.181 63.45 9.355 ;
     RECT  157.176 8.779 157.914 9.383 ;
     RECT  14.364 9.115 15.066 9.391 ;
     RECT  17.676 8.743 22.842 9.391 ;
     RECT  207.615 7.699 209.61 9.391 ;
     RECT  125.964 8.267 128.502 9.517 ;
     RECT  129.636 6.817 129.654 9.517 ;
     RECT  159.015 9.085 159.39 9.517 ;
     RECT  135.936 7.393 135.954 9.553 ;
     RECT  132.015 8.509 132.822 9.581 ;
     RECT  52.236 6.809 53.01 9.589 ;
     RECT  201.636 8.707 204.102 9.589 ;
     RECT  149.904 9.319 149.994 9.617 ;
     RECT  68.652 8.501 69.75 9.661 ;
     RECT  72.615 6.107 72.897 9.661 ;
     RECT  198.576 8.231 200.466 9.661 ;
     RECT  55.764 9.319 57.546 9.689 ;
     RECT  97.164 9.283 125.01 9.689 ;
     RECT  159.015 9.517 160.002 9.689 ;
     RECT  166.356 8.581 166.374 9.689 ;
     RECT  93.24 8.807 94.497 9.751 ;
     RECT  96.408 6.845 96.426 9.751 ;
     RECT  97.164 9.689 114.786 9.751 ;
     RECT  90.324 8.537 90.342 9.787 ;
     RECT  96.336 9.751 114.786 9.787 ;
     RECT  115.524 9.689 125.01 9.815 ;
     RECT  66.708 8.851 67.497 9.859 ;
     RECT  96.264 9.787 114.786 9.887 ;
     RECT  90.324 9.787 90.702 9.895 ;
     RECT  93.24 9.751 94.662 9.895 ;
     RECT  96.264 9.887 112.374 9.895 ;
     RECT  115.815 9.815 125.01 9.917 ;
     RECT  96.192 9.895 112.374 9.923 ;
     RECT  14.364 9.391 15.138 9.931 ;
     RECT  93.24 9.895 95.094 9.931 ;
     RECT  134.748 7.699 134.766 9.931 ;
     RECT  149.904 9.617 149.922 9.959 ;
     RECT  133.632 5.603 133.65 10.021 ;
     RECT  134.424 9.931 134.766 10.021 ;
     RECT  90.324 9.895 90.774 10.049 ;
     RECT  50.292 6.647 51.297 10.057 ;
     RECT  201.636 9.589 204.354 10.057 ;
     RECT  201.456 10.057 204.354 10.075 ;
     RECT  96.192 9.923 111.942 10.109 ;
     RECT  115.815 9.917 116.622 10.121 ;
     RECT  133.632 10.021 134.766 10.121 ;
     RECT  169.815 6.809 170.694 10.157 ;
     RECT  60.444 9.355 63.45 10.165 ;
     RECT  68.436 9.661 69.75 10.165 ;
     RECT  72.615 9.661 72.99 10.165 ;
     RECT  133.632 10.121 133.65 10.165 ;
     RECT  137.415 6.035 137.697 10.165 ;
     RECT  138.456 6.035 138.798 10.165 ;
     RECT  58.788 9.787 58.806 10.193 ;
     RECT  66.6 9.859 67.497 10.193 ;
     RECT  60.444 10.165 64.098 10.229 ;
     RECT  66.672 10.193 67.497 10.229 ;
     RECT  97.164 10.109 111.942 10.229 ;
     RECT  93.24 9.931 95.346 10.253 ;
     RECT  91.512 8.977 91.53 10.291 ;
     RECT  92.484 8.429 92.502 10.291 ;
     RECT  205.632 6.139 205.65 10.291 ;
     RECT  97.164 10.229 111.51 10.355 ;
     RECT  76.068 8.203 76.158 10.399 ;
     RECT  76.968 8.843 76.986 10.399 ;
     RECT  177.696 10.327 177.714 10.399 ;
     RECT  125.964 9.517 129.654 10.463 ;
     RECT  24.015 4.829 24.297 10.471 ;
     RECT  72.54 10.165 72.99 10.471 ;
     RECT  191.415 3.271 191.898 10.471 ;
     RECT  192.636 8.231 197.73 10.471 ;
     RECT  177.588 10.399 177.822 10.499 ;
     RECT  102.276 10.355 111.51 10.589 ;
     RECT  191.415 10.471 197.73 10.589 ;
     RECT  59.58 6.925 59.598 10.597 ;
     RECT  16.02 8.203 16.038 10.633 ;
     RECT  16.776 9.625 16.794 10.633 ;
     RECT  68.436 10.165 69.822 10.633 ;
     RECT  71.136 9.239 71.37 10.633 ;
     RECT  174.672 9.311 175.59 10.637 ;
     RECT  171.072 10.561 171.09 10.697 ;
     RECT  113.22 9.887 114.786 10.705 ;
     RECT  59.436 10.597 59.598 10.741 ;
     RECT  102.276 10.589 108.486 10.769 ;
     RECT  54.72 6.611 54.954 10.859 ;
     RECT  76.068 10.399 76.986 10.867 ;
     RECT  80.748 8.429 80.766 10.867 ;
     RECT  198.576 9.661 200.502 10.867 ;
     RECT  201.456 10.075 204.642 10.867 ;
     RECT  150.552 10.831 150.57 10.967 ;
     RECT  151.776 10.831 151.794 10.967 ;
     RECT  57.528 9.689 57.546 10.975 ;
     RECT  50.292 10.057 51.354 11.011 ;
     RECT  52.236 9.589 53.046 11.011 ;
     RECT  80.748 10.867 81.162 11.011 ;
     RECT  81.936 9.041 84.078 11.011 ;
     RECT  85.356 9.049 89.097 11.101 ;
     RECT  115.815 10.121 116.55 11.101 ;
     RECT  115.704 11.101 116.55 11.128 ;
     RECT  117.54 9.917 125.01 11.128 ;
     RECT  50.292 11.011 53.046 11.129 ;
     RECT  80.748 11.011 84.078 11.165 ;
     RECT  115.704 11.128 125.01 11.165 ;
     RECT  85.356 11.101 89.514 11.173 ;
     RECT  91.512 10.291 92.502 11.173 ;
     RECT  144.468 6.547 145.134 11.201 ;
     RECT  183.24 7.321 183.258 11.209 ;
     RECT  41.58 10.129 41.598 11.213 ;
     RECT  91.224 11.173 92.502 11.227 ;
     RECT  93.24 10.253 95.094 11.227 ;
     RECT  55.764 9.689 56.697 11.245 ;
     RECT  57.528 10.975 58.158 11.245 ;
     RECT  117.504 11.165 125.01 11.245 ;
     RECT  125.964 10.463 129.114 11.245 ;
     RECT  55.764 11.245 58.158 11.281 ;
     RECT  112.572 10.705 114.786 11.281 ;
     RECT  164.415 7.799 164.697 11.281 ;
     RECT  142.344 7.115 143.298 11.365 ;
     RECT  144.036 11.281 144.126 11.365 ;
     RECT  55.764 11.281 58.698 11.399 ;
     RECT  91.224 11.227 95.094 11.399 ;
     RECT  178.416 11.209 178.434 11.399 ;
     RECT  183.24 11.209 183.366 11.399 ;
     RECT  142.344 11.365 144.126 11.405 ;
     RECT  144.108 11.405 144.126 11.408 ;
     RECT  198.576 10.867 204.642 11.453 ;
     RECT  93.24 11.399 95.094 11.479 ;
     RECT  96.192 10.109 96.426 11.479 ;
     RECT  102.348 10.769 108.486 11.515 ;
     RECT  109.26 10.589 111.51 11.515 ;
     RECT  112.536 11.281 114.786 11.515 ;
     RECT  74.376 7.429 74.934 11.551 ;
     RECT  75.744 10.867 76.986 11.551 ;
     RECT  81.936 11.165 84.078 11.551 ;
     RECT  84.924 11.173 89.514 11.551 ;
     RECT  135.648 9.553 135.954 11.579 ;
     RECT  54.828 10.859 54.954 11.641 ;
     RECT  117.504 11.245 129.114 11.693 ;
     RECT  74.376 11.551 76.986 11.705 ;
     RECT  115.704 11.165 116.406 11.705 ;
     RECT  91.224 11.399 92.502 11.741 ;
     RECT  59.436 10.741 59.706 11.749 ;
     RECT  60.444 10.229 62.946 11.749 ;
     RECT  64.08 10.229 64.098 11.749 ;
     RECT  65.196 3.649 65.214 11.749 ;
     RECT  55.764 11.399 58.158 11.777 ;
     RECT  117.54 11.693 129.114 11.777 ;
     RECT  42.408 11.173 42.426 11.785 ;
     RECT  159.015 9.689 159.39 11.813 ;
     RECT  163.152 7.259 163.458 11.813 ;
     RECT  102.348 11.515 114.786 11.821 ;
     RECT  115.704 11.705 116.334 11.821 ;
     RECT  177.876 11.749 177.894 11.849 ;
     RECT  17.532 9.391 22.842 11.911 ;
     RECT  24.015 10.471 24.786 11.911 ;
     RECT  90.324 10.049 90.342 11.911 ;
     RECT  59.436 11.749 62.946 11.947 ;
     RECT  90.324 11.911 90.738 11.947 ;
     RECT  102.348 11.821 116.334 11.975 ;
     RECT  124.308 11.777 129.114 11.983 ;
     RECT  132.015 9.581 132.297 11.983 ;
     RECT  133.056 10.165 133.65 11.983 ;
     RECT  124.308 11.983 129.402 12.011 ;
     RECT  210.96 10.633 210.978 12.055 ;
     RECT  211.824 7.867 213.297 12.055 ;
     RECT  59.436 11.947 63.126 12.083 ;
     RECT  60.444 12.083 63.126 12.091 ;
     RECT  64.08 11.749 65.214 12.091 ;
     RECT  135.936 11.579 135.954 12.119 ;
     RECT  40.215 2.413 40.497 12.181 ;
     RECT  153.615 8.537 153.897 12.187 ;
     RECT  192.636 10.589 197.73 12.187 ;
     RECT  198.576 11.453 204.39 12.187 ;
     RECT  91.476 11.741 92.502 12.217 ;
     RECT  93.24 11.479 96.426 12.217 ;
     RECT  151.632 12.181 151.65 12.221 ;
     RECT  90.252 11.947 90.738 12.245 ;
     RECT  81.936 11.551 89.514 12.253 ;
     RECT  90.252 12.245 90.342 12.253 ;
     RECT  38.772 12.181 38.79 12.281 ;
     RECT  40.215 12.181 41.094 12.281 ;
     RECT  152.712 6.377 152.73 12.283 ;
     RECT  153.615 12.187 154.494 12.283 ;
     RECT  152.712 12.283 154.494 12.289 ;
     RECT  134.748 10.121 134.766 12.317 ;
     RECT  152.712 12.289 155.07 12.317 ;
     RECT  152.712 12.317 153.897 12.353 ;
     RECT  16.02 10.633 16.794 12.361 ;
     RECT  17.532 11.911 24.786 12.361 ;
     RECT  29.415 2.413 29.697 12.361 ;
     RECT  42.408 11.785 42.822 12.361 ;
     RECT  40.215 12.281 41.022 12.389 ;
     RECT  70.812 10.633 71.37 12.451 ;
     RECT  79.776 8.303 80.01 12.451 ;
     RECT  80.748 11.165 80.766 12.451 ;
     RECT  42.408 12.361 42.894 12.479 ;
     RECT  91.476 12.217 96.426 12.479 ;
     RECT  67.215 10.229 67.497 12.487 ;
     RECT  68.436 10.633 70.074 12.487 ;
     RECT  93.24 12.479 96.426 12.487 ;
     RECT  97.164 10.355 101.25 12.487 ;
     RECT  42.408 12.479 42.822 12.515 ;
     RECT  57.636 11.777 58.158 12.551 ;
     RECT  117.54 11.777 123.39 12.631 ;
     RECT  42.408 12.515 42.426 12.721 ;
     RECT  47.484 8.581 48.474 12.757 ;
     RECT  192.636 12.187 204.39 12.757 ;
     RECT  117.144 12.631 123.39 12.785 ;
     RECT  132.015 11.983 133.65 12.821 ;
     RECT  130.428 8.429 130.806 12.857 ;
     RECT  13.215 2.413 13.497 12.865 ;
     RECT  14.364 9.931 15.174 12.865 ;
     RECT  45.108 8.339 45.954 12.865 ;
     RECT  46.764 12.757 48.474 12.865 ;
     RECT  49.428 6.647 49.446 12.865 ;
     RECT  29.415 12.361 30.222 12.893 ;
     RECT  45.108 12.865 49.446 12.893 ;
     RECT  59.436 12.083 59.598 12.901 ;
     RECT  190.656 10.327 190.674 12.901 ;
     RECT  50.292 11.129 53.01 12.929 ;
     RECT  132.015 12.821 132.822 12.929 ;
     RECT  42.12 12.721 42.426 13.019 ;
     RECT  128.412 12.011 129.402 13.055 ;
     RECT  140.652 6.007 140.67 13.091 ;
     RECT  129.384 13.055 129.402 13.199 ;
     RECT  144.864 11.201 145.134 13.361 ;
     RECT  27.936 12.757 27.954 13.397 ;
     RECT  77.796 8.843 78.93 13.397 ;
     RECT  117.756 12.785 123.39 13.397 ;
     RECT  115.815 11.975 116.334 13.405 ;
     RECT  34.815 4.829 35.097 13.432 ;
     RECT  67.215 12.487 70.074 13.432 ;
     RECT  128.412 13.055 128.43 13.433 ;
     RECT  163.44 11.813 163.458 13.469 ;
     RECT  132.015 12.929 132.297 13.531 ;
     RECT  153.615 12.353 153.897 13.531 ;
     RECT  164.415 11.281 165.006 13.531 ;
     RECT  186.015 4.928 186.297 13.531 ;
     RECT  207.396 9.391 209.61 13.567 ;
     RECT  131.904 13.531 132.297 13.568 ;
     RECT  153.504 13.531 153.897 13.568 ;
     RECT  164.304 13.531 165.006 13.568 ;
     RECT  185.904 13.531 186.297 13.568 ;
     RECT  161.82 8.771 162.162 13.595 ;
     RECT  120.6 13.397 123.39 13.603 ;
     RECT  124.524 12.011 127.386 13.603 ;
     RECT  91.476 12.479 92.502 13.661 ;
     RECT  120.6 13.603 127.386 13.661 ;
     RECT  155.052 12.317 155.07 13.739 ;
     RECT  180.615 2.413 180.897 13.801 ;
     RECT  190.404 12.901 190.674 13.829 ;
     RECT  55.764 11.777 56.697 13.837 ;
     RECT  179.928 13.801 180.897 13.901 ;
     RECT  42.408 13.019 42.426 13.909 ;
     RECT  159.015 11.813 159.297 13.909 ;
     RECT  67.104 13.432 70.074 13.937 ;
     RECT  207.216 13.567 209.61 13.945 ;
     RECT  124.524 13.661 127.386 13.949 ;
     RECT  55.764 13.837 56.754 13.973 ;
     RECT  124.524 13.949 127.134 13.973 ;
     RECT  207.216 13.945 209.79 13.981 ;
     RECT  210.96 12.055 213.297 13.981 ;
     RECT  30.852 13.909 30.87 14.009 ;
     RECT  34.704 13.432 35.097 14.009 ;
     RECT  42.408 13.909 42.822 14.009 ;
     RECT  67.104 13.937 67.497 14.009 ;
     RECT  77.904 13.397 78.93 14.009 ;
     RECT  133.632 12.821 133.65 14.009 ;
     RECT  142.344 11.405 143.298 14.009 ;
     RECT  158.472 13.909 159.75 14.009 ;
     RECT  192.636 12.757 204.642 14.009 ;
     RECT  58.716 12.901 59.598 14.099 ;
     RECT  70.812 12.451 71.514 14.107 ;
     RECT  72.54 10.471 73.53 14.107 ;
     RECT  16.02 12.361 24.786 14.135 ;
     RECT  81.936 12.253 90.342 14.189 ;
     RECT  137.415 10.165 138.798 14.369 ;
     RECT  190.44 13.829 190.674 14.377 ;
     RECT  191.415 10.589 191.898 14.377 ;
     RECT  190.44 14.377 191.898 14.477 ;
     RECT  93.24 12.487 101.25 14.513 ;
     RECT  16.02 14.135 24.297 14.521 ;
     RECT  79.776 12.451 80.766 14.549 ;
     RECT  45.108 12.893 46.422 14.611 ;
     RECT  47.484 12.893 49.446 14.611 ;
     RECT  117.756 13.397 119.754 14.611 ;
     RECT  120.6 13.661 123.39 14.611 ;
     RECT  15.912 14.521 24.297 14.639 ;
     RECT  97.74 14.513 101.25 14.639 ;
     RECT  207.216 13.981 213.297 14.647 ;
     RECT  102.348 11.975 114.786 14.669 ;
     RECT  117.756 14.611 123.39 14.669 ;
     RECT  58.716 14.099 58.734 14.683 ;
     RECT  82.692 14.189 90.342 14.683 ;
     RECT  138.78 14.369 138.798 14.711 ;
     RECT  13.215 12.865 15.174 14.719 ;
     RECT  15.912 14.639 22.77 14.719 ;
     RECT  120.6 14.669 123.39 14.747 ;
     RECT  117.756 14.669 119.754 14.765 ;
     RECT  82.692 14.683 90.666 14.783 ;
     RECT  55.764 13.973 56.697 14.791 ;
     RECT  188.352 6.511 188.37 14.881 ;
     RECT  126.615 13.973 127.134 14.945 ;
     RECT  78.015 14.009 78.93 14.953 ;
     RECT  164.415 13.568 165.006 14.981 ;
     RECT  190.44 14.477 190.674 15.017 ;
     RECT  75.744 11.705 76.986 15.089 ;
     RECT  97.74 14.639 101.214 15.089 ;
     RECT  34.815 14.009 35.097 15.151 ;
     RECT  67.215 14.009 67.497 15.151 ;
     RECT  132.015 13.568 132.297 15.151 ;
     RECT  142.815 14.009 143.298 15.151 ;
     RECT  153.615 13.568 153.897 15.151 ;
     RECT  164.415 14.981 164.697 15.151 ;
     RECT  186.015 13.568 186.297 15.151 ;
     RECT  77.76 14.953 78.93 15.179 ;
     RECT  52.236 12.929 53.01 15.187 ;
     RECT  81.936 14.189 81.954 15.187 ;
     RECT  27.36 14.143 27.378 15.215 ;
     RECT  192.636 14.009 204.39 15.223 ;
     RECT  26.352 5.071 26.37 15.295 ;
     RECT  45.108 14.611 49.446 15.331 ;
     RECT  50.292 12.929 51.297 15.331 ;
     RECT  188.352 14.881 188.442 15.331 ;
     RECT  142.704 15.151 143.298 15.421 ;
     RECT  185.904 15.151 186.297 15.421 ;
     RECT  190.656 15.017 190.674 15.421 ;
     RECT  191.415 14.477 191.898 15.421 ;
     RECT  70.812 14.107 73.53 15.457 ;
     RECT  74.376 11.705 74.934 15.457 ;
     RECT  26.352 15.295 26.802 15.485 ;
     RECT  117.756 14.765 117.774 15.499 ;
     RECT  142.524 15.421 143.73 15.557 ;
     RECT  117.756 15.499 117.99 15.581 ;
     RECT  188.352 15.331 188.586 15.593 ;
     RECT  174.672 10.637 175.497 15.629 ;
     RECT  185.904 15.421 186.498 15.629 ;
     RECT  190.656 15.421 191.898 15.629 ;
     RECT  120.6 14.747 122.022 15.691 ;
     RECT  122.796 14.747 123.39 15.691 ;
     RECT  192.636 15.223 204.534 15.691 ;
     RECT  205.596 10.291 205.65 15.691 ;
     RECT  117.972 15.581 117.99 15.719 ;
     RECT  185.904 15.629 186.426 15.719 ;
     RECT  34.704 15.151 35.097 15.725 ;
     RECT  58.608 14.683 58.734 15.727 ;
     RECT  59.58 14.099 59.598 15.727 ;
     RECT  23.904 14.639 24.297 15.728 ;
     RECT  82.692 14.783 90.378 15.728 ;
     RECT  131.904 15.151 132.297 15.728 ;
     RECT  142.704 15.557 143.658 15.728 ;
     RECT  153.504 15.151 153.897 15.728 ;
     RECT  164.304 15.151 164.697 15.728 ;
     RECT  175.104 15.629 175.497 15.728 ;
     RECT  185.904 15.719 186.297 15.728 ;
     RECT  124.524 13.973 125.694 15.773 ;
     RECT  114.084 14.669 114.786 15.799 ;
     RECT  115.815 13.405 116.586 15.799 ;
     RECT  93.24 14.513 96.606 15.821 ;
     RECT  120.6 15.691 123.39 15.821 ;
     RECT  68.436 13.937 70.074 15.827 ;
     RECT  70.812 15.457 74.934 15.863 ;
     RECT  81.504 15.187 81.954 15.863 ;
     RECT  67.104 15.151 67.497 15.871 ;
     RECT  58.608 15.727 59.598 15.899 ;
     RECT  147.276 7.195 148.497 15.899 ;
     RECT  66.816 15.871 67.497 15.961 ;
     RECT  76.068 15.089 76.986 15.997 ;
     RECT  192.636 15.691 205.65 16.069 ;
     RECT  81.936 15.863 81.954 16.075 ;
     RECT  82.692 15.728 88.074 16.075 ;
     RECT  13.215 14.719 22.77 16.105 ;
     RECT  114.084 15.799 116.586 16.231 ;
     RECT  191.415 15.629 191.898 16.259 ;
     RECT  60.444 12.091 65.214 16.267 ;
     RECT  66.132 15.961 67.497 16.267 ;
     RECT  190.656 15.629 190.674 16.267 ;
     RECT  207.216 14.647 213.606 16.267 ;
     RECT  13.176 16.105 22.77 16.301 ;
     RECT  102.348 14.669 113.238 16.301 ;
     RECT  114.048 16.231 116.586 16.331 ;
     RECT  118.728 14.765 119.754 16.367 ;
     RECT  190.44 16.267 190.674 16.375 ;
     RECT  81.936 16.075 88.074 16.397 ;
     RECT  161.82 13.595 161.838 16.403 ;
     RECT  188.568 15.593 188.586 16.673 ;
     RECT  152.712 12.353 152.73 16.709 ;
     RECT  192.636 16.069 206.262 16.807 ;
     RECT  122.796 15.821 123.39 16.829 ;
     RECT  122.796 16.829 122.814 16.871 ;
     RECT  57.636 12.551 57.762 16.877 ;
     RECT  91.476 13.661 92.394 16.877 ;
     RECT  144.864 13.361 144.882 16.943 ;
     RECT  183.24 11.399 183.258 16.943 ;
     RECT  68.436 15.827 69.822 16.979 ;
     RECT  120.6 15.821 122.022 16.979 ;
     RECT  192.528 16.807 206.262 17.069 ;
     RECT  137.415 14.369 138.006 17.105 ;
     RECT  24.015 15.728 24.297 17.311 ;
     RECT  34.815 15.725 35.097 17.311 ;
     RECT  85.68 16.397 88.074 17.311 ;
     RECT  88.815 15.728 90.378 17.311 ;
     RECT  132.015 15.728 132.297 17.311 ;
     RECT  142.815 15.728 143.658 17.311 ;
     RECT  153.615 15.728 153.897 17.311 ;
     RECT  164.415 15.728 164.697 17.311 ;
     RECT  175.215 15.728 175.497 17.311 ;
     RECT  186.015 15.728 186.297 17.311 ;
     RECT  85.68 17.311 90.378 17.347 ;
     RECT  23.904 17.311 24.297 17.357 ;
     RECT  34.704 17.311 35.097 17.357 ;
     RECT  85.5 17.347 90.378 17.357 ;
     RECT  93.816 15.821 96.606 17.357 ;
     RECT  97.74 15.089 100.17 17.357 ;
     RECT  153.504 17.311 153.897 17.357 ;
     RECT  164.304 17.311 164.697 17.357 ;
     RECT  175.104 17.311 175.497 17.357 ;
     RECT  185.904 17.311 186.297 17.357 ;
     RECT  146.484 17.221 146.502 17.419 ;
     RECT  147.276 15.899 147.294 17.419 ;
     RECT  149.94 17.221 149.958 17.419 ;
     RECT  60.444 16.267 67.497 17.447 ;
     RECT  149.868 17.419 149.958 17.447 ;
     RECT  119.484 16.367 119.754 17.453 ;
     RECT  70.812 15.863 71.514 17.455 ;
     RECT  72.54 15.863 74.934 17.455 ;
     RECT  192.924 17.069 206.262 17.455 ;
     RECT  207.036 16.267 213.606 17.455 ;
     RECT  130.788 12.857 130.806 17.483 ;
     RECT  160.164 16.879 160.182 17.483 ;
     RECT  149.868 17.447 149.886 17.491 ;
     RECT  93.816 17.357 95.598 17.501 ;
     RECT  91.476 16.877 92.07 17.519 ;
     RECT  146.484 17.419 147.294 17.519 ;
     RECT  118.728 16.367 118.746 17.581 ;
     RECT  119.484 17.453 119.502 17.581 ;
     RECT  149.796 17.491 149.886 17.581 ;
     RECT  97.776 17.357 100.17 17.609 ;
     RECT  169.815 10.157 170.097 17.617 ;
     RECT  118.728 17.581 119.502 17.681 ;
     RECT  142.704 17.311 143.658 17.753 ;
     RECT  118.728 17.681 118.746 17.761 ;
     RECT  151.632 17.077 151.65 17.789 ;
     RECT  148.215 15.899 148.497 17.851 ;
     RECT  82.692 16.397 84.762 17.879 ;
     RECT  118.584 17.761 118.746 17.879 ;
     RECT  131.904 17.311 132.297 17.888 ;
     RECT  142.704 17.753 143.097 17.888 ;
     RECT  124.524 15.773 124.974 17.923 ;
     RECT  118.728 17.879 118.746 17.933 ;
     RECT  149.724 17.581 149.886 17.933 ;
     RECT  121.068 16.979 122.022 17.951 ;
     RECT  75.888 15.997 76.986 17.959 ;
     RECT  77.76 15.179 78.297 17.959 ;
     RECT  25.056 15.835 25.074 17.981 ;
     RECT  88.815 17.357 90.378 17.981 ;
     RECT  148.104 17.851 148.497 17.981 ;
     RECT  149.724 17.933 149.742 17.981 ;
     RECT  64.98 17.447 67.497 17.987 ;
     RECT  52.236 15.187 53.622 17.995 ;
     RECT  54.396 11.641 54.954 17.995 ;
     RECT  102.852 16.301 113.238 17.995 ;
     RECT  114.084 16.331 116.586 17.995 ;
     RECT  167.976 8.437 167.994 18.023 ;
     RECT  157.176 9.383 157.194 18.059 ;
     RECT  146.484 17.519 146.502 18.173 ;
     RECT  124.524 17.923 125.262 18.185 ;
     RECT  100.944 15.089 101.214 18.293 ;
     RECT  121.215 17.951 122.022 18.301 ;
     RECT  98.856 17.609 100.17 18.329 ;
     RECT  169.815 17.617 170.514 18.329 ;
     RECT  75.888 17.959 78.297 18.419 ;
     RECT  24.015 17.357 24.297 18.499 ;
     RECT  121.215 18.301 122.634 18.527 ;
     RECT  52.236 17.995 54.954 18.535 ;
     RECT  55.692 14.791 56.697 18.535 ;
     RECT  60.444 17.447 64.098 18.535 ;
     RECT  124.524 18.185 124.542 18.563 ;
     RECT  45.108 15.331 51.297 18.599 ;
     RECT  122.616 18.527 122.634 18.599 ;
     RECT  68.436 16.979 69.75 18.689 ;
     RECT  70.812 17.455 74.934 18.769 ;
     RECT  58.608 15.899 58.734 18.805 ;
     RECT  85.5 17.357 88.074 18.833 ;
     RECT  88.815 17.981 89.406 18.833 ;
     RECT  70.812 18.769 75.258 18.959 ;
     RECT  119.484 17.681 119.502 18.959 ;
     RECT  13.215 16.301 22.77 18.967 ;
     RECT  26.352 15.485 26.37 18.967 ;
     RECT  85.68 18.833 88.074 19.037 ;
     RECT  26.352 18.967 26.514 19.039 ;
     RECT  76.068 18.419 78.297 19.067 ;
     RECT  45.108 18.599 49.446 19.111 ;
     RECT  58.608 18.805 58.842 19.111 ;
     RECT  59.58 15.899 59.598 19.111 ;
     RECT  68.436 18.689 68.562 19.111 ;
     RECT  45 19.111 49.446 19.139 ;
     RECT  60.336 18.535 64.098 19.139 ;
     RECT  98.856 18.329 99.897 19.139 ;
     RECT  45 19.139 48.474 19.201 ;
     RECT  44.964 19.201 48.474 19.229 ;
     RECT  95.472 17.501 95.598 19.229 ;
     RECT  13.215 18.967 22.842 19.237 ;
     RECT  23.616 18.499 24.297 19.237 ;
     RECT  26.208 19.039 26.514 19.265 ;
     RECT  70.812 18.959 73.53 19.265 ;
     RECT  76.428 19.067 78.297 19.291 ;
     RECT  58.608 19.111 59.598 19.309 ;
     RECT  13.215 19.237 24.297 19.337 ;
     RECT  26.424 19.265 26.514 19.337 ;
     RECT  98.928 19.139 99.897 19.337 ;
     RECT  82.692 17.879 83.79 19.339 ;
     RECT  91.476 17.519 92.034 19.409 ;
     RECT  34.815 17.357 35.097 19.471 ;
     RECT  70.812 19.265 71.37 19.499 ;
     RECT  191.415 16.259 191.79 19.499 ;
     RECT  69.408 18.689 69.75 19.579 ;
     RECT  70.812 19.499 71.298 19.579 ;
     RECT  118.656 18.733 118.674 19.579 ;
     RECT  102.852 17.995 116.586 19.607 ;
     RECT  190.404 16.375 190.674 19.607 ;
     RECT  117.684 19.243 117.702 19.615 ;
     RECT  69.408 19.579 71.298 19.616 ;
     RECT  104.832 19.607 116.586 19.627 ;
     RECT  117.36 19.615 117.702 19.627 ;
     RECT  81.936 16.397 81.954 19.651 ;
     RECT  82.692 19.339 83.826 19.651 ;
     RECT  118.512 19.579 118.674 19.651 ;
     RECT  99.576 19.337 99.897 19.661 ;
     RECT  74.376 18.959 75.258 19.679 ;
     RECT  104.832 19.627 117.702 19.741 ;
     RECT  118.476 19.651 118.674 19.741 ;
     RECT  72.216 19.265 73.53 19.769 ;
     RECT  97.776 17.609 97.794 19.769 ;
     RECT  104.832 19.741 118.674 19.769 ;
     RECT  5.184 19.741 5.202 19.849 ;
     RECT  52.236 18.535 56.697 19.877 ;
     RECT  117.684 19.769 118.674 19.877 ;
     RECT  6.732 19.003 6.75 19.885 ;
     RECT  13.215 19.337 22.842 19.912 ;
     RECT  76.428 19.291 78.894 19.912 ;
     RECT  88.056 19.037 88.074 19.913 ;
     RECT  76.176 19.912 78.894 19.921 ;
     RECT  79.776 14.549 80.01 19.921 ;
     RECT  80.748 14.549 80.766 19.921 ;
     RECT  54.72 19.877 56.697 19.949 ;
     RECT  68.4 19.111 68.562 20.147 ;
     RECT  11.232 19.309 11.25 20.155 ;
     RECT  64.008 19.139 64.098 20.155 ;
     RECT  64.98 17.987 65.862 20.155 ;
     RECT  40.215 12.389 40.497 20.191 ;
     RECT  58.392 19.309 59.598 20.191 ;
     RECT  60.336 19.139 63.126 20.191 ;
     RECT  102.852 19.607 104.022 20.191 ;
     RECT  42.408 14.009 42.426 20.281 ;
     RECT  44.964 19.229 46.422 20.281 ;
     RECT  47.484 19.229 48.474 20.281 ;
     RECT  58.392 20.191 63.126 20.309 ;
     RECT  64.008 20.155 65.862 20.309 ;
     RECT  13.104 19.912 22.842 20.317 ;
     RECT  23.616 19.337 24.297 20.317 ;
     RECT  85.68 19.037 86.922 20.317 ;
     RECT  87.768 19.921 87.786 20.317 ;
     RECT  40.215 20.191 41.166 20.345 ;
     RECT  74.376 19.679 74.934 20.347 ;
     RECT  81.936 19.651 83.826 20.347 ;
     RECT  84.744 17.879 84.762 20.347 ;
     RECT  11.232 20.155 11.358 20.353 ;
     RECT  102.672 20.191 104.022 20.353 ;
     RECT  7.815 2.413 8.097 20.461 ;
     RECT  192.924 17.455 213.606 20.477 ;
     RECT  10.836 20.353 11.358 20.489 ;
     RECT  13.104 20.317 24.297 20.489 ;
     RECT  30.78 20.317 30.798 20.489 ;
     RECT  34.704 19.471 35.097 20.489 ;
     RECT  102.6 20.353 104.022 20.551 ;
     RECT  104.832 19.769 116.874 20.551 ;
     RECT  52.236 19.877 53.802 20.579 ;
     RECT  74.052 20.347 74.934 20.579 ;
     RECT  75.816 19.921 78.894 20.579 ;
     RECT  102.6 20.551 116.874 20.579 ;
     RECT  42.408 20.281 42.786 20.587 ;
     RECT  50.292 18.599 51.297 20.587 ;
     RECT  118.656 19.877 118.674 20.587 ;
     RECT  145.944 20.191 145.962 20.623 ;
     RECT  70.488 19.616 71.298 20.651 ;
     RECT  85.68 20.317 87.786 20.651 ;
     RECT  88.815 18.833 89.334 20.659 ;
     RECT  50.292 20.587 51.318 20.669 ;
     RECT  44.964 20.281 48.474 20.683 ;
     RECT  118.656 20.587 118.746 20.687 ;
     RECT  77.76 20.579 78.894 20.695 ;
     RECT  79.776 19.921 80.766 20.695 ;
     RECT  52.344 20.579 53.802 20.731 ;
     RECT  54.792 19.949 56.697 20.731 ;
     RECT  66.816 17.987 67.497 20.731 ;
     RECT  69.408 19.616 69.75 20.731 ;
     RECT  70.488 20.651 71.154 20.731 ;
     RECT  88.815 20.659 89.406 20.731 ;
     RECT  90.36 17.981 90.378 20.731 ;
     RECT  106.128 20.579 116.874 20.731 ;
     RECT  175.215 17.357 175.497 20.731 ;
     RECT  44.784 20.683 48.474 20.779 ;
     RECT  72.216 19.769 72.897 20.821 ;
     RECT  77.76 20.695 80.766 20.821 ;
     RECT  177.408 20.731 177.426 20.821 ;
     RECT  177.336 20.821 177.426 20.848 ;
     RECT  44.712 20.779 48.474 20.849 ;
     RECT  60.336 20.309 63.126 20.849 ;
     RECT  69.408 20.731 71.154 20.849 ;
     RECT  75.816 20.579 76.986 20.849 ;
     RECT  77.76 20.821 81.162 20.849 ;
     RECT  81.936 20.347 84.762 20.849 ;
     RECT  103.752 20.579 105.354 20.849 ;
     RECT  106.128 20.731 116.91 20.849 ;
     RECT  174.492 20.731 175.497 20.849 ;
     RECT  42.408 20.587 42.822 20.857 ;
     RECT  79.632 20.849 81.162 20.861 ;
     RECT  177.336 20.848 177.462 20.861 ;
     RECT  106.236 20.849 116.91 20.885 ;
     RECT  88.815 20.731 90.378 20.929 ;
     RECT  92.34 20.875 92.358 20.929 ;
     RECT  112.752 20.885 116.91 20.929 ;
     RECT  117.684 19.877 117.702 20.929 ;
     RECT  69.552 20.849 71.154 20.957 ;
     RECT  75.816 20.849 76.122 20.957 ;
     RECT  92.34 20.929 93.006 20.957 ;
     RECT  103.824 20.849 105.354 20.993 ;
     RECT  174.42 20.857 174.438 20.993 ;
     RECT  177.444 20.861 177.462 20.993 ;
     RECT  74.376 20.579 74.934 21.001 ;
     RECT  118.548 20.731 118.566 21.001 ;
     RECT  79.632 20.861 81.018 21.029 ;
     RECT  92.628 20.957 93.006 21.029 ;
     RECT  104.868 20.993 105.354 21.029 ;
     RECT  112.752 20.929 117.702 21.029 ;
     RECT  118.476 21.001 118.566 21.029 ;
     RECT  50.292 20.669 51.297 21.067 ;
     RECT  95.508 19.229 95.598 21.091 ;
     RECT  99.615 19.661 99.897 21.091 ;
     RECT  71.892 20.821 72.897 21.115 ;
     RECT  145.944 20.623 145.998 21.115 ;
     RECT  148.215 17.981 148.497 21.115 ;
     RECT  42.408 20.857 42.858 21.119 ;
     RECT  44.964 20.849 47.646 21.119 ;
     RECT  60.768 20.849 63.126 21.119 ;
     RECT  70.488 20.957 71.154 21.119 ;
     RECT  106.236 20.885 111.834 21.119 ;
     RECT  74.376 21.001 75.042 21.127 ;
     RECT  75.816 20.957 75.834 21.127 ;
     RECT  81.936 20.849 83.934 21.127 ;
     RECT  85.68 20.651 85.698 21.127 ;
     RECT  71.892 21.115 72.99 21.155 ;
     RECT  49.428 19.139 49.446 21.163 ;
     RECT  50.22 21.067 51.297 21.163 ;
     RECT  96.588 17.357 96.606 21.163 ;
     RECT  98.964 21.091 99.897 21.163 ;
     RECT  102.6 20.579 102.87 21.191 ;
     RECT  68.544 20.147 68.562 21.199 ;
     RECT  112.752 21.029 116.874 21.227 ;
     RECT  58.392 20.309 59.598 21.235 ;
     RECT  88.815 20.929 90.666 21.235 ;
     RECT  91.476 19.409 91.494 21.235 ;
     RECT  98.676 21.163 99.897 21.235 ;
     RECT  52.344 20.731 56.697 21.245 ;
     RECT  145.944 21.115 146.61 21.245 ;
     RECT  149.472 21.115 149.49 21.245 ;
     RECT  88.815 21.235 91.494 21.263 ;
     RECT  96.588 21.163 97.218 21.263 ;
     RECT  102.6 21.191 102.69 21.263 ;
     RECT  48.42 20.849 48.474 21.271 ;
     RECT  49.428 21.163 51.297 21.271 ;
     RECT  64.008 20.309 64.098 21.271 ;
     RECT  64.98 20.309 65.862 21.271 ;
     RECT  96.588 21.263 96.642 21.271 ;
     RECT  98.316 21.235 99.897 21.271 ;
     RECT  48.42 21.271 51.297 21.299 ;
     RECT  114.12 21.227 116.874 21.299 ;
     RECT  112.752 21.227 113.238 21.341 ;
     RECT  50.544 21.299 51.297 21.347 ;
     RECT  66.708 20.731 67.497 21.347 ;
     RECT  71.892 21.155 72.897 21.347 ;
     RECT  98.244 21.271 99.897 21.347 ;
     RECT  104.868 21.029 105.297 21.347 ;
     RECT  121.215 18.527 121.497 21.347 ;
     RECT  126.615 14.945 126.897 21.347 ;
     RECT  132.015 17.888 132.297 21.347 ;
     RECT  137.415 17.105 137.697 21.347 ;
     RECT  142.815 17.888 143.097 21.347 ;
     RECT  147.924 21.115 148.497 21.347 ;
     RECT  153.615 17.357 153.897 21.347 ;
     RECT  159.015 14.009 159.297 21.347 ;
     RECT  164.415 17.357 164.697 21.347 ;
     RECT  169.815 18.329 170.097 21.347 ;
     RECT  175.215 20.849 175.497 21.347 ;
     RECT  180.615 13.901 180.897 21.347 ;
     RECT  186.015 17.357 186.297 21.347 ;
     RECT  191.415 19.499 191.697 21.347 ;
     RECT  13.215 20.489 24.297 21.361 ;
     RECT  29.415 12.893 29.697 21.361 ;
     RECT  34.815 20.489 35.097 21.361 ;
     RECT  40.215 20.345 40.497 21.361 ;
     RECT  121.215 21.347 121.305 21.361 ;
     RECT  45.504 21.119 45.954 21.389 ;
     RECT  50.544 21.347 51.21 21.389 ;
     RECT  52.344 21.245 53.622 21.389 ;
     RECT  54.72 21.245 56.697 21.389 ;
     RECT  57.636 16.877 57.654 21.389 ;
     RECT  58.392 21.235 59.922 21.389 ;
     RECT  61.344 21.119 63.126 21.389 ;
     RECT  64.008 21.271 65.862 21.389 ;
     RECT  68.292 21.199 68.562 21.389 ;
     RECT  70.488 21.119 71.082 21.389 ;
     RECT  74.376 21.127 75.834 21.389 ;
     RECT  76.968 20.849 76.986 21.389 ;
     RECT  79.776 21.029 81.018 21.389 ;
     RECT  88.815 21.263 89.55 21.389 ;
     RECT  103.932 20.993 103.95 21.389 ;
     RECT  106.236 21.119 111.726 21.389 ;
     RECT  112.752 21.341 113.13 21.389 ;
     RECT  115.164 21.299 116.874 21.389 ;
     RECT  117.684 21.029 117.702 21.389 ;
     RECT  122.22 21.163 122.238 21.389 ;
     RECT  140.688 21.163 141.354 21.389 ;
     RECT  147.924 21.347 148.374 21.389 ;
     RECT  54.72 21.389 55.17 21.425 ;
     RECT  59.256 21.389 59.922 21.425 ;
     RECT  93.816 17.501 94.497 21.425 ;
     RECT  95.508 21.091 95.634 21.425 ;
     RECT  102.672 21.263 102.69 21.425 ;
     RECT  46.728 21.119 47.646 21.437 ;
     RECT  69.552 20.957 69.57 21.437 ;
     RECT  107.676 21.389 109.134 21.437 ;
     RECT  145.944 21.245 146.502 21.437 ;
     RECT  192.924 20.477 193.014 21.437 ;
     RECT  75.564 21.389 75.654 21.461 ;
     RECT  74.376 21.389 74.682 21.469 ;
     RECT  112.752 21.389 112.842 21.485 ;
     RECT  145.944 21.437 146.394 21.485 ;
     RECT  42.768 21.119 42.858 21.497 ;
     RECT  50.616 21.389 51.21 21.497 ;
     RECT  70.56 21.389 71.082 21.497 ;
     RECT  74.196 21.469 74.682 21.497 ;
     RECT  95.508 21.425 95.598 21.497 ;
     RECT  106.236 21.389 106.65 21.497 ;
     RECT  109.944 21.389 111.726 21.497 ;
     RECT  114.12 21.299 114.39 21.497 ;
     RECT  50.724 21.497 51.21 21.533 ;
     RECT  54.72 21.425 54.882 21.533 ;
     RECT  56.052 21.389 56.697 21.533 ;
     RECT  61.344 21.389 62.802 21.533 ;
     RECT  88.815 21.389 89.406 21.533 ;
     RECT  90.288 21.263 91.494 21.533 ;
     RECT  115.164 21.389 115.905 21.533 ;
     RECT  9.504 19.111 9.522 21.541 ;
     RECT  29.415 21.361 29.754 21.541 ;
     RECT  34.815 21.361 35.154 21.541 ;
     RECT  40.215 21.361 40.554 21.541 ;
     RECT  56.304 21.533 56.697 21.541 ;
     RECT  66.708 21.347 67.41 21.541 ;
     RECT  68.292 21.389 68.31 21.541 ;
     RECT  74.196 21.497 74.214 21.541 ;
     RECT  77.76 20.849 78.822 21.541 ;
     RECT  86.508 20.651 87.786 21.541 ;
     RECT  88.815 21.533 88.905 21.541 ;
     RECT  90.396 21.533 91.494 21.541 ;
     RECT  94.215 21.425 94.497 21.541 ;
     RECT  96.552 21.271 96.642 21.541 ;
     RECT  98.244 21.347 99.705 21.541 ;
     RECT  13.215 21.361 24.354 21.569 ;
     RECT  26.784 21.361 26.802 21.569 ;
     RECT  29.304 21.541 29.754 21.569 ;
     RECT  30.78 21.361 30.798 21.569 ;
     RECT  34.704 21.541 35.154 21.569 ;
     RECT  38.772 21.361 38.79 21.569 ;
     RECT  40.104 21.541 40.554 21.569 ;
     RECT  44.136 21.235 44.226 21.569 ;
     RECT  46.764 21.437 47.646 21.569 ;
     RECT  61.344 21.533 62.118 21.569 ;
     RECT  64.08 21.389 64.746 21.569 ;
     RECT  68.22 21.541 68.31 21.569 ;
     RECT  70.704 21.497 71.082 21.569 ;
     RECT  74.124 21.541 74.214 21.569 ;
     RECT  75.636 21.461 75.654 21.569 ;
     RECT  81.756 21.127 83.934 21.569 ;
     RECT  86.508 21.541 88.905 21.569 ;
     RECT  97.704 21.541 99.705 21.569 ;
     RECT  108.828 21.437 109.134 21.569 ;
     RECT  112.752 21.485 112.77 21.569 ;
     RECT  13.215 21.569 24.21 21.581 ;
     RECT  29.304 21.569 29.61 21.581 ;
     RECT  34.704 21.569 35.01 21.581 ;
     RECT  40.104 21.569 40.41 21.581 ;
     RECT  45.504 21.389 45.81 21.581 ;
     RECT  50.796 21.533 51.21 21.581 ;
     RECT  56.304 21.541 57.006 21.581 ;
     RECT  61.344 21.569 62.01 21.581 ;
     RECT  66.492 21.541 67.41 21.581 ;
     RECT  71.892 21.347 72.81 21.581 ;
     RECT  79.848 21.389 81.018 21.581 ;
     RECT  13.215 21.581 24.105 21.617 ;
     RECT  29.415 21.581 29.505 21.617 ;
     RECT  34.815 21.581 34.905 21.617 ;
     RECT  40.215 21.581 40.305 21.617 ;
     RECT  45.615 21.581 45.81 21.617 ;
     RECT  50.796 21.581 51.105 21.617 ;
     RECT  56.415 21.581 57.006 21.617 ;
     RECT  61.344 21.581 61.905 21.617 ;
     RECT  66.492 21.581 67.305 21.617 ;
     RECT  71.892 21.581 72.705 21.617 ;
     RECT  77.4 21.541 78.822 21.617 ;
     RECT  81.756 21.569 83.862 21.617 ;
     RECT  87.696 21.569 88.905 21.617 ;
     RECT  94.215 21.541 95.022 21.617 ;
     RECT  99.615 21.569 99.705 21.617 ;
     RECT  104.868 21.347 105.105 21.617 ;
     RECT  115.308 21.533 115.905 21.617 ;
     RECT  121.104 21.361 121.305 21.617 ;
     RECT  126.615 21.347 126.705 21.617 ;
     RECT  132.015 21.347 132.105 21.617 ;
     RECT  137.415 21.347 137.505 21.617 ;
     RECT  142.815 21.347 142.905 21.617 ;
     RECT  148.215 21.389 148.374 21.617 ;
     RECT  153.615 21.347 153.705 21.617 ;
     RECT  159.015 21.347 159.105 21.617 ;
     RECT  164.415 21.347 164.505 21.617 ;
     RECT  169.815 21.347 169.905 21.617 ;
     RECT  175.215 21.347 175.305 21.617 ;
     RECT  180.615 21.347 180.705 21.617 ;
     RECT  186.015 21.347 186.105 21.617 ;
     RECT  191.415 21.347 191.505 21.617 ;
     RECT  194.076 20.477 213.606 21.617 ;
     RECT  81.756 21.617 82.854 21.629 ;
     RECT  46.872 21.569 47.646 21.659 ;
     RECT  50.796 21.617 50.886 21.659 ;
     RECT  54.72 21.533 54.81 21.659 ;
     RECT  81.756 21.629 82.782 21.659 ;
     RECT  87.696 21.617 88.758 21.659 ;
     RECT  90.396 21.541 91.674 21.659 ;
     RECT  96.336 21.541 96.642 21.659 ;
     RECT  115.308 21.617 115.506 21.659 ;
     RECT  45.792 21.617 45.81 21.677 ;
     RECT  47.628 21.659 47.646 21.677 ;
     RECT  116.82 21.389 116.874 21.731 ;
     RECT  108.828 21.569 108.846 21.767 ;
     RECT  116.856 21.731 116.874 21.803 ;
     RECT  7.815 20.461 8.514 21.901 ;
     RECT  79.848 21.581 80.982 21.917 ;
     RECT  59.256 21.425 59.886 21.929 ;
     RECT  71.064 21.569 71.082 21.965 ;
     RECT  81.756 21.659 82.746 21.965 ;
     RECT  97.704 21.569 98.838 21.965 ;
     RECT  98.316 21.965 98.838 22.001 ;
     RECT  98.316 22.001 98.586 22.013 ;
     RECT  109.98 21.497 111.726 22.013 ;
     RECT  58.284 21.541 58.302 22.037 ;
     RECT  94.356 21.617 95.022 22.037 ;
     RECT  7.56 21.901 8.514 22.045 ;
     RECT  83.844 21.617 83.862 22.061 ;
     RECT  192.924 21.437 192.942 22.061 ;
     RECT  13.215 21.617 23.346 22.072 ;
     RECT  106.236 21.497 106.254 22.073 ;
     RECT  13.104 22.072 23.346 22.109 ;
     RECT  52.344 21.389 52.362 22.109 ;
     RECT  104.868 21.617 104.886 22.109 ;
     RECT  71.892 21.617 71.91 22.157 ;
     RECT  48.42 21.299 49.626 22.205 ;
     RECT  44.136 21.569 44.154 22.301 ;
     RECT  194.076 21.617 196.362 22.301 ;
     RECT  82.728 21.965 82.746 22.349 ;
     RECT  197.136 21.617 213.606 22.349 ;
     RECT  110.988 22.013 111.726 22.379 ;
     RECT  197.208 22.349 213.606 22.397 ;
     RECT  48.42 22.205 48.438 22.469 ;
     RECT  84.672 20.849 84.69 22.493 ;
     RECT  107.676 21.437 107.73 22.493 ;
     RECT  148.356 21.617 148.374 22.505 ;
     RECT  66.492 21.617 66.51 22.541 ;
     RECT  78.588 21.617 78.822 22.541 ;
     RECT  85.644 21.127 85.698 22.541 ;
     RECT  110.988 22.379 111.006 22.541 ;
     RECT  121.104 21.617 121.122 22.577 ;
     RECT  145.944 21.485 145.998 22.577 ;
     RECT  79.848 21.917 79.866 22.589 ;
     RECT  145.98 22.577 145.998 22.589 ;
     RECT  59.256 21.929 59.274 22.613 ;
     RECT  114.12 21.497 114.138 22.613 ;
     RECT  94.356 22.037 94.374 22.637 ;
     RECT  194.076 22.301 194.742 22.637 ;
     RECT  109.98 22.013 109.998 22.649 ;
     RECT  90.396 21.659 90.558 22.685 ;
     RECT  74.124 21.569 74.142 22.733 ;
     RECT  115.308 21.659 115.326 22.775 ;
     RECT  118.476 21.029 118.494 22.811 ;
     RECT  195.876 22.301 196.362 22.829 ;
     RECT  86.508 21.569 86.922 23.009 ;
     RECT  7.56 22.045 8.766 23.161 ;
     RECT  9.504 21.541 10.026 23.161 ;
     RECT  13.215 22.109 23.346 23.76 ;
     RECT  49.608 22.205 49.626 23.76 ;
     RECT  53.604 21.389 53.622 23.76 ;
     RECT  56.988 21.617 57.006 23.76 ;
     RECT  61.344 21.617 61.362 23.76 ;
     RECT  64.08 21.569 64.674 23.76 ;
     RECT  68.22 21.569 68.238 23.76 ;
     RECT  77.4 21.617 77.418 23.76 ;
     RECT  78.588 22.541 78.606 23.76 ;
     RECT  81.756 21.965 81.774 23.76 ;
     RECT  85.68 22.541 85.698 23.76 ;
     RECT  86.508 23.009 86.526 23.76 ;
     RECT  88.092 21.659 88.758 23.76 ;
     RECT  90.54 22.685 90.558 23.76 ;
     RECT  91.656 21.659 91.674 23.76 ;
     RECT  92.628 21.029 92.646 23.76 ;
     RECT  93.456 21.541 93.474 23.76 ;
     RECT  98.568 22.013 98.586 23.76 ;
     RECT  100.944 18.293 100.962 23.76 ;
     RECT  107.712 22.493 107.73 23.76 ;
     RECT  190.656 19.607 190.674 23.76 ;
     RECT  194.724 22.637 194.742 23.76 ;
     RECT  196.344 22.829 196.362 23.76 ;
     RECT  197.244 22.397 213.606 23.76 ;
     RECT  13.215 23.76 213.606 24.232 ;
     RECT  2.415 2.413 2.697 24.511 ;
     RECT  2.415 24.511 2.79 24.557 ;
     RECT  11.124 20.489 11.358 24.781 ;
     RECT  13.104 24.232 213.606 24.809 ;
     RECT  10.836 24.781 11.358 24.899 ;
     RECT  13.215 24.809 213.606 26.491 ;
     RECT  13.104 26.491 213.606 26.528 ;
     RECT  13.215 26.528 213.606 27.337 ;
     RECT  11.124 24.899 11.358 27.643 ;
     RECT  12.564 27.337 213.606 27.643 ;
     RECT  7.56 23.161 10.026 27.751 ;
     RECT  11.124 27.643 213.606 27.751 ;
     RECT  7.56 27.751 213.606 27.875 ;
     RECT  12.42 27.875 213.606 27.941 ;
     RECT  12.924 27.941 213.606 28.211 ;
     RECT  13.104 28.211 213.606 28.409 ;
     RECT  13.215 28.409 213.606 29.933 ;
     RECT  13.215 29.933 197.838 30.763 ;
     RECT  198.576 29.933 213.606 30.763 ;
     RECT  13.215 30.763 213.606 31.373 ;
     RECT  199.152 31.373 213.606 31.757 ;
     RECT  199.152 31.757 199.314 31.853 ;
     RECT  200.052 31.757 213.606 32.141 ;
     RECT  200.052 32.141 200.142 32.237 ;
     RECT  200.088 32.237 200.142 32.621 ;
     RECT  200.124 32.621 200.142 32.813 ;
     RECT  13.215 31.373 198.378 33.163 ;
     RECT  199.26 31.853 199.314 33.163 ;
     RECT  13.215 33.163 199.314 33.739 ;
     RECT  13.215 33.739 199.998 33.931 ;
     RECT  13.215 33.931 200.07 34.123 ;
     RECT  200.916 32.141 213.606 34.123 ;
     RECT  6.3 19.885 6.75 35.167 ;
     RECT  6.3 35.167 6.786 35.267 ;
     RECT  12.24 38.101 12.258 40.837 ;
     RECT  3.996 19.273 4.014 42.025 ;
     RECT  4.968 19.849 5.202 42.025 ;
     RECT  3.996 42.025 5.202 42.061 ;
     RECT  6.3 35.267 6.75 42.061 ;
     RECT  3.996 42.061 6.75 42.331 ;
     RECT  3.96 42.331 6.75 42.421 ;
     RECT  7.56 27.875 11.358 42.421 ;
     RECT  3.96 42.421 11.358 42.667 ;
     RECT  13.215 34.123 213.606 42.701 ;
     RECT  2.415 24.557 2.697 42.727 ;
     RECT  2.415 42.727 3.006 42.799 ;
     RECT  3.78 42.667 11.358 42.799 ;
     RECT  13.215 42.701 21.114 42.893 ;
     RECT  2.415 42.799 11.358 43.375 ;
     RECT  0.108 43.105 0.126 43.537 ;
     RECT  0.108 43.537 0.198 43.805 ;
     RECT  2.412 43.375 11.358 43.807 ;
     RECT  0.108 43.805 0.162 44.213 ;
     RECT  13.215 42.893 21.078 44.299 ;
     RECT  22.212 42.701 213.606 44.299 ;
     RECT  13.215 44.299 213.606 44.519 ;
     RECT  1.728 43.807 11.358 44.765 ;
     RECT  13.215 44.519 21.186 44.915 ;
     RECT  0.108 44.213 0.126 45.019 ;
     RECT  12.24 40.837 12.294 45.193 ;
     RECT  13.215 44.915 21.078 45.193 ;
     RECT  0.108 45.019 0.558 45.293 ;
     RECT  12.24 45.193 21.078 45.805 ;
     RECT  22.248 44.519 213.606 45.805 ;
     RECT  0.108 45.293 0.342 45.917 ;
     RECT  0.108 45.917 0.234 46.103 ;
     RECT  2.304 44.765 11.358 46.309 ;
     RECT  12.24 45.805 213.606 46.309 ;
     RECT  2.304 46.309 213.606 46.345 ;
     RECT  0.144 46.103 0.234 46.493 ;
     RECT  2.268 46.345 213.606 46.643 ;
     RECT  2.268 46.643 21.726 46.777 ;
     RECT  0.216 46.493 0.234 46.795 ;
     RECT  0.216 46.795 0.486 46.885 ;
     RECT  0.216 46.885 0.558 46.925 ;
     RECT  1.764 46.777 21.726 47.047 ;
     RECT  1.728 47.047 21.726 47.309 ;
     RECT  22.5 46.643 213.606 47.371 ;
     RECT  0.216 46.925 0.234 47.611 ;
     RECT  1.728 47.309 21.366 47.837 ;
     RECT  217.584 47.857 217.602 48.001 ;
     RECT  0.144 47.611 0.234 48.091 ;
     RECT  0.144 48.091 0.342 48.187 ;
     RECT  0.108 48.187 0.342 48.221 ;
     RECT  217.584 48.001 217.818 48.271 ;
     RECT  2.268 47.837 21.366 48.331 ;
     RECT  22.248 47.371 213.606 48.331 ;
     RECT  217.584 48.271 218.25 48.397 ;
     RECT  0.108 48.221 0.126 48.425 ;
     RECT  216.54 48.361 216.738 48.433 ;
     RECT  217.548 48.397 218.25 48.433 ;
     RECT  2.268 48.331 213.606 48.695 ;
     RECT  215.676 48.433 215.694 48.703 ;
     RECT  215.64 48.703 215.694 48.901 ;
     RECT  216.54 48.433 218.25 48.901 ;
     RECT  219.456 48.541 219.474 49.009 ;
     RECT  2.268 48.695 21.762 49.037 ;
     RECT  1.152 47.899 1.17 49.099 ;
     RECT  0.144 49.099 0.162 49.147 ;
     RECT  1.152 49.099 1.206 49.147 ;
     RECT  0.144 49.147 1.206 49.207 ;
     RECT  2.268 49.037 21.69 49.207 ;
     RECT  215.64 48.901 218.25 49.279 ;
     RECT  215.64 49.279 218.286 49.351 ;
     RECT  0.144 49.207 21.69 49.513 ;
     RECT  220.284 49.441 220.302 49.513 ;
     RECT  0.108 49.513 21.69 49.577 ;
     RECT  22.5 48.695 213.606 49.621 ;
     RECT  22.5 49.621 213.966 49.783 ;
     RECT  214.848 49.351 218.286 49.783 ;
     RECT  219.024 49.009 219.474 49.783 ;
     RECT  1.188 49.577 21.69 49.891 ;
     RECT  22.5 49.783 219.474 49.891 ;
     RECT  0.108 49.577 0.126 50.045 ;
     RECT  1.188 49.891 219.474 50.189 ;
     RECT  1.188 50.189 217.926 50.279 ;
     RECT  1.188 50.279 217.89 50.491 ;
     RECT  0.432 50.491 217.89 50.585 ;
     RECT  0.432 50.585 0.558 50.717 ;
     RECT  218.88 50.189 219.474 51.061 ;
     RECT  220.212 49.513 220.302 51.061 ;
     RECT  0.54 50.717 0.558 51.233 ;
     RECT  218.88 51.061 220.302 51.307 ;
     RECT  1.584 50.585 217.89 51.355 ;
     RECT  1.152 51.355 217.89 51.359 ;
     RECT  218.844 51.307 220.302 51.431 ;
     RECT  1.152 51.359 217.782 51.773 ;
     RECT  0.108 51.739 0.162 52.213 ;
     RECT  1.152 51.773 1.386 52.213 ;
     RECT  2.268 51.773 217.782 52.213 ;
     RECT  218.88 51.431 220.302 52.363 ;
     RECT  0.108 52.213 1.386 52.445 ;
     RECT  1.152 52.445 1.386 52.583 ;
     RECT  218.844 52.363 220.302 52.583 ;
     RECT  2.268 52.213 217.854 52.619 ;
     RECT  218.844 52.583 220.23 52.781 ;
     RECT  2.304 52.619 217.854 52.861 ;
     RECT  1.152 52.583 1.17 53.563 ;
     RECT  2.304 52.861 217.89 53.563 ;
     RECT  0.108 52.445 0.342 53.591 ;
     RECT  218.88 52.781 220.23 53.611 ;
     RECT  1.152 53.563 217.89 53.635 ;
     RECT  0.144 53.591 0.342 53.837 ;
     RECT  1.152 53.635 218.034 53.905 ;
     RECT  0.54 53.905 218.034 54.103 ;
     RECT  218.844 53.611 220.23 54.103 ;
     RECT  0.54 54.103 220.23 54.221 ;
     RECT  0.54 54.221 217.854 54.473 ;
     RECT  1.368 54.473 217.854 54.635 ;
     RECT  0.54 54.473 0.558 54.715 ;
     RECT  1.368 54.635 217.71 55.325 ;
     RECT  2.304 55.325 217.71 55.525 ;
     RECT  0.108 54.715 0.558 55.709 ;
     RECT  2.304 55.525 217.854 55.717 ;
     RECT  218.88 54.221 220.23 55.717 ;
     RECT  2.304 55.717 220.23 55.757 ;
     RECT  1.368 55.325 1.386 56.093 ;
     RECT  218.844 55.757 220.23 56.219 ;
     RECT  2.304 55.757 217.854 56.491 ;
     RECT  218.844 56.219 219.546 56.491 ;
     RECT  0.108 55.709 0.162 56.633 ;
     RECT  2.304 56.491 219.546 56.731 ;
     RECT  2.268 56.731 219.546 56.831 ;
     RECT  219.42 56.831 219.546 57.001 ;
     RECT  219.42 57.001 219.582 57.073 ;
     RECT  2.268 56.831 218.286 57.173 ;
     RECT  219.42 57.073 219.618 57.173 ;
     RECT  219.456 57.173 219.618 57.197 ;
     RECT  0.144 56.633 0.162 57.245 ;
     RECT  1.152 56.443 1.17 57.403 ;
     RECT  2.304 57.173 218.286 57.581 ;
     RECT  1.152 57.403 1.206 57.685 ;
     RECT  219.492 57.197 219.618 57.739 ;
     RECT  219.492 57.739 220.158 57.835 ;
     RECT  2.304 57.581 21.474 57.983 ;
     RECT  219.492 57.835 220.23 58.153 ;
     RECT  0.324 57.685 1.206 58.171 ;
     RECT  219.492 58.153 220.302 58.315 ;
     RECT  219.42 58.315 220.302 58.411 ;
     RECT  219.384 58.411 220.302 58.451 ;
     RECT  22.248 57.581 218.286 58.487 ;
     RECT  0.108 58.171 1.206 58.651 ;
     RECT  2.34 57.983 21.474 58.747 ;
     RECT  0.108 58.651 1.314 58.973 ;
     RECT  22.248 58.487 217.818 58.987 ;
     RECT  2.304 58.747 21.474 59.035 ;
     RECT  22.212 58.987 217.818 59.035 ;
     RECT  219.42 58.451 220.302 59.189 ;
     RECT  2.304 59.035 217.818 59.225 ;
     RECT  0.18 58.973 1.314 59.233 ;
     RECT  2.304 59.225 203.274 59.233 ;
     RECT  204.192 59.225 217.818 59.575 ;
     RECT  204.192 59.575 217.854 59.659 ;
     RECT  219.456 59.189 220.302 59.693 ;
     RECT  204.192 59.659 218.286 59.765 ;
     RECT  204.3 59.765 218.286 59.837 ;
     RECT  0.18 59.233 203.274 59.885 ;
     RECT  2.268 59.885 203.274 60.035 ;
     RECT  204.876 59.837 218.286 60.305 ;
     RECT  204.876 60.305 218.25 60.413 ;
     RECT  219.456 59.693 219.474 60.557 ;
     RECT  204.876 60.413 217.818 60.845 ;
     RECT  2.304 60.035 203.274 60.989 ;
     RECT  0.18 59.885 1.422 61.051 ;
     RECT  220.284 59.693 220.302 61.051 ;
     RECT  220.14 61.051 220.302 61.079 ;
     RECT  0.108 61.051 1.422 61.187 ;
     RECT  205.56 60.845 217.818 61.195 ;
     RECT  220.14 61.079 220.23 61.291 ;
     RECT  220.032 61.291 220.23 61.321 ;
     RECT  205.56 61.195 217.854 61.349 ;
     RECT  219.996 61.321 220.23 61.517 ;
     RECT  220.032 61.517 220.23 61.901 ;
     RECT  0.108 61.187 1.242 61.925 ;
     RECT  2.376 60.989 203.274 62.107 ;
     RECT  0.144 61.925 1.242 62.131 ;
     RECT  218.844 61.387 218.862 62.155 ;
     RECT  2.304 62.107 203.274 62.195 ;
     RECT  218.808 62.155 218.862 62.203 ;
     RECT  0.144 62.131 1.278 62.303 ;
     RECT  205.56 61.349 217.818 62.311 ;
     RECT  16.92 62.195 203.274 62.339 ;
     RECT  16.92 62.339 200.934 62.381 ;
     RECT  218.772 62.203 218.862 62.381 ;
     RECT  2.304 62.195 15.966 62.537 ;
     RECT  16.92 62.381 21.726 62.573 ;
     RECT  205.56 62.311 217.854 62.581 ;
     RECT  0.144 62.303 0.162 62.621 ;
     RECT  218.808 62.381 218.862 62.635 ;
     RECT  205.56 62.581 217.962 62.699 ;
     RECT  1.152 62.303 1.278 62.735 ;
     RECT  16.92 62.573 21.69 62.765 ;
     RECT  1.224 62.735 1.278 63.005 ;
     RECT  2.304 62.537 14.274 63.067 ;
     RECT  16.92 62.765 21.654 63.077 ;
     RECT  218.808 62.635 219.438 63.077 ;
     RECT  18.288 63.077 21.654 63.113 ;
     RECT  22.5 62.381 200.934 63.113 ;
     RECT  202.032 62.339 203.274 63.149 ;
     RECT  1.656 63.067 14.274 63.275 ;
     RECT  219.42 63.077 219.438 63.403 ;
     RECT  220.176 61.901 220.23 63.403 ;
     RECT  18.432 63.113 21.654 63.509 ;
     RECT  15.516 62.537 15.966 63.617 ;
     RECT  203.256 63.149 203.274 63.779 ;
     RECT  202.032 63.149 202.497 63.883 ;
     RECT  0.108 62.779 0.126 63.931 ;
     RECT  219.42 63.403 220.23 63.931 ;
     RECT  202.032 63.883 202.59 64.061 ;
     RECT  18.615 63.509 21.654 64.075 ;
     RECT  22.5 63.113 200.826 64.075 ;
     RECT  0.108 63.931 0.162 64.219 ;
     RECT  0.108 64.219 0.342 64.349 ;
     RECT  1.656 63.275 12.366 64.733 ;
     RECT  205.56 62.699 217.854 64.903 ;
     RECT  205.56 64.903 217.89 64.939 ;
     RECT  218.88 63.931 220.23 64.939 ;
     RECT  2.268 64.733 12.366 65.003 ;
     RECT  15.516 63.617 15.822 65.039 ;
     RECT  202.032 64.061 202.497 65.129 ;
     RECT  205.56 64.939 220.23 65.309 ;
     RECT  13.104 63.275 14.274 65.471 ;
     RECT  205.56 65.309 219.402 65.507 ;
     RECT  206.064 65.507 219.402 65.543 ;
     RECT  0.108 64.349 0.306 65.813 ;
     RECT  0.288 65.813 0.306 65.851 ;
     RECT  0.288 65.851 0.342 65.975 ;
     RECT  206.064 65.543 218.898 65.975 ;
     RECT  207.18 65.975 218.898 66.245 ;
     RECT  208.62 66.245 218.898 66.475 ;
     RECT  0.324 65.975 0.342 66.557 ;
     RECT  220.14 65.309 220.23 66.559 ;
     RECT  220.14 66.559 220.302 66.605 ;
     RECT  1.404 66.043 1.422 66.619 ;
     RECT  13.104 65.471 14.166 66.785 ;
     RECT  208.62 66.475 219.15 67.019 ;
     RECT  0.108 66.715 0.198 67.055 ;
     RECT  208.62 67.019 210.546 67.055 ;
     RECT  0.144 67.055 0.198 67.085 ;
     RECT  206.064 65.975 206.082 67.135 ;
     RECT  207.18 66.245 207.897 67.135 ;
     RECT  206.064 67.135 207.897 67.181 ;
     RECT  206.064 67.181 206.082 67.199 ;
     RECT  208.62 67.055 208.674 67.289 ;
     RECT  15.516 65.039 15.678 67.325 ;
     RECT  209.52 67.055 210.474 67.433 ;
     RECT  220.176 66.605 220.302 67.469 ;
     RECT  208.62 67.289 208.638 67.559 ;
     RECT  210.42 67.433 210.474 67.631 ;
     RECT  1.404 66.619 1.53 67.667 ;
     RECT  1.404 67.667 1.458 67.675 ;
     RECT  0.144 67.085 0.162 67.867 ;
     RECT  0.108 67.867 0.162 67.937 ;
     RECT  0.144 67.937 0.162 67.963 ;
     RECT  220.212 67.469 220.302 68.009 ;
     RECT  211.284 67.019 219.15 68.099 ;
     RECT  0.144 67.963 0.378 68.189 ;
     RECT  0.144 68.189 0.27 68.237 ;
     RECT  1.152 67.675 1.458 68.279 ;
     RECT  214.884 68.099 215.694 68.279 ;
     RECT  220.284 68.009 220.302 68.279 ;
     RECT  0.252 68.237 0.27 68.342 ;
     RECT  2.304 65.003 12.366 68.377 ;
     RECT  2.304 68.377 12.474 68.521 ;
     RECT  13.215 66.785 14.166 68.521 ;
     RECT  216.612 68.099 219.15 68.639 ;
     RECT  219.132 68.639 219.15 68.747 ;
     RECT  2.304 68.521 14.202 68.791 ;
     RECT  211.284 68.099 214.038 68.819 ;
     RECT  215.496 68.279 215.694 68.909 ;
     RECT  2.304 68.791 14.238 69.061 ;
     RECT  216.612 68.639 218.286 69.179 ;
     RECT  0.324 69.115 0.342 69.223 ;
     RECT  217.152 69.179 218.034 69.251 ;
     RECT  2.232 69.061 14.454 69.331 ;
     RECT  0.252 69.223 0.342 69.403 ;
     RECT  217.404 69.251 218.034 69.449 ;
     RECT  0.108 69.403 0.342 69.485 ;
     RECT  217.836 69.449 217.854 69.521 ;
     RECT  15.66 67.325 15.678 69.529 ;
     RECT  0.144 69.485 0.342 69.763 ;
     RECT  1.152 68.279 1.242 69.763 ;
     RECT  0.144 69.763 1.242 69.821 ;
     RECT  15.48 69.529 15.678 69.871 ;
     RECT  2.232 69.331 14.526 69.997 ;
     RECT  15.48 69.871 15.894 69.997 ;
     RECT  2.232 69.997 15.894 70.141 ;
     RECT  0.144 69.821 0.342 70.363 ;
     RECT  1.152 69.821 1.242 70.555 ;
     RECT  0.108 70.363 0.342 70.601 ;
     RECT  2.232 70.141 15.93 70.601 ;
     RECT  1.152 70.555 1.278 70.685 ;
     RECT  0.144 70.601 0.342 70.843 ;
     RECT  1.152 70.685 1.17 70.843 ;
     RECT  2.268 70.601 15.93 70.951 ;
     RECT  0.144 70.843 1.17 71.177 ;
     RECT  2.268 70.951 16.074 71.249 ;
     RECT  2.268 71.249 15.498 71.447 ;
     RECT  1.152 71.177 1.17 71.467 ;
     RECT  0.144 71.177 0.306 71.515 ;
     RECT  1.152 71.467 1.206 71.611 ;
     RECT  0.108 71.515 0.306 71.645 ;
     RECT  1.152 71.611 1.278 71.803 ;
     RECT  0.144 71.645 0.306 71.899 ;
     RECT  0.144 71.899 0.342 72.029 ;
     RECT  2.304 71.447 15.498 72.031 ;
     RECT  0.144 72.029 0.234 72.269 ;
     RECT  2.304 72.031 15.858 72.379 ;
     RECT  2.196 72.379 15.858 72.571 ;
     RECT  2.196 72.571 15.894 72.689 ;
     RECT  2.196 72.689 14.49 72.725 ;
     RECT  15.876 72.689 15.894 72.797 ;
     RECT  2.196 72.725 14.166 72.959 ;
     RECT  2.196 72.959 13.986 72.995 ;
     RECT  1.152 71.803 1.422 73.031 ;
     RECT  2.196 72.995 13.554 73.031 ;
     RECT  1.332 73.031 1.422 73.103 ;
     RECT  10.44 73.031 13.554 73.229 ;
     RECT  2.196 73.031 9.666 73.265 ;
     RECT  2.232 73.265 9.666 73.409 ;
     RECT  10.548 73.229 13.497 73.409 ;
     RECT  10.548 73.409 12.366 73.499 ;
     RECT  10.548 73.499 12.294 73.535 ;
     RECT  2.232 73.409 9.63 73.571 ;
     RECT  10.548 73.535 11.898 73.571 ;
     RECT  10.728 73.571 11.898 73.805 ;
     RECT  10.728 73.805 10.746 73.877 ;
     RECT  1.332 73.103 1.35 73.913 ;
     RECT  11.88 73.805 11.898 73.913 ;
     RECT  2.304 73.571 9.63 74.039 ;
     RECT  0.108 72.475 0.126 74.345 ;
     RECT  2.304 74.039 9.306 74.489 ;
     RECT  2.415 74.489 9.306 74.579 ;
     RECT  2.415 74.579 8.55 74.849 ;
     RECT  3.564 74.849 8.55 75.119 ;
     RECT  18.615 64.075 200.826 76.775 ;
     RECT  14.724 76.747 14.742 76.883 ;
     RECT  16.92 63.077 17.55 80.555 ;
     RECT  9.288 74.579 9.306 89.771 ;
     RECT  4.104 75.119 8.097 90.619 ;
     RECT  3.924 90.619 8.097 91.085 ;
     RECT  19.656 76.775 200.826 94.248 ;
     RECT  4.104 91.085 8.097 94.361 ;
     RECT  4.104 94.361 4.842 94.595 ;
     RECT  4.104 94.595 4.194 94.711 ;
     RECT  4.068 94.711 4.194 94.829 ;
     RECT  4.104 94.829 4.194 94.901 ;
     RECT  83.52 94.248 83.61 95.009 ;
     RECT  82.548 94.248 82.566 95.026 ;
     RECT  86.616 94.248 86.634 95.054 ;
     RECT  211.284 68.819 213.678 95.513 ;
     RECT  91.98 94.248 91.998 95.521 ;
     RECT  210.42 67.631 210.438 95.549 ;
     RECT  9.648 95.179 9.666 95.639 ;
     RECT  10.332 95.707 10.35 95.747 ;
     RECT  90 95.449 90.018 96.061 ;
     RECT  211.932 95.513 213.678 96.089 ;
     RECT  93.096 96.106 93.114 96.151 ;
     RECT  108.936 95.647 108.954 96.151 ;
     RECT  19.656 94.248 23.094 96.179 ;
     RECT  212.508 96.089 213.678 96.179 ;
     RECT  212.508 96.179 213.297 96.215 ;
     RECT  43.02 96.106 43.038 96.295 ;
     RECT  96.3 94.248 96.318 96.295 ;
     RECT  19.944 96.179 23.094 96.359 ;
     RECT  84.384 96.025 84.402 96.359 ;
     RECT  61.524 95.521 61.542 96.373 ;
     RECT  83.52 95.009 83.538 96.373 ;
     RECT  88.92 95.449 88.938 96.373 ;
     RECT  94.608 95.566 94.626 96.373 ;
     RECT  99.36 96.061 99.378 96.373 ;
     RECT  116.496 95.611 116.514 96.373 ;
     RECT  197.496 94.248 200.826 96.373 ;
     RECT  29.607 96.373 29.697 96.421 ;
     RECT  80.316 94.981 80.334 96.421 ;
     RECT  70.704 96.331 70.722 96.449 ;
     RECT  79.2 94.248 79.218 96.449 ;
     RECT  80.316 96.421 80.406 96.449 ;
     RECT  81.504 96.331 81.522 96.449 ;
     RECT  82.548 95.026 82.638 96.449 ;
     RECT  87.228 96.331 87.246 96.449 ;
     RECT  90 96.061 90.054 96.449 ;
     RECT  91.98 95.521 92.322 96.449 ;
     RECT  93.096 96.151 93.51 96.449 ;
     RECT  95.868 96.295 96.318 96.449 ;
     RECT  100.728 94.981 100.746 96.449 ;
     RECT  116.007 96.373 116.514 96.449 ;
     RECT  80.388 96.449 80.406 96.461 ;
     RECT  113.04 96.421 113.058 96.461 ;
     RECT  114.156 96.421 114.174 96.461 ;
     RECT  48.204 96.025 48.222 96.485 ;
     RECT  116.007 96.449 116.262 96.509 ;
     RECT  29.607 96.421 29.934 96.521 ;
     RECT  43.02 96.295 43.362 96.521 ;
     RECT  4.176 94.901 4.194 96.557 ;
     RECT  194.364 96.427 194.382 96.557 ;
     RECT  91.224 95.485 91.242 96.601 ;
     RECT  99.36 96.373 99.897 96.601 ;
     RECT  24.207 96.373 24.297 96.643 ;
     RECT  29.607 96.521 29.697 96.643 ;
     RECT  35.007 96.373 35.097 96.643 ;
     RECT  40.407 96.373 40.497 96.643 ;
     RECT  45.807 96.373 45.897 96.643 ;
     RECT  51.207 96.373 51.297 96.643 ;
     RECT  56.607 96.373 56.697 96.643 ;
     RECT  67.407 96.373 67.497 96.643 ;
     RECT  72.807 96.373 72.897 96.643 ;
     RECT  78.207 96.373 78.297 96.643 ;
     RECT  83.52 96.373 83.697 96.643 ;
     RECT  88.92 96.373 89.097 96.643 ;
     RECT  93.168 96.449 93.51 96.643 ;
     RECT  94.407 96.373 94.626 96.643 ;
     RECT  105.207 96.373 105.297 96.643 ;
     RECT  110.607 96.373 110.697 96.643 ;
     RECT  116.007 96.509 116.097 96.643 ;
     RECT  121.407 96.373 121.497 96.643 ;
     RECT  126.807 96.373 126.897 96.643 ;
     RECT  132.207 96.373 132.297 96.643 ;
     RECT  137.607 96.373 137.697 96.643 ;
     RECT  143.007 96.373 143.097 96.643 ;
     RECT  148.407 96.373 148.497 96.643 ;
     RECT  153.807 96.373 153.897 96.643 ;
     RECT  159.207 96.373 159.297 96.643 ;
     RECT  164.607 96.373 164.697 96.643 ;
     RECT  170.007 96.373 170.097 96.643 ;
     RECT  175.407 96.373 175.497 96.643 ;
     RECT  180.807 96.373 180.897 96.643 ;
     RECT  186.207 96.373 186.297 96.643 ;
     RECT  191.607 96.373 191.697 96.643 ;
     RECT  197.007 96.373 200.826 96.643 ;
     RECT  61.524 96.373 62.097 96.719 ;
     RECT  108.828 96.151 108.954 96.719 ;
     RECT  113.292 96.691 113.31 96.749 ;
     RECT  43.02 96.521 43.038 96.755 ;
     RECT  112.176 96.715 112.194 96.755 ;
     RECT  90.036 96.449 90.054 96.763 ;
     RECT  91.224 96.601 91.494 96.871 ;
     RECT  92.304 96.449 92.322 96.989 ;
     RECT  93.168 96.643 94.626 96.997 ;
     RECT  14.652 96.997 14.67 97.037 ;
     RECT  97.2 96.961 97.218 97.061 ;
     RECT  196.815 96.643 200.826 97.097 ;
     RECT  90.036 96.763 90.09 97.141 ;
     RECT  90.9 96.871 91.494 97.141 ;
     RECT  93.168 96.997 94.734 97.141 ;
     RECT  14.832 97.141 14.922 97.259 ;
     RECT  86.112 96.601 86.13 97.259 ;
     RECT  16.308 97.231 16.326 97.267 ;
     RECT  17.532 80.555 17.55 97.267 ;
     RECT  5.796 94.361 8.097 97.295 ;
     RECT  90.036 97.141 91.494 97.295 ;
     RECT  14.832 97.259 14.85 97.331 ;
     RECT  16.308 97.267 17.55 97.331 ;
     RECT  16.848 97.331 17.55 97.439 ;
     RECT  99.18 96.601 99.897 97.529 ;
     RECT  17.532 97.439 17.55 97.565 ;
     RECT  209.52 67.433 209.538 98.069 ;
     RECT  110.415 96.643 110.697 98.221 ;
     RECT  203.76 66.523 203.778 98.339 ;
     RECT  108.936 96.719 108.954 98.491 ;
     RECT  198.072 97.097 200.826 99.959 ;
     RECT  21.924 96.359 23.094 100.039 ;
     RECT  21.636 100.039 23.094 100.769 ;
     RECT  162.936 96.187 162.954 100.769 ;
     RECT  19.944 96.359 20.826 100.777 ;
     RECT  75.348 96.601 75.366 100.805 ;
     RECT  19.8 100.777 20.826 100.829 ;
     RECT  78.015 96.643 78.297 101.155 ;
     RECT  5.796 97.295 6.678 101.183 ;
     RECT  102.564 101.317 102.582 101.357 ;
     RECT  103.68 101.281 103.698 101.357 ;
     RECT  199.224 99.959 200.826 101.579 ;
     RECT  7.452 97.295 8.097 101.759 ;
     RECT  90.9 97.295 91.494 102.119 ;
     RECT  5.796 101.183 6.246 103.469 ;
     RECT  61.815 96.719 62.097 103.621 ;
     RECT  93.168 97.141 94.914 103.649 ;
     RECT  91.476 102.119 91.494 103.739 ;
     RECT  61.668 103.621 62.097 103.771 ;
     RECT  61.416 103.771 62.097 103.811 ;
     RECT  61.668 103.811 62.097 103.919 ;
     RECT  141.912 95.683 141.93 104.017 ;
     RECT  107.424 96.871 107.442 104.279 ;
     RECT  19.944 100.829 20.826 104.315 ;
     RECT  59.868 103.441 59.886 104.729 ;
     RECT  93.492 103.649 94.914 104.819 ;
     RECT  122.328 95.071 122.346 104.819 ;
     RECT  19.944 104.315 20.79 104.855 ;
     RECT  64.008 104.701 64.026 104.927 ;
     RECT  78.015 101.155 79.002 105.331 ;
     RECT  79.884 98.887 79.902 105.331 ;
     RECT  78.015 105.331 79.902 105.389 ;
     RECT  111.636 105.355 111.654 105.395 ;
     RECT  108.396 98.491 108.954 105.643 ;
     RECT  21.924 100.769 23.094 105.665 ;
     RECT  77.112 105.601 77.13 105.677 ;
     RECT  90.036 97.295 90.054 105.781 ;
     RECT  198.072 99.959 198.162 105.809 ;
     RECT  121.215 96.643 121.497 105.871 ;
     RECT  132.015 96.643 132.297 105.871 ;
     RECT  142.815 96.643 143.097 105.871 ;
     RECT  153.615 96.643 153.897 105.871 ;
     RECT  164.415 96.643 164.697 105.871 ;
     RECT  175.215 96.643 175.497 105.871 ;
     RECT  186.015 96.643 186.297 105.871 ;
     RECT  90.036 105.781 90.306 105.899 ;
     RECT  107.712 105.643 108.954 105.899 ;
     RECT  114.696 105.739 114.714 105.899 ;
     RECT  82.548 96.449 82.566 105.931 ;
     RECT  83.415 96.643 83.697 105.931 ;
     RECT  82.548 105.931 83.697 105.935 ;
     RECT  90.036 105.899 90.054 105.935 ;
     RECT  82.8 105.935 83.697 105.971 ;
     RECT  113.58 105.931 113.598 105.971 ;
     RECT  100.8 99.301 100.818 106.079 ;
     RECT  79.884 105.389 79.902 106.168 ;
     RECT  74.628 106.051 74.646 106.169 ;
     RECT  78.015 105.389 79.002 106.177 ;
     RECT  79.776 106.168 79.902 106.177 ;
     RECT  6.228 103.469 6.246 106.205 ;
     RECT  81.252 100.003 81.27 106.205 ;
     RECT  108.18 105.899 108.954 106.219 ;
     RECT  109.692 98.221 110.697 106.219 ;
     RECT  194.364 105.691 194.382 106.219 ;
     RECT  78.015 106.177 79.902 106.253 ;
     RECT  81.504 106.213 81.522 106.253 ;
     RECT  108.18 106.219 110.697 106.267 ;
     RECT  194.364 106.219 194.562 106.301 ;
     RECT  194.472 106.301 194.562 106.349 ;
     RECT  88.815 96.643 89.097 106.411 ;
     RECT  99.615 97.529 99.897 106.411 ;
     RECT  105.015 96.643 105.297 106.411 ;
     RECT  108.18 106.267 110.79 106.439 ;
     RECT  194.472 106.349 194.49 106.445 ;
     RECT  79.776 106.253 79.902 106.448 ;
     RECT  121.104 105.871 121.497 106.448 ;
     RECT  131.904 105.871 132.297 106.448 ;
     RECT  142.704 105.871 143.097 106.448 ;
     RECT  153.504 105.871 153.897 106.448 ;
     RECT  164.304 105.871 164.697 106.448 ;
     RECT  175.104 105.871 175.497 106.448 ;
     RECT  185.904 105.871 186.297 106.448 ;
     RECT  21.924 105.665 22.626 106.475 ;
     RECT  106.272 97.771 106.29 106.507 ;
     RECT  106.272 106.507 107.01 106.547 ;
     RECT  13.215 73.409 13.497 106.843 ;
     RECT  24.015 96.643 24.297 106.843 ;
     RECT  34.815 96.643 35.097 106.843 ;
     RECT  45.615 96.643 45.897 106.843 ;
     RECT  56.415 96.643 56.697 106.843 ;
     RECT  67.215 96.643 67.497 106.843 ;
     RECT  78.015 106.253 79.002 106.843 ;
     RECT  198.072 105.809 198.126 106.853 ;
     RECT  13.104 106.843 13.497 106.889 ;
     RECT  23.904 106.843 24.297 106.889 ;
     RECT  34.704 106.843 35.097 106.889 ;
     RECT  45.504 106.843 45.897 106.889 ;
     RECT  56.304 106.843 56.697 106.889 ;
     RECT  67.104 106.843 67.497 106.889 ;
     RECT  77.904 106.843 79.002 106.889 ;
     RECT  88.704 106.411 89.097 106.889 ;
     RECT  99.504 106.411 99.897 106.889 ;
     RECT  106.272 106.547 106.614 106.889 ;
     RECT  199.224 101.579 199.278 106.889 ;
     RECT  102.6 106.861 102.618 106.979 ;
     RECT  106.596 106.889 106.614 106.979 ;
     RECT  19.944 104.855 20.754 107.015 ;
     RECT  104.904 106.411 105.297 107.015 ;
     RECT  78.015 106.889 79.002 107.179 ;
     RECT  79.884 106.448 79.902 107.179 ;
     RECT  97.164 101.551 97.182 107.401 ;
     RECT  199.26 106.889 199.278 107.429 ;
     RECT  78.015 107.179 79.902 107.491 ;
     RECT  78.015 107.491 80.154 107.519 ;
     RECT  97.164 107.401 97.65 107.519 ;
     RECT  79.884 107.519 80.154 107.549 ;
     RECT  78.015 107.519 79.002 107.555 ;
     RECT  79.884 107.549 79.902 107.555 ;
     RECT  108.396 106.439 110.697 107.555 ;
     RECT  97.164 107.519 97.398 107.6 ;
     RECT  72.615 96.643 72.897 107.761 ;
     RECT  98.46 101.731 98.622 107.789 ;
     RECT  141.768 104.017 141.93 107.789 ;
     RECT  72.615 107.761 73.782 107.797 ;
     RECT  105.015 107.015 105.297 107.797 ;
     RECT  19.944 107.015 20.286 107.825 ;
     RECT  98.46 107.789 98.478 107.825 ;
     RECT  141.768 107.789 141.786 107.825 ;
     RECT  105.015 107.797 105.93 107.837 ;
     RECT  88.815 106.889 89.097 107.851 ;
     RECT  72.615 107.797 73.854 107.861 ;
     RECT  109.692 107.555 110.697 107.861 ;
     RECT  108.396 107.555 108.414 107.897 ;
     RECT  70.74 107.797 70.758 107.933 ;
     RECT  73.836 107.861 73.854 107.933 ;
     RECT  88.632 107.851 89.097 107.933 ;
     RECT  200.16 101.579 200.826 107.933 ;
     RECT  200.808 107.933 200.826 107.969 ;
     RECT  97.164 107.6 97.182 108.329 ;
     RECT  71.532 95.485 71.55 108.365 ;
     RECT  5.436 108.283 5.454 108.599 ;
     RECT  112.536 100.111 112.554 108.779 ;
     RECT  93.492 104.819 94.497 108.859 ;
     RECT  84.456 108.751 84.474 108.869 ;
     RECT  198.108 106.853 198.126 108.869 ;
     RECT  99.615 106.889 99.897 108.904 ;
     RECT  19.98 107.825 20.286 108.905 ;
     RECT  6.228 108.751 6.246 108.941 ;
     RECT  99.615 108.904 100.314 108.941 ;
     RECT  93.276 108.859 94.497 109.139 ;
     RECT  21.924 106.475 21.942 109.175 ;
     RECT  93.492 109.139 94.497 109.175 ;
     RECT  207.18 67.181 207.897 109.679 ;
     RECT  20.268 108.905 20.286 109.715 ;
     RECT  2.415 74.849 2.697 114.227 ;
     RECT  7.815 101.759 8.097 114.227 ;
     RECT  13.215 106.889 13.497 114.227 ;
     RECT  18.615 76.775 18.897 114.227 ;
     RECT  24.015 106.889 24.297 114.227 ;
     RECT  29.415 96.643 29.697 114.227 ;
     RECT  34.815 106.889 35.097 114.227 ;
     RECT  40.215 96.643 40.497 114.227 ;
     RECT  45.615 106.889 45.897 114.227 ;
     RECT  51.015 96.643 51.297 114.227 ;
     RECT  56.415 106.889 56.697 114.227 ;
     RECT  61.815 103.919 62.097 114.227 ;
     RECT  67.215 106.889 67.497 114.227 ;
     RECT  72.615 107.861 72.897 114.227 ;
     RECT  78.015 107.555 78.297 114.227 ;
     RECT  83.415 105.971 83.697 114.227 ;
     RECT  88.815 107.933 89.097 114.227 ;
     RECT  94.215 109.175 94.497 114.227 ;
     RECT  99.615 108.941 99.897 114.227 ;
     RECT  105.015 107.837 105.297 114.227 ;
     RECT  110.415 107.861 110.697 114.227 ;
     RECT  115.815 96.643 116.097 114.227 ;
     RECT  121.215 106.448 121.497 114.227 ;
     RECT  126.615 96.643 126.897 114.227 ;
     RECT  132.015 106.448 132.297 114.227 ;
     RECT  137.415 96.643 137.697 114.227 ;
     RECT  142.815 106.448 143.097 114.227 ;
     RECT  148.215 96.643 148.497 114.227 ;
     RECT  153.615 106.448 153.897 114.227 ;
     RECT  159.015 96.643 159.297 114.227 ;
     RECT  164.415 106.448 164.697 114.227 ;
     RECT  169.815 96.643 170.097 114.227 ;
     RECT  175.215 106.448 175.497 114.227 ;
     RECT  180.615 96.643 180.897 114.227 ;
     RECT  186.015 106.448 186.297 114.227 ;
     RECT  191.415 96.643 191.697 114.227 ;
     RECT  196.815 97.097 197.097 114.227 ;
     RECT  202.215 65.129 202.497 114.227 ;
     RECT  207.615 109.679 207.897 114.227 ;
     RECT  213.015 96.215 213.297 114.227 ;
     RECT  2.415 114.227 2.505 114.497 ;
     RECT  7.815 114.227 7.905 114.497 ;
     RECT  13.215 114.227 13.305 114.497 ;
     RECT  18.615 114.227 18.705 114.497 ;
     RECT  24.015 114.227 24.105 114.497 ;
     RECT  29.415 114.227 29.505 114.497 ;
     RECT  34.815 114.227 34.905 114.497 ;
     RECT  40.215 114.227 40.305 114.497 ;
     RECT  45.615 114.227 45.705 114.497 ;
     RECT  51.015 114.227 51.105 114.497 ;
     RECT  56.415 114.227 56.505 114.497 ;
     RECT  61.815 114.227 61.905 114.497 ;
     RECT  67.215 114.227 67.305 114.497 ;
     RECT  72.615 114.227 72.705 114.497 ;
     RECT  78.015 114.227 78.105 114.497 ;
     RECT  83.415 114.227 83.505 114.497 ;
     RECT  88.815 114.227 88.905 114.497 ;
     RECT  94.215 114.227 94.305 114.497 ;
     RECT  99.615 114.227 99.705 114.497 ;
     RECT  105.015 114.227 105.105 114.497 ;
     RECT  110.415 114.227 110.505 114.497 ;
     RECT  115.815 114.227 115.905 114.497 ;
     RECT  121.215 114.227 121.305 114.497 ;
     RECT  126.615 114.227 126.705 114.497 ;
     RECT  132.015 114.227 132.105 114.497 ;
     RECT  137.415 114.227 137.505 114.497 ;
     RECT  142.815 114.227 142.905 114.497 ;
     RECT  148.215 114.227 148.305 114.497 ;
     RECT  153.615 114.227 153.705 114.497 ;
     RECT  159.015 114.227 159.105 114.497 ;
     RECT  164.415 114.227 164.505 114.497 ;
     RECT  169.815 114.227 169.905 114.497 ;
     RECT  175.215 114.227 175.305 114.497 ;
     RECT  180.615 114.227 180.705 114.497 ;
     RECT  186.015 114.227 186.105 114.497 ;
     RECT  191.415 114.227 191.505 114.497 ;
     RECT  196.815 114.227 196.905 114.497 ;
     RECT  202.215 114.227 202.305 114.497 ;
     RECT  207.615 114.227 207.705 114.497 ;
     RECT  213.015 114.227 213.105 114.497 ;
    LAYER M4 ;
     RECT  0.06 43.68 0.133 73.08 ;
     RECT  0.133 43.296 0.181 73.08 ;
     RECT  0.06 24.528 2.408 24.552 ;
     RECT  0.181 43.104 2.408 73.08 ;
     RECT  2.293 75.408 2.408 75.432 ;
     RECT  2.408 2.148 2.512 114.492 ;
     RECT  2.512 2.418 2.704 114.222 ;
     RECT  3.913 90.624 3.997 90.648 ;
     RECT  2.704 42.144 4.277 75.432 ;
     RECT  3.973 20.832 4.309 20.856 ;
     RECT  4.981 23.328 5.125 23.352 ;
     RECT  4.309 20.832 5.173 21.48 ;
     RECT  4.277 42.144 5.353 75.288 ;
     RECT  5.317 107.856 5.365 107.88 ;
     RECT  4.453 96.432 5.413 96.456 ;
     RECT  5.353 42.144 5.437 75.816 ;
     RECT  5.365 107.856 5.461 108.312 ;
     RECT  5.461 106.992 5.465 108.312 ;
     RECT  5.465 106.992 5.605 107.88 ;
     RECT  5.437 42.144 5.789 74.856 ;
     RECT  5.125 22.464 5.797 23.352 ;
     RECT  2.704 24.528 5.797 24.552 ;
     RECT  5.789 42.576 5.939 74.856 ;
     RECT  5.413 96.432 6.541 97.032 ;
     RECT  6.541 95.76 6.803 97.032 ;
     RECT  5.605 19.344 6.853 19.368 ;
     RECT  5.173 20.688 6.853 21.48 ;
     RECT  5.939 42.576 6.973 59.496 ;
     RECT  5.939 60.768 6.973 74.856 ;
     RECT  6.853 19.344 6.997 21.48 ;
     RECT  6.997 19.296 7.237 21.48 ;
     RECT  7.237 18.72 7.429 21.48 ;
     RECT  5.797 22.464 7.429 24.552 ;
     RECT  7.429 18.72 7.808 24.552 ;
     RECT  6.421 29.904 7.808 29.928 ;
     RECT  6.973 42.576 7.808 74.856 ;
     RECT  6.803 96.288 7.808 97.032 ;
     RECT  6.613 100.8 7.808 100.824 ;
     RECT  5.509 103.776 7.808 103.8 ;
     RECT  5.605 106.224 7.808 107.88 ;
     RECT  6.217 108.912 7.808 108.936 ;
     RECT  7.808 2.148 7.912 114.492 ;
     RECT  7.912 2.418 8.104 114.222 ;
     RECT  8.104 42.576 8.417 74.712 ;
     RECT  8.417 42.72 8.597 74.712 ;
     RECT  8.597 44.16 8.771 74.712 ;
     RECT  8.771 44.16 8.963 73.848 ;
     RECT  8.963 44.16 9.011 45 ;
     RECT  8.963 46.032 9.029 73.848 ;
     RECT  9.011 44.976 9.101 45 ;
     RECT  8.597 42.72 9.107 42.792 ;
     RECT  9.029 46.032 9.173 73.8 ;
     RECT  9.107 42.72 9.209 42.744 ;
     RECT  9.173 73.776 9.425 73.8 ;
     RECT  8.104 28.752 9.685 28.776 ;
     RECT  8.104 29.904 9.685 29.928 ;
     RECT  9.637 95.184 9.721 95.208 ;
     RECT  8.104 96.432 10.321 97.032 ;
     RECT  10.321 95.712 10.405 97.032 ;
     RECT  9.173 46.032 10.609 72.792 ;
     RECT  10.609 46.032 10.829 73.272 ;
     RECT  9.685 28.752 10.865 29.928 ;
     RECT  10.829 47.088 11.053 73.272 ;
     RECT  10.865 28.752 11.869 29.832 ;
     RECT  11.053 47.088 12.035 66.168 ;
     RECT  8.104 26.496 12.949 26.52 ;
     RECT  11.869 27.84 12.949 29.832 ;
     RECT  12.757 16.272 13.208 16.296 ;
     RECT  8.104 18.72 13.208 24.792 ;
     RECT  12.949 26.496 13.208 29.832 ;
     RECT  10.829 46.032 13.208 46.056 ;
     RECT  12.035 47.088 13.208 62.52 ;
     RECT  12.035 63.504 13.208 66.168 ;
     RECT  11.053 67.632 13.208 73.272 ;
     RECT  10.405 96.432 13.208 97.032 ;
     RECT  8.104 100.8 13.208 100.824 ;
     RECT  8.104 103.776 13.208 103.8 ;
     RECT  8.104 106.224 13.208 107.88 ;
     RECT  8.104 108.912 13.208 108.936 ;
     RECT  13.208 2.148 13.312 114.492 ;
     RECT  13.312 2.418 13.504 114.222 ;
     RECT  13.504 26.496 13.781 29.832 ;
     RECT  13.504 47.088 13.781 62.184 ;
     RECT  13.781 27.696 13.853 29.832 ;
     RECT  13.504 13.632 14.033 13.656 ;
     RECT  13.504 63.792 14.033 65.544 ;
     RECT  13.853 27.696 14.069 27.768 ;
     RECT  13.504 67.632 14.465 72.504 ;
     RECT  13.504 44.448 14.497 44.76 ;
     RECT  13.504 46.032 14.497 46.104 ;
     RECT  13.781 47.088 14.537 61.752 ;
     RECT  14.588 35.856 14.629 35.88 ;
     RECT  14.629 35.856 14.675 37.08 ;
     RECT  13.504 96.432 14.681 97.032 ;
     RECT  14.675 35.904 14.753 37.08 ;
     RECT  14.465 67.632 14.819 72.12 ;
     RECT  13.504 18.72 14.861 24.792 ;
     RECT  14.537 47.088 14.861 61.656 ;
     RECT  14.819 67.632 14.969 70.104 ;
     RECT  14.753 35.904 15.185 36.168 ;
     RECT  13.853 28.752 15.257 29.832 ;
     RECT  15.257 28.752 15.293 29.352 ;
     RECT  15.037 9.12 15.349 9.144 ;
     RECT  15.349 8.448 15.395 9.144 ;
     RECT  14.497 44.448 15.433 46.104 ;
     RECT  14.969 67.632 15.683 69.816 ;
     RECT  14.785 39.216 15.685 39.24 ;
     RECT  15.433 44.304 15.757 46.104 ;
     RECT  14.861 47.088 15.757 60.072 ;
     RECT  14.861 61.104 15.869 61.656 ;
     RECT  15.685 39.216 16.013 39.912 ;
     RECT  15.869 61.632 16.013 61.656 ;
     RECT  13.781 26.496 16.069 26.52 ;
     RECT  14.069 27.744 16.069 27.768 ;
     RECT  15.293 28.752 16.069 28.776 ;
     RECT  14.033 63.792 16.211 64.872 ;
     RECT  14.861 18.72 16.213 24.648 ;
     RECT  15.145 31.296 16.229 31.32 ;
     RECT  16.069 26.496 16.259 28.776 ;
     RECT  16.259 26.496 16.265 26.52 ;
     RECT  15.757 44.304 16.337 60.072 ;
     RECT  14.785 13.536 16.357 13.56 ;
     RECT  15.541 43.104 16.369 43.128 ;
     RECT  16.259 27.744 16.441 28.776 ;
     RECT  16.337 59.76 16.445 60.072 ;
     RECT  15.185 35.904 16.481 35.928 ;
     RECT  16.357 13.152 16.501 13.56 ;
     RECT  16.445 59.808 16.553 60.072 ;
     RECT  16.213 18.72 16.585 25.464 ;
     RECT  15.253 32.304 16.589 32.328 ;
     RECT  16.453 6.288 16.597 6.312 ;
     RECT  16.585 18.72 16.669 26.232 ;
     RECT  16.441 27.744 16.697 29.208 ;
     RECT  16.337 44.304 16.697 58.728 ;
     RECT  15.973 37.056 16.765 37.08 ;
     RECT  15.757 38.16 16.765 38.184 ;
     RECT  16.697 44.304 16.769 58.44 ;
     RECT  16.309 16.512 16.789 16.536 ;
     RECT  16.765 37.056 16.805 38.184 ;
     RECT  16.553 60.048 16.837 60.072 ;
     RECT  16.729 35.664 16.901 35.688 ;
     RECT  15.541 41.04 16.981 41.064 ;
     RECT  16.013 39.6 17.017 39.912 ;
     RECT  16.981 41.04 17.017 41.112 ;
     RECT  16.501 13.152 17.029 13.608 ;
     RECT  17.017 39.6 17.053 41.112 ;
     RECT  16.669 18.72 17.057 25.704 ;
     RECT  16.369 42.192 17.089 43.128 ;
     RECT  16.769 44.304 17.089 58.152 ;
     RECT  17.053 39.552 17.101 41.112 ;
     RECT  16.789 16.272 17.125 16.536 ;
     RECT  17.101 39.552 17.125 40.008 ;
     RECT  16.805 37.104 17.129 38.184 ;
     RECT  17.089 42.192 17.129 58.152 ;
     RECT  16.697 28.464 17.161 29.208 ;
     RECT  17.101 41.04 17.161 41.112 ;
     RECT  17.129 42.192 17.161 58.104 ;
     RECT  15.395 8.448 17.221 8.472 ;
     RECT  17.125 39.36 17.341 40.008 ;
     RECT  17.269 10.128 17.365 10.152 ;
     RECT  16.981 4.416 17.372 4.44 ;
     RECT  17.341 34.08 17.449 34.104 ;
     RECT  16.901 35.328 17.449 35.688 ;
     RECT  17.125 16.272 17.461 17.112 ;
     RECT  17.057 18.72 17.461 25.464 ;
     RECT  16.837 60.048 17.516 60.36 ;
     RECT  17.161 28.464 17.521 29.352 ;
     RECT  17.089 30.576 17.521 31.224 ;
     RECT  17.449 34.08 17.533 35.688 ;
     RECT  17.365 10.128 17.557 10.776 ;
     RECT  17.221 7.632 17.605 8.472 ;
     RECT  17.557 10.128 17.605 11.16 ;
     RECT  17.521 28.464 17.629 29.592 ;
     RECT  17.521 30.576 17.629 32.184 ;
     RECT  17.533 35.328 17.773 35.688 ;
     RECT  17.129 37.104 17.773 37.752 ;
     RECT  17.605 7.632 17.797 11.16 ;
     RECT  17.029 13.152 17.845 14.136 ;
     RECT  16.933 15.264 17.893 15.288 ;
     RECT  17.461 16.272 17.893 25.464 ;
     RECT  17.585 27.36 17.948 27.384 ;
     RECT  17.629 28.464 17.948 32.184 ;
     RECT  17.948 27.36 17.953 32.184 ;
     RECT  17.533 34.08 18.061 34.152 ;
     RECT  17.893 15.264 18.14 25.464 ;
     RECT  17.953 27.12 18.277 32.184 ;
     RECT  18.061 33.312 18.277 34.152 ;
     RECT  17.341 38.736 18.305 40.008 ;
     RECT  17.161 41.04 18.305 58.104 ;
     RECT  18.133 3.36 18.313 3.384 ;
     RECT  17.372 4.416 18.313 4.536 ;
     RECT  18.313 3.36 18.373 4.536 ;
     RECT  17.773 35.328 18.373 37.752 ;
     RECT  18.305 38.736 18.373 58.104 ;
     RECT  16.597 6.096 18.421 6.312 ;
     RECT  17.797 7.632 18.421 11.208 ;
     RECT  17.516 60 18.421 60.36 ;
     RECT  18.14 15.264 18.493 25.944 ;
     RECT  18.277 27.12 18.493 34.152 ;
     RECT  18.373 35.328 18.565 58.104 ;
     RECT  18.373 3.36 18.608 4.968 ;
     RECT  18.421 6.096 18.608 11.208 ;
     RECT  17.845 13.152 18.608 14.184 ;
     RECT  18.493 15.264 18.608 34.152 ;
     RECT  18.565 35.328 18.608 58.152 ;
     RECT  18.421 59.28 18.608 60.36 ;
     RECT  16.211 64.32 18.608 64.872 ;
     RECT  15.683 67.632 18.608 69.048 ;
     RECT  18.469 95.184 18.608 95.208 ;
     RECT  14.681 96.432 18.608 96.456 ;
     RECT  13.504 100.8 18.608 100.824 ;
     RECT  13.504 103.776 18.608 103.8 ;
     RECT  13.504 106.224 18.608 107.88 ;
     RECT  13.504 108.912 18.608 108.936 ;
     RECT  18.608 2.148 18.712 114.492 ;
     RECT  18.712 2.418 18.904 114.222 ;
     RECT  18.904 13.152 19.145 60.312 ;
     RECT  19.145 15.216 19.433 60.312 ;
     RECT  18.904 100.8 19.829 100.824 ;
     RECT  19.433 46.992 19.897 60.312 ;
     RECT  19.897 46.992 19.933 60.408 ;
     RECT  18.904 61.872 19.933 61.992 ;
     RECT  18.904 95.184 19.937 95.208 ;
     RECT  18.904 63.312 20.185 64.872 ;
     RECT  19.433 15.216 20.509 46.008 ;
     RECT  19.933 46.992 20.509 61.992 ;
     RECT  18.904 96.432 20.689 96.456 ;
     RECT  19.145 13.152 20.821 14.184 ;
     RECT  20.821 12.24 20.917 14.184 ;
     RECT  20.509 15.216 20.917 61.992 ;
     RECT  20.689 95.712 21.061 96.456 ;
     RECT  20.917 12.24 21.085 61.992 ;
     RECT  21.061 95.712 21.107 96.504 ;
     RECT  21.085 12.24 21.121 62.184 ;
     RECT  20.185 63.216 21.121 64.872 ;
     RECT  18.904 67.632 21.491 69.048 ;
     RECT  21.491 68.208 21.923 69.048 ;
     RECT  21.923 68.208 21.971 68.232 ;
     RECT  21.121 12.24 22.968 64.872 ;
     RECT  18.904 3.36 24.008 11.208 ;
     RECT  22.968 12.24 24.008 94.248 ;
     RECT  21.107 96.432 24.008 96.504 ;
     RECT  18.904 103.776 24.008 103.8 ;
     RECT  18.904 106.224 24.008 107.88 ;
     RECT  18.904 108.912 24.008 108.936 ;
     RECT  24.008 2.148 24.112 94.248 ;
     RECT  24.008 96.432 24.112 114.492 ;
     RECT  24.112 96.432 24.2 114.222 ;
     RECT  24.112 2.418 24.304 94.248 ;
     RECT  24.2 96.378 24.304 114.222 ;
     RECT  24.304 3.36 29.408 11.208 ;
     RECT  24.304 12.24 29.408 94.248 ;
     RECT  24.304 96.432 29.408 96.504 ;
     RECT  24.304 103.776 29.408 103.8 ;
     RECT  24.304 106.224 29.408 107.88 ;
     RECT  24.304 108.912 29.408 108.936 ;
     RECT  29.408 2.148 29.512 94.248 ;
     RECT  29.408 96.432 29.512 114.492 ;
     RECT  29.512 96.432 29.6 114.222 ;
     RECT  29.512 2.418 29.704 94.248 ;
     RECT  29.6 96.378 29.704 114.222 ;
     RECT  29.704 3.36 34.808 11.208 ;
     RECT  29.704 12.24 34.808 94.248 ;
     RECT  29.704 96.432 34.808 96.504 ;
     RECT  29.704 103.776 34.808 103.8 ;
     RECT  29.704 106.224 34.808 107.88 ;
     RECT  29.704 108.912 34.808 108.936 ;
     RECT  34.808 2.148 34.912 94.248 ;
     RECT  34.808 96.432 34.912 114.492 ;
     RECT  34.912 96.432 35 114.222 ;
     RECT  34.912 2.418 35.104 94.248 ;
     RECT  35 96.378 35.104 114.222 ;
     RECT  35.104 3.36 40.208 11.208 ;
     RECT  35.104 12.24 40.208 94.248 ;
     RECT  35.104 96.432 40.208 96.504 ;
     RECT  35.104 103.776 40.208 103.8 ;
     RECT  35.104 106.224 40.208 107.88 ;
     RECT  35.104 108.912 40.208 108.936 ;
     RECT  40.208 2.148 40.312 94.248 ;
     RECT  40.208 96.432 40.312 114.492 ;
     RECT  40.312 96.432 40.4 114.222 ;
     RECT  40.312 2.418 40.504 94.248 ;
     RECT  40.4 96.378 40.504 114.222 ;
     RECT  40.504 3.36 41.609 11.208 ;
     RECT  41.609 3.36 45.608 11.16 ;
     RECT  40.504 12.24 45.608 94.248 ;
     RECT  40.504 96.432 45.608 96.504 ;
     RECT  40.504 103.776 45.608 103.8 ;
     RECT  40.504 106.224 45.608 107.88 ;
     RECT  40.504 108.912 45.608 108.936 ;
     RECT  45.608 2.148 45.712 94.248 ;
     RECT  45.608 96.432 45.712 114.492 ;
     RECT  45.712 96.432 45.8 114.222 ;
     RECT  45.712 2.418 45.904 94.248 ;
     RECT  45.8 96.378 45.904 114.222 ;
     RECT  45.904 3.36 47.077 11.16 ;
     RECT  47.077 3.312 51.008 11.16 ;
     RECT  45.904 12.24 51.008 94.248 ;
     RECT  45.904 96.432 51.008 96.504 ;
     RECT  45.904 103.776 51.008 103.8 ;
     RECT  45.904 106.224 51.008 107.88 ;
     RECT  45.904 108.912 51.008 108.936 ;
     RECT  51.008 2.148 51.112 94.248 ;
     RECT  51.008 96.432 51.112 114.492 ;
     RECT  51.112 96.432 51.2 114.222 ;
     RECT  51.112 2.418 51.304 94.248 ;
     RECT  51.2 96.378 51.304 114.222 ;
     RECT  51.304 3.312 52.981 11.16 ;
     RECT  52.981 3.072 56.408 11.16 ;
     RECT  51.304 12.24 56.408 94.248 ;
     RECT  51.304 96.432 56.408 96.504 ;
     RECT  51.304 103.776 56.408 103.8 ;
     RECT  51.304 106.224 56.408 107.88 ;
     RECT  51.304 108.912 56.408 108.936 ;
     RECT  56.408 2.148 56.512 94.248 ;
     RECT  56.408 96.432 56.512 114.492 ;
     RECT  56.512 96.432 56.6 114.222 ;
     RECT  56.512 2.418 56.704 94.248 ;
     RECT  56.6 96.378 56.704 114.222 ;
     RECT  56.704 3.072 57.557 11.16 ;
     RECT  57.557 3.072 61.808 9.384 ;
     RECT  57.557 10.608 61.808 10.632 ;
     RECT  56.704 12.24 61.808 94.248 ;
     RECT  56.704 96.432 61.808 96.504 ;
     RECT  56.704 103.776 61.808 103.8 ;
     RECT  56.704 106.224 61.808 107.88 ;
     RECT  56.704 108.912 61.808 108.936 ;
     RECT  61.808 2.148 61.912 94.248 ;
     RECT  61.808 96.432 61.912 114.492 ;
     RECT  61.912 96.432 62 114.222 ;
     RECT  61.912 2.418 62.104 94.248 ;
     RECT  62 96.378 62.104 114.222 ;
     RECT  62.104 3.072 67.208 9.384 ;
     RECT  62.104 10.608 67.208 10.632 ;
     RECT  62.104 12.24 67.208 94.248 ;
     RECT  62.104 96.432 67.208 96.504 ;
     RECT  62.104 106.224 67.208 107.88 ;
     RECT  62.104 108.912 67.208 108.936 ;
     RECT  67.208 2.148 67.312 94.248 ;
     RECT  67.208 96.432 67.312 114.492 ;
     RECT  67.312 96.432 67.4 114.222 ;
     RECT  67.312 2.418 67.504 94.248 ;
     RECT  67.4 96.378 67.504 114.222 ;
     RECT  67.504 12.24 69.437 94.248 ;
     RECT  67.504 3.072 72.608 9.384 ;
     RECT  67.504 10.608 72.608 10.632 ;
     RECT  69.437 12.24 72.608 18.216 ;
     RECT  69.437 19.296 72.608 94.248 ;
     RECT  67.504 96.432 72.608 96.504 ;
     RECT  67.504 106.224 72.608 107.88 ;
     RECT  67.504 108.912 72.608 108.936 ;
     RECT  72.608 2.148 72.712 94.248 ;
     RECT  72.608 96.432 72.712 114.492 ;
     RECT  72.712 96.432 72.8 114.222 ;
     RECT  72.712 2.418 72.904 94.248 ;
     RECT  72.8 96.378 72.904 114.222 ;
     RECT  72.904 19.296 76.493 94.248 ;
     RECT  72.904 106.224 77.101 107.88 ;
     RECT  72.904 3.072 78.008 9.384 ;
     RECT  72.904 10.608 78.008 10.632 ;
     RECT  72.904 12.24 78.008 18.216 ;
     RECT  76.493 19.296 78.008 19.368 ;
     RECT  76.493 20.448 78.008 94.248 ;
     RECT  72.904 96.432 78.008 96.504 ;
     RECT  77.101 105.648 78.008 107.88 ;
     RECT  72.904 108.912 78.008 108.936 ;
     RECT  78.008 2.148 78.112 94.248 ;
     RECT  78.008 96.432 78.112 114.492 ;
     RECT  78.112 96.432 78.2 114.222 ;
     RECT  78.112 2.418 78.304 94.248 ;
     RECT  78.2 96.378 78.304 114.222 ;
     RECT  78.304 19.296 78.905 19.368 ;
     RECT  78.304 96.432 80.417 96.504 ;
     RECT  78.304 20.448 81.785 94.248 ;
     RECT  81.785 20.448 82.645 22.776 ;
     RECT  78.304 3.072 83.408 9.384 ;
     RECT  78.304 10.608 83.408 10.632 ;
     RECT  78.304 12.24 83.408 18.216 ;
     RECT  78.905 19.344 83.408 19.368 ;
     RECT  82.645 20.352 83.408 22.776 ;
     RECT  80.417 96.48 83.408 96.504 ;
     RECT  78.304 101.328 83.408 101.352 ;
     RECT  78.304 105.36 83.408 107.88 ;
     RECT  78.304 108.912 83.408 108.936 ;
     RECT  83.408 2.148 83.512 22.776 ;
     RECT  83.408 96.48 83.512 114.492 ;
     RECT  83.512 96.48 83.6 114.222 ;
     RECT  83.512 2.418 83.704 22.776 ;
     RECT  83.6 96.378 83.704 114.222 ;
     RECT  83.704 19.344 83.837 19.368 ;
     RECT  83.704 20.352 84.449 22.776 ;
     RECT  83.704 3.072 84.805 9.384 ;
     RECT  84.805 2.832 84.889 9.384 ;
     RECT  84.889 3.072 86.393 9.384 ;
     RECT  84.449 20.88 86.497 22.776 ;
     RECT  81.785 23.76 86.497 94.248 ;
     RECT  83.704 12.24 87.325 18.216 ;
     RECT  86.393 3.072 88.808 8.472 ;
     RECT  83.704 10.608 88.808 10.632 ;
     RECT  87.325 12.24 88.808 19.032 ;
     RECT  86.497 20.88 88.808 94.248 ;
     RECT  83.704 96.48 88.808 96.504 ;
     RECT  83.704 101.328 88.808 101.352 ;
     RECT  83.704 105.36 88.808 107.88 ;
     RECT  83.704 108.912 88.808 108.936 ;
     RECT  88.808 2.148 88.912 94.248 ;
     RECT  88.808 96.48 88.912 114.492 ;
     RECT  88.912 96.48 89 114.222 ;
     RECT  88.912 2.418 89.104 94.248 ;
     RECT  89 96.378 89.104 114.222 ;
     RECT  89.104 12.24 90.493 19.128 ;
     RECT  90.493 11.952 92.245 19.128 ;
     RECT  89.104 20.88 92.369 94.248 ;
     RECT  89.104 10.608 92.617 10.632 ;
     RECT  92.245 11.664 92.617 19.128 ;
     RECT  89.104 108.912 93.265 108.936 ;
     RECT  89.104 96.48 93.301 96.504 ;
     RECT  92.369 21.216 93.397 94.248 ;
     RECT  89.104 3.072 94.208 8.472 ;
     RECT  92.617 10.608 94.208 19.128 ;
     RECT  93.397 20.64 94.208 94.248 ;
     RECT  93.301 96.48 94.208 96.744 ;
     RECT  89.104 101.328 94.208 101.352 ;
     RECT  89.104 105.36 94.208 107.832 ;
     RECT  93.265 108.864 94.208 108.936 ;
     RECT  94.208 2.148 94.312 94.248 ;
     RECT  94.208 96.48 94.312 114.492 ;
     RECT  94.312 2.418 94.385 94.248 ;
     RECT  94.312 96.48 94.4 114.222 ;
     RECT  94.385 2.418 94.504 22.008 ;
     RECT  94.4 96.378 94.504 114.222 ;
     RECT  94.504 10.224 95.401 10.248 ;
     RECT  94.504 11.232 95.509 19.128 ;
     RECT  94.504 20.64 98.345 22.008 ;
     RECT  94.504 3.072 98.593 8.232 ;
     RECT  98.593 3.072 98.701 8.568 ;
     RECT  98.701 3.072 99.097 9.048 ;
     RECT  98.345 20.64 99.109 21.96 ;
     RECT  96.433 10.08 99.349 10.104 ;
     RECT  95.509 11.136 99.349 19.128 ;
     RECT  99.349 10.08 99.565 19.128 ;
     RECT  99.109 20.592 99.565 21.96 ;
     RECT  99.097 3.072 99.608 9.096 ;
     RECT  99.565 10.08 99.608 21.96 ;
     RECT  94.504 96.432 99.608 96.744 ;
     RECT  94.504 101.328 99.608 101.352 ;
     RECT  94.504 105.36 99.608 107.832 ;
     RECT  94.504 108.912 99.608 108.936 ;
     RECT  99.608 2.148 99.712 21.96 ;
     RECT  99.608 96.432 99.712 114.492 ;
     RECT  99.712 96.432 99.8 114.222 ;
     RECT  99.712 2.418 99.904 21.96 ;
     RECT  99.8 96.378 99.904 114.222 ;
     RECT  99.904 108.912 100.325 108.936 ;
     RECT  99.904 3.072 102.197 21.96 ;
     RECT  99.904 101.328 102.593 101.352 ;
     RECT  102.197 3.072 103.813 9.048 ;
     RECT  102.197 10.08 103.813 21.96 ;
     RECT  103.813 3.072 105.008 21.96 ;
     RECT  99.904 96.432 105.008 96.744 ;
     RECT  103.669 101.328 105.008 101.352 ;
     RECT  99.904 105.36 105.008 107.832 ;
     RECT  105.008 2.148 105.112 21.96 ;
     RECT  105.008 96.432 105.112 114.492 ;
     RECT  105.112 96.432 105.2 114.222 ;
     RECT  105.112 2.418 105.304 21.96 ;
     RECT  105.2 96.378 105.304 114.222 ;
     RECT  105.304 105.36 105.941 107.832 ;
     RECT  106.585 0.576 107.125 0.6 ;
     RECT  105.304 3.072 107.237 21.96 ;
     RECT  107.237 3.072 107.341 9.096 ;
     RECT  107.341 2.784 107.377 9.096 ;
     RECT  107.125 0.096 107.665 0.6 ;
     RECT  107.237 10.08 107.665 21.96 ;
     RECT  94.385 23.04 107.665 94.248 ;
     RECT  107.665 0.096 107.701 0.696 ;
     RECT  107.377 2.688 107.737 9.096 ;
     RECT  107.737 2.256 108.385 9.096 ;
     RECT  107.665 10.08 108.385 94.248 ;
     RECT  107.701 0.096 108.515 1.176 ;
     RECT  108.515 0.144 108.611 1.176 ;
     RECT  108.385 2.256 108.673 94.248 ;
     RECT  108.611 0.144 108.707 0.696 ;
     RECT  105.941 105.36 109.037 107.544 ;
     RECT  109.037 107.52 109.073 107.544 ;
     RECT  108.707 0.192 109.091 0.696 ;
     RECT  108.673 1.68 109.283 94.248 ;
     RECT  109.283 1.68 109.379 1.752 ;
     RECT  109.091 0.192 109.709 0.6 ;
     RECT  109.709 0.096 110.225 0.6 ;
     RECT  110.225 0.144 110.293 0.6 ;
     RECT  109.379 1.728 110.408 1.752 ;
     RECT  109.283 3.072 110.408 94.248 ;
     RECT  105.304 96.432 110.408 96.744 ;
     RECT  105.304 101.328 110.408 101.352 ;
     RECT  109.037 105.36 110.408 106.536 ;
     RECT  110.149 107.52 110.408 107.544 ;
     RECT  110.293 0.144 110.435 0.696 ;
     RECT  110.408 96.432 110.512 114.492 ;
     RECT  110.512 96.432 110.6 114.222 ;
     RECT  110.6 96.378 110.704 114.222 ;
     RECT  110.435 0.144 110.867 0.168 ;
     RECT  110.408 1.728 111.637 94.248 ;
     RECT  111.637 1.152 112.133 94.248 ;
     RECT  110.704 96.432 112.205 96.744 ;
     RECT  112.133 1.728 112.925 94.248 ;
     RECT  112.205 96.432 113.069 96.504 ;
     RECT  113.069 96.48 113.281 96.504 ;
     RECT  112.925 2.112 113.969 94.248 ;
     RECT  113.281 96.48 114.145 96.744 ;
     RECT  113.969 2.304 115.808 94.248 ;
     RECT  114.145 96.432 115.808 96.744 ;
     RECT  110.704 101.328 115.808 101.352 ;
     RECT  110.704 105.36 115.808 106.44 ;
     RECT  110.704 107.52 115.808 107.544 ;
     RECT  115.808 2.148 115.912 94.248 ;
     RECT  115.808 96.432 115.912 114.492 ;
     RECT  115.912 96.432 116 114.222 ;
     RECT  115.912 2.418 116.104 94.248 ;
     RECT  116 96.378 116.104 114.222 ;
     RECT  116.104 3.072 117.245 94.248 ;
     RECT  117.245 3.072 118.361 9 ;
     RECT  117.245 10.08 119.873 94.248 ;
     RECT  118.361 3.072 121.208 8.76 ;
     RECT  119.873 10.08 121.208 12.216 ;
     RECT  119.873 13.632 121.208 94.248 ;
     RECT  116.104 96.432 121.208 96.744 ;
     RECT  116.104 101.328 121.208 101.352 ;
     RECT  116.104 105.36 121.208 106.44 ;
     RECT  116.104 107.52 121.208 107.544 ;
     RECT  121.208 2.148 121.312 94.248 ;
     RECT  121.208 96.432 121.312 114.492 ;
     RECT  121.312 96.432 121.4 114.222 ;
     RECT  121.312 2.418 121.504 94.248 ;
     RECT  121.4 96.378 121.504 114.222 ;
     RECT  121.504 13.632 122.861 94.248 ;
     RECT  122.861 13.92 123.937 94.248 ;
     RECT  121.504 3.072 126.608 8.76 ;
     RECT  121.504 10.08 126.608 12.216 ;
     RECT  123.937 13.632 126.608 94.248 ;
     RECT  121.504 96.432 126.608 96.744 ;
     RECT  121.504 101.328 126.608 101.352 ;
     RECT  121.504 105.36 126.608 106.44 ;
     RECT  121.504 107.52 126.608 107.544 ;
     RECT  126.608 2.148 126.712 94.248 ;
     RECT  126.608 96.432 126.712 114.492 ;
     RECT  126.712 96.432 126.8 114.222 ;
     RECT  126.712 2.418 126.904 94.248 ;
     RECT  126.8 96.378 126.904 114.222 ;
     RECT  126.904 3.072 127.865 8.76 ;
     RECT  127.865 5.808 128.297 8.76 ;
     RECT  127.865 3.072 132.008 4.776 ;
     RECT  128.297 6.144 132.008 8.76 ;
     RECT  126.904 10.08 132.008 12.216 ;
     RECT  126.904 13.536 132.008 94.248 ;
     RECT  126.904 96.432 132.008 96.744 ;
     RECT  126.904 101.328 132.008 101.352 ;
     RECT  126.904 105.36 132.008 106.44 ;
     RECT  126.904 107.52 132.008 107.544 ;
     RECT  132.008 2.148 132.112 94.248 ;
     RECT  132.008 96.432 132.112 114.492 ;
     RECT  132.112 96.432 132.2 114.222 ;
     RECT  132.112 2.418 132.304 94.248 ;
     RECT  132.2 96.378 132.304 114.222 ;
     RECT  132.304 3.072 133.373 4.776 ;
     RECT  133.373 3.984 137.408 4.776 ;
     RECT  132.304 6.144 137.408 8.76 ;
     RECT  132.304 10.08 137.408 12.216 ;
     RECT  132.304 13.536 137.408 94.248 ;
     RECT  132.304 96.432 137.408 96.744 ;
     RECT  132.304 101.328 137.408 101.352 ;
     RECT  132.304 105.36 137.408 106.44 ;
     RECT  132.304 107.52 137.408 107.544 ;
     RECT  137.408 2.148 137.512 94.248 ;
     RECT  137.408 96.432 137.512 114.492 ;
     RECT  137.512 96.432 137.6 114.222 ;
     RECT  137.512 2.418 137.704 94.248 ;
     RECT  137.6 96.378 137.704 114.222 ;
     RECT  137.704 3.984 142.513 4.776 ;
     RECT  142.513 3.648 142.808 4.776 ;
     RECT  137.704 6.144 142.808 8.76 ;
     RECT  137.704 10.08 142.808 12.216 ;
     RECT  137.704 13.536 142.808 94.248 ;
     RECT  137.704 96.432 142.808 96.744 ;
     RECT  137.704 101.328 142.808 101.352 ;
     RECT  137.704 105.36 142.808 106.44 ;
     RECT  137.704 107.52 142.808 107.544 ;
     RECT  142.808 2.148 142.912 94.248 ;
     RECT  142.808 96.432 142.912 114.492 ;
     RECT  142.912 96.432 143 114.222 ;
     RECT  142.912 2.418 143.104 94.248 ;
     RECT  143 96.378 143.104 114.222 ;
     RECT  143.104 3.984 148.208 4.776 ;
     RECT  143.104 6.144 148.208 8.76 ;
     RECT  143.104 10.08 148.208 12.216 ;
     RECT  143.104 13.536 148.208 94.248 ;
     RECT  143.104 96.432 148.208 96.744 ;
     RECT  143.104 101.328 148.208 101.352 ;
     RECT  143.104 105.36 148.208 106.44 ;
     RECT  143.104 107.52 148.208 107.544 ;
     RECT  148.208 2.148 148.312 94.248 ;
     RECT  148.208 96.432 148.312 114.492 ;
     RECT  148.312 96.432 148.4 114.222 ;
     RECT  148.312 2.418 148.504 94.248 ;
     RECT  148.4 96.378 148.504 114.222 ;
     RECT  148.504 10.08 151.661 12.216 ;
     RECT  151.661 10.08 152.881 11.736 ;
     RECT  148.504 3.984 153.608 4.776 ;
     RECT  148.504 6.144 153.608 8.76 ;
     RECT  152.881 10.08 153.608 12.312 ;
     RECT  148.504 13.536 153.608 94.248 ;
     RECT  148.504 96.432 153.608 96.744 ;
     RECT  148.504 101.328 153.608 101.352 ;
     RECT  148.504 105.36 153.608 106.44 ;
     RECT  148.504 107.52 153.608 107.544 ;
     RECT  153.608 2.148 153.712 94.248 ;
     RECT  153.608 96.432 153.712 114.492 ;
     RECT  153.712 96.432 153.8 114.222 ;
     RECT  153.712 2.418 153.904 94.248 ;
     RECT  153.8 96.378 153.904 114.222 ;
     RECT  153.904 10.08 154.505 12.312 ;
     RECT  153.904 6.144 156.557 8.76 ;
     RECT  153.904 3.984 159.008 4.92 ;
     RECT  156.557 6.144 159.008 8.472 ;
     RECT  154.505 10.08 159.008 12.216 ;
     RECT  153.904 13.536 159.008 94.248 ;
     RECT  153.904 96.432 159.008 96.744 ;
     RECT  153.904 101.328 159.008 101.352 ;
     RECT  153.904 105.36 159.008 106.44 ;
     RECT  153.904 107.52 159.008 107.544 ;
     RECT  159.008 2.148 159.112 94.248 ;
     RECT  159.008 96.432 159.112 114.492 ;
     RECT  159.112 96.432 159.2 114.222 ;
     RECT  159.112 2.418 159.304 94.248 ;
     RECT  159.2 96.378 159.304 114.222 ;
     RECT  159.304 3.984 162.641 4.92 ;
     RECT  159.304 6.144 162.929 8.472 ;
     RECT  162.641 4.128 164.408 4.92 ;
     RECT  162.929 6.144 164.408 6.168 ;
     RECT  162.929 7.872 164.408 8.472 ;
     RECT  159.304 10.08 164.408 12.216 ;
     RECT  159.304 13.536 164.408 94.248 ;
     RECT  159.304 96.432 164.408 96.744 ;
     RECT  159.304 101.328 164.408 101.352 ;
     RECT  159.304 105.36 164.408 106.44 ;
     RECT  159.304 107.52 164.408 107.544 ;
     RECT  164.408 2.148 164.512 94.248 ;
     RECT  164.408 96.432 164.512 114.492 ;
     RECT  164.512 96.432 164.6 114.222 ;
     RECT  164.512 2.418 164.704 94.248 ;
     RECT  164.6 96.378 164.704 114.222 ;
     RECT  164.704 4.128 167.357 4.92 ;
     RECT  167.357 4.752 167.681 4.92 ;
     RECT  167.681 4.896 169.808 4.92 ;
     RECT  164.704 6.144 169.808 6.168 ;
     RECT  164.704 7.872 169.808 8.472 ;
     RECT  164.704 10.08 169.808 12.216 ;
     RECT  164.704 13.536 169.808 94.248 ;
     RECT  164.704 96.432 169.808 96.744 ;
     RECT  164.704 101.328 169.808 101.352 ;
     RECT  164.704 105.36 169.808 106.44 ;
     RECT  164.704 107.52 169.808 107.544 ;
     RECT  169.808 2.148 169.912 94.248 ;
     RECT  169.808 96.432 169.912 114.492 ;
     RECT  169.912 96.432 170 114.222 ;
     RECT  169.912 2.418 170.104 94.248 ;
     RECT  170 96.378 170.104 114.222 ;
     RECT  170.104 6.144 170.669 6.696 ;
     RECT  170.669 6.144 174.193 6.168 ;
     RECT  170.104 4.896 175.208 4.92 ;
     RECT  174.193 6.144 175.208 6.84 ;
     RECT  170.104 7.872 175.208 8.472 ;
     RECT  170.104 10.08 175.208 12.216 ;
     RECT  170.104 13.536 175.208 94.248 ;
     RECT  170.104 96.432 175.208 96.744 ;
     RECT  170.104 101.328 175.208 101.352 ;
     RECT  170.104 105.36 175.208 106.44 ;
     RECT  170.104 107.52 175.208 107.544 ;
     RECT  175.208 2.148 175.312 94.248 ;
     RECT  175.208 96.432 175.312 114.492 ;
     RECT  175.312 96.432 175.4 114.222 ;
     RECT  175.312 2.418 175.504 94.248 ;
     RECT  175.4 96.378 175.504 114.222 ;
     RECT  175.504 4.896 180.608 4.92 ;
     RECT  175.504 6.144 180.608 6.168 ;
     RECT  175.504 7.872 180.608 8.472 ;
     RECT  175.504 10.08 180.608 12.216 ;
     RECT  175.504 13.536 180.608 94.248 ;
     RECT  175.504 96.432 180.608 96.744 ;
     RECT  175.504 101.328 180.608 101.352 ;
     RECT  175.504 105.36 180.608 106.44 ;
     RECT  175.504 107.52 180.608 107.544 ;
     RECT  180.608 2.148 180.712 94.248 ;
     RECT  180.608 96.432 180.712 114.492 ;
     RECT  180.712 96.432 180.8 114.222 ;
     RECT  180.712 2.418 180.904 94.248 ;
     RECT  180.8 96.378 180.904 114.222 ;
     RECT  180.904 4.896 186.008 4.92 ;
     RECT  180.904 6.144 186.008 6.168 ;
     RECT  180.904 7.872 186.008 8.472 ;
     RECT  180.904 10.08 186.008 12.216 ;
     RECT  180.904 13.536 186.008 94.248 ;
     RECT  180.904 96.432 186.008 96.744 ;
     RECT  180.904 101.328 186.008 101.352 ;
     RECT  180.904 105.36 186.008 106.44 ;
     RECT  180.904 107.52 186.008 107.544 ;
     RECT  186.008 2.148 186.112 94.248 ;
     RECT  186.008 96.432 186.112 114.492 ;
     RECT  186.112 96.432 186.2 114.222 ;
     RECT  186.112 2.418 186.304 94.248 ;
     RECT  186.2 96.378 186.304 114.222 ;
     RECT  186.304 4.896 191.408 4.92 ;
     RECT  186.304 6.144 191.408 6.168 ;
     RECT  186.304 7.872 191.408 8.472 ;
     RECT  186.304 10.08 191.408 12.216 ;
     RECT  186.304 13.536 191.408 94.248 ;
     RECT  186.304 96.432 191.408 96.744 ;
     RECT  186.304 101.328 191.408 101.352 ;
     RECT  186.304 105.36 191.408 106.44 ;
     RECT  186.304 107.52 191.408 107.544 ;
     RECT  191.408 2.148 191.512 94.248 ;
     RECT  191.408 96.432 191.512 114.492 ;
     RECT  191.512 96.432 191.6 114.222 ;
     RECT  191.512 2.418 191.704 94.248 ;
     RECT  191.6 96.378 191.704 114.222 ;
     RECT  191.704 4.896 194.353 4.92 ;
     RECT  194.353 4.896 194.393 5.016 ;
     RECT  191.704 96.432 194.393 96.744 ;
     RECT  191.704 105.36 194.501 106.44 ;
     RECT  194.501 105.36 194.573 106.344 ;
     RECT  191.704 6.144 194.929 6.168 ;
     RECT  194.393 4.992 196.808 5.016 ;
     RECT  194.929 6.144 196.808 6.648 ;
     RECT  191.704 7.872 196.808 8.472 ;
     RECT  191.704 10.08 196.808 12.216 ;
     RECT  191.704 13.536 196.808 94.248 ;
     RECT  194.393 96.528 196.808 96.744 ;
     RECT  191.704 101.328 196.808 101.352 ;
     RECT  194.573 105.36 196.808 106.296 ;
     RECT  191.704 107.52 196.808 107.544 ;
     RECT  196.808 2.148 196.912 94.248 ;
     RECT  196.808 96.528 196.912 114.492 ;
     RECT  196.912 96.528 197 114.222 ;
     RECT  196.912 2.418 197.104 94.248 ;
     RECT  197 96.378 197.104 114.222 ;
     RECT  197.104 13.536 197.568 94.248 ;
     RECT  197.568 13.536 197.741 64.2 ;
     RECT  197.741 13.536 197.777 64.104 ;
     RECT  197.104 105.36 197.795 106.296 ;
     RECT  197.777 13.536 197.849 63.96 ;
     RECT  197.849 24.528 197.891 63.96 ;
     RECT  197.849 13.536 197.939 23.4 ;
     RECT  197.104 96.528 198.035 96.744 ;
     RECT  197.104 107.52 198.131 107.544 ;
     RECT  197.104 101.328 198.179 101.352 ;
     RECT  197.891 24.528 198.245 63.912 ;
     RECT  198.035 96.528 198.275 96.552 ;
     RECT  197.795 105.696 198.323 106.296 ;
     RECT  197.104 10.08 198.349 12.216 ;
     RECT  198.323 106.272 198.371 106.296 ;
     RECT  197.939 13.536 198.467 23.352 ;
     RECT  198.245 24.528 198.641 24.84 ;
     RECT  198.245 25.872 199.235 63.912 ;
     RECT  199.235 28.08 199.505 63.912 ;
     RECT  199.235 25.872 199.619 26.76 ;
     RECT  199.505 28.272 199.649 63.912 ;
     RECT  198.641 24.624 199.781 24.84 ;
     RECT  199.649 28.464 199.829 63.912 ;
     RECT  199.781 24.528 199.865 24.84 ;
     RECT  197.568 65.664 199.865 67.8 ;
     RECT  197.568 69.456 199.865 70.296 ;
     RECT  197.104 4.992 199.907 5.016 ;
     RECT  198.467 13.536 199.909 23.304 ;
     RECT  199.909 13.536 200.009 23.352 ;
     RECT  199.829 28.464 200.009 34.92 ;
     RECT  197.104 6.144 200.051 6.648 ;
     RECT  200.009 33.936 200.081 34.92 ;
     RECT  199.829 36.24 200.081 63.912 ;
     RECT  200.081 36.24 200.117 55.704 ;
     RECT  200.081 56.784 200.117 63.912 ;
     RECT  200.009 28.464 200.153 32.808 ;
     RECT  200.153 28.464 200.189 32.136 ;
     RECT  200.189 28.464 200.225 30.408 ;
     RECT  200.117 36.432 200.225 55.704 ;
     RECT  200.009 13.536 200.243 23.256 ;
     RECT  200.081 34.128 200.261 34.92 ;
     RECT  200.225 36.432 200.261 44.232 ;
     RECT  200.261 42.096 200.297 44.232 ;
     RECT  200.225 45.36 200.297 48.552 ;
     RECT  200.117 57.84 200.297 63.912 ;
     RECT  200.261 38.544 200.333 40.872 ;
     RECT  200.297 45.744 200.333 48.552 ;
     RECT  200.225 49.584 200.333 55.704 ;
     RECT  200.297 57.84 200.333 62.76 ;
     RECT  200.189 32.112 200.369 32.136 ;
     RECT  200.261 36.432 200.369 37.032 ;
     RECT  200.333 39.12 200.369 39.24 ;
     RECT  200.333 40.272 200.369 40.872 ;
     RECT  200.333 49.584 200.369 51.528 ;
     RECT  200.243 13.536 200.387 23.208 ;
     RECT  200.225 28.464 200.405 29.352 ;
     RECT  200.333 52.56 200.405 53.928 ;
     RECT  200.225 30.384 200.441 30.408 ;
     RECT  200.369 37.008 200.441 37.032 ;
     RECT  200.369 39.12 200.441 39.144 ;
     RECT  200.369 40.272 200.441 40.776 ;
     RECT  200.297 43.056 200.441 43.08 ;
     RECT  200.333 45.744 200.441 46.056 ;
     RECT  200.333 57.84 200.441 61.992 ;
     RECT  200.297 63.792 200.441 63.912 ;
     RECT  199.865 24.624 200.477 24.84 ;
     RECT  200.441 40.752 200.477 40.776 ;
     RECT  200.477 24.672 200.485 24.84 ;
     RECT  199.619 25.872 200.485 25.896 ;
     RECT  200.485 24.672 200.549 25.896 ;
     RECT  200.405 29.328 200.585 29.352 ;
     RECT  200.441 46.032 200.657 46.056 ;
     RECT  200.441 61.632 200.657 61.992 ;
     RECT  200.657 61.632 200.729 61.704 ;
     RECT  200.261 34.128 200.801 34.152 ;
     RECT  200.405 53.904 200.837 53.928 ;
     RECT  200.387 16.272 200.867 23.208 ;
     RECT  200.117 56.784 200.873 56.808 ;
     RECT  198.349 10.08 200.915 12.312 ;
     RECT  200.915 11.664 201.011 12.312 ;
     RECT  200.867 18.672 201.053 23.208 ;
     RECT  200.867 16.272 201.059 17.352 ;
     RECT  200.387 13.536 201.107 15.192 ;
     RECT  201.053 18.672 201.155 21.288 ;
     RECT  201.059 16.272 201.203 16.296 ;
     RECT  200.441 63.792 201.445 63.816 ;
     RECT  200.369 49.584 201.589 51.432 ;
     RECT  200.405 52.56 201.589 52.584 ;
     RECT  201.589 49.584 201.925 52.584 ;
     RECT  201.925 49.584 201.973 52.776 ;
     RECT  200.333 54.912 202.021 55.704 ;
     RECT  200.051 6.144 202.208 6.168 ;
     RECT  197.104 7.872 202.208 8.472 ;
     RECT  200.915 10.08 202.208 10.344 ;
     RECT  201.011 12.288 202.208 12.312 ;
     RECT  201.107 13.536 202.208 14.76 ;
     RECT  201.059 17.328 202.208 17.352 ;
     RECT  201.155 18.672 202.208 18.696 ;
     RECT  201.155 19.776 202.208 21.288 ;
     RECT  201.053 22.56 202.208 23.208 ;
     RECT  200.549 24.672 202.208 25.464 ;
     RECT  201.397 28.752 202.208 28.776 ;
     RECT  201.349 29.808 202.208 29.832 ;
     RECT  201.781 45.264 202.208 45.288 ;
     RECT  200.333 47.952 202.208 48.552 ;
     RECT  201.973 49.584 202.208 53.112 ;
     RECT  202.021 54.864 202.208 55.704 ;
     RECT  200.441 57.84 202.208 60.312 ;
     RECT  200.729 61.632 202.208 61.656 ;
     RECT  201.445 63.792 202.208 64.344 ;
     RECT  199.865 66.528 202.208 67.032 ;
     RECT  202.208 2.148 202.312 114.492 ;
     RECT  202.312 2.418 202.504 114.222 ;
     RECT  202.504 29.808 202.601 29.928 ;
     RECT  202.504 12.288 202.643 12.312 ;
     RECT  202.504 57.552 204.257 60.312 ;
     RECT  202.504 28.752 204.545 28.776 ;
     RECT  202.504 10.08 204.653 10.104 ;
     RECT  202.504 54.864 204.653 55.704 ;
     RECT  202.504 45.264 205.148 45.288 ;
     RECT  205.148 45.264 205.189 46.248 ;
     RECT  205.189 45.264 205.235 46.872 ;
     RECT  202.504 6.144 205.661 6.168 ;
     RECT  204.257 57.552 206.053 58.008 ;
     RECT  204.257 59.184 206.053 60.312 ;
     RECT  204.653 54.864 206.089 55.512 ;
     RECT  202.504 20.832 206.341 20.856 ;
     RECT  202.601 29.904 206.341 29.928 ;
     RECT  202.504 48.096 206.341 48.552 ;
     RECT  202.504 49.584 206.341 53.112 ;
     RECT  206.341 20.832 206.381 20.952 ;
     RECT  202.504 24.768 206.381 25.464 ;
     RECT  206.341 29.904 206.381 30.072 ;
     RECT  205.235 46.848 206.485 46.872 ;
     RECT  206.341 48.096 206.485 53.112 ;
     RECT  202.504 63.792 206.489 64.344 ;
     RECT  202.504 66.528 206.521 67.032 ;
     RECT  206.485 46.848 206.561 53.112 ;
     RECT  204.613 11.424 206.627 11.448 ;
     RECT  205.297 56.496 206.732 56.52 ;
     RECT  206.053 57.552 206.732 60.312 ;
     RECT  206.593 62.736 206.845 62.76 ;
     RECT  206.489 63.792 206.845 64.056 ;
     RECT  206.521 66.528 206.953 67.176 ;
     RECT  202.504 61.632 207.277 61.656 ;
     RECT  206.845 62.736 207.277 64.056 ;
     RECT  202.504 7.872 207.608 7.896 ;
     RECT  206.381 20.928 207.608 20.952 ;
     RECT  202.504 22.56 207.608 22.584 ;
     RECT  206.381 24.912 207.608 25.464 ;
     RECT  206.381 30.048 207.608 30.072 ;
     RECT  206.561 47.712 207.608 53.112 ;
     RECT  206.089 54.72 207.608 55.512 ;
     RECT  206.732 56.496 207.608 60.312 ;
     RECT  207.277 61.632 207.608 64.056 ;
     RECT  206.953 65.568 207.608 67.176 ;
     RECT  207.608 2.148 207.712 114.492 ;
     RECT  207.712 2.418 207.904 114.222 ;
     RECT  207.904 61.632 207.929 64.056 ;
     RECT  207.904 56.928 208.019 60.648 ;
     RECT  207.904 66.048 208.019 67.176 ;
     RECT  207.904 51.648 208.037 53.208 ;
     RECT  207.904 30.048 208.073 30.072 ;
     RECT  207.904 47.856 208.145 49.896 ;
     RECT  207.904 22.56 208.757 22.584 ;
     RECT  208.019 56.928 208.757 57.912 ;
     RECT  207.904 54.72 208.829 55.512 ;
     RECT  207.904 20.928 208.883 20.952 ;
     RECT  208.037 52.032 209.045 53.208 ;
     RECT  208.019 59.04 209.084 60.648 ;
     RECT  207.929 61.632 209.084 61.656 ;
     RECT  207.904 24.912 209.117 24.936 ;
     RECT  208.757 56.976 209.125 57.912 ;
     RECT  209.084 59.04 209.125 61.656 ;
     RECT  208.019 66.528 209.125 67.032 ;
     RECT  207.929 62.736 209.171 64.056 ;
     RECT  208.145 48.672 209.225 49.896 ;
     RECT  209.171 63.792 209.261 64.056 ;
     RECT  209.045 52.128 209.329 53.208 ;
     RECT  209.225 49.056 209.413 49.896 ;
     RECT  209.413 49.056 209.459 50.136 ;
     RECT  209.125 56.976 209.869 61.656 ;
     RECT  209.329 52.128 209.909 53.304 ;
     RECT  209.909 52.128 210.193 53.208 ;
     RECT  210.193 51.648 210.301 53.208 ;
     RECT  209.125 65.568 210.337 67.032 ;
     RECT  209.869 56.976 210.445 62.568 ;
     RECT  209.459 49.728 210.449 50.136 ;
     RECT  210.301 51.504 210.665 53.208 ;
     RECT  210.337 65.568 210.665 67.128 ;
     RECT  210.445 56.976 210.701 62.664 ;
     RECT  210.701 56.976 210.769 57.576 ;
     RECT  210.449 49.728 210.877 49.752 ;
     RECT  210.701 58.656 210.881 62.664 ;
     RECT  208.829 54.768 210.913 55.512 ;
     RECT  210.665 51.504 210.985 53.112 ;
     RECT  210.881 61.008 211.057 62.664 ;
     RECT  209.261 64.032 211.057 64.056 ;
     RECT  211.057 61.008 211.187 64.056 ;
     RECT  211.187 64.032 211.417 64.056 ;
     RECT  211.187 61.008 211.565 62.76 ;
     RECT  210.769 65.52 211.565 65.544 ;
     RECT  210.877 49.632 211.637 49.752 ;
     RECT  210.881 58.656 211.961 59.88 ;
     RECT  210.913 54.768 211.993 55.56 ;
     RECT  210.769 56.736 212.065 57.576 ;
     RECT  212.065 56.544 212.425 57.576 ;
     RECT  211.565 62.496 212.497 62.76 ;
     RECT  211.417 64.032 212.497 64.104 ;
     RECT  210.985 51.072 212.569 53.112 ;
     RECT  211.993 54.48 212.569 55.56 ;
     RECT  207.904 7.872 213.008 7.896 ;
     RECT  211.637 49.728 213.008 49.752 ;
     RECT  212.569 51.072 213.008 55.56 ;
     RECT  212.425 56.544 213.008 58.152 ;
     RECT  211.961 59.184 213.008 59.88 ;
     RECT  211.565 61.008 213.008 61.176 ;
     RECT  212.497 62.496 213.008 64.104 ;
     RECT  210.665 66.528 213.008 67.128 ;
     RECT  213.008 2.148 213.112 114.492 ;
     RECT  213.112 2.418 213.304 114.222 ;
     RECT  213.304 54.72 213.509 63.288 ;
     RECT  213.304 51.072 214.369 52.776 ;
     RECT  213.509 54.72 214.369 63.192 ;
     RECT  213.304 65.808 214.369 66.264 ;
     RECT  214.369 50.88 214.585 52.776 ;
     RECT  214.369 53.76 214.585 63.192 ;
     RECT  214.585 50.88 214.657 63.864 ;
     RECT  214.369 65.808 214.657 66.552 ;
     RECT  214.657 50.88 214.765 64.056 ;
     RECT  214.657 65.232 214.765 66.552 ;
     RECT  214.765 50.88 214.837 66.552 ;
     RECT  214.837 50.688 215.737 66.552 ;
     RECT  215.737 50.544 215.953 66.552 ;
     RECT  215.953 50.544 216.605 66.888 ;
     RECT  216.605 66.528 216.713 66.696 ;
     RECT  216.605 50.544 216.821 65.544 ;
     RECT  216.821 50.544 217.285 64.488 ;
     RECT  217.285 49.776 217.717 64.488 ;
     RECT  216.821 65.52 217.717 65.544 ;
     RECT  216.713 66.672 217.717 66.696 ;
     RECT  217.717 65.52 217.789 66.696 ;
     RECT  217.717 49.392 217.825 64.488 ;
     RECT  217.789 65.52 217.825 67.176 ;
     RECT  217.825 49.392 218.221 67.176 ;
     RECT  218.221 49.392 220.284 67.272 ;
    LAYER M5 ;
     RECT  108.384 0.016 111.864 1.763 ;
     RECT  2.4 2.137 2.52 2.151 ;
     RECT  7.8 2.137 7.92 2.151 ;
     RECT  13.2 2.137 13.32 2.151 ;
     RECT  18.6 2.137 18.72 2.151 ;
     RECT  24 2.137 24.12 2.151 ;
     RECT  29.4 2.137 29.52 2.151 ;
     RECT  34.8 2.137 34.92 2.151 ;
     RECT  40.2 2.137 40.32 2.151 ;
     RECT  45.6 2.137 45.72 2.151 ;
     RECT  51 2.137 51.12 2.151 ;
     RECT  56.4 2.137 56.52 2.151 ;
     RECT  61.8 2.137 61.92 2.151 ;
     RECT  67.2 2.137 67.32 2.151 ;
     RECT  72.6 2.137 72.72 2.151 ;
     RECT  78 2.137 78.12 2.151 ;
     RECT  83.4 2.137 83.52 2.151 ;
     RECT  88.8 2.137 88.92 2.151 ;
     RECT  94.2 2.137 94.32 2.151 ;
     RECT  99.6 2.137 99.72 2.151 ;
     RECT  105 2.137 105.12 2.151 ;
     RECT  115.8 2.137 115.92 2.151 ;
     RECT  121.2 2.137 121.32 2.151 ;
     RECT  126.6 2.137 126.72 2.151 ;
     RECT  132 2.137 132.12 2.151 ;
     RECT  137.4 2.137 137.52 2.151 ;
     RECT  142.8 2.137 142.92 2.151 ;
     RECT  148.2 2.137 148.32 2.151 ;
     RECT  153.6 2.137 153.72 2.151 ;
     RECT  159 2.137 159.12 2.151 ;
     RECT  164.4 2.137 164.52 2.151 ;
     RECT  169.8 2.137 169.92 2.151 ;
     RECT  175.2 2.137 175.32 2.151 ;
     RECT  180.6 2.137 180.72 2.151 ;
     RECT  186 2.137 186.12 2.151 ;
     RECT  191.4 2.137 191.52 2.151 ;
     RECT  196.8 2.137 196.92 2.151 ;
     RECT  202.2 2.137 202.32 2.151 ;
     RECT  207.6 2.137 207.72 2.151 ;
     RECT  213 2.137 213.12 2.151 ;
     RECT  108.384 1.763 109.272 2.291 ;
     RECT  110.304 1.763 111.864 3.205 ;
     RECT  110.304 3.205 112.344 3.347 ;
     RECT  18.6 2.151 18.912 3.349 ;
     RECT  110.4 3.347 112.344 3.395 ;
     RECT  99.6 2.151 99.912 4.405 ;
     RECT  16.992 4.405 17.016 4.501 ;
     RECT  18.144 3.349 18.912 4.501 ;
     RECT  99.6 4.405 100.776 4.501 ;
     RECT  99.216 4.501 100.776 4.547 ;
     RECT  110.4 3.395 111.528 4.547 ;
     RECT  110.4 4.547 110.856 4.549 ;
     RECT  108.384 2.291 108.408 4.645 ;
     RECT  117.312 4.645 117.336 4.787 ;
     RECT  108.384 4.645 108.84 4.883 ;
     RECT  20.736 4.213 20.76 5.125 ;
     RECT  99.216 4.547 99.912 5.219 ;
     RECT  110.112 4.549 110.856 5.267 ;
     RECT  16.992 4.501 18.912 5.269 ;
     RECT  20.496 5.125 20.76 5.269 ;
     RECT  105 2.151 105.312 5.605 ;
     RECT  110.112 5.267 110.808 5.699 ;
     RECT  24 2.151 24.312 5.797 ;
     RECT  16.992 5.269 20.76 6.085 ;
     RECT  101.472 6.181 101.496 6.229 ;
     RECT  16.608 6.085 20.76 6.277 ;
     RECT  115.8 2.151 116.112 6.277 ;
     RECT  103.056 3.925 103.08 6.325 ;
     RECT  108.384 4.883 108.408 6.565 ;
     RECT  108.24 6.565 108.408 6.613 ;
     RECT  199.872 4.981 199.896 6.613 ;
     RECT  113.136 6.181 113.976 6.757 ;
     RECT  112.896 6.757 113.976 6.803 ;
     RECT  108.048 6.613 108.408 6.805 ;
     RECT  105 5.605 106.008 6.853 ;
     RECT  112.896 6.803 113.448 6.899 ;
     RECT  110.112 5.699 110.712 6.949 ;
     RECT  104.88 6.853 106.008 6.995 ;
     RECT  105 6.995 106.008 7.043 ;
     RECT  101.328 6.229 101.496 7.045 ;
     RECT  16.464 6.277 20.76 7.141 ;
     RECT  118.464 6.901 118.488 7.187 ;
     RECT  110.112 6.949 111.336 7.189 ;
     RECT  94.2 2.151 94.512 7.333 ;
     RECT  95.52 6.805 95.544 7.333 ;
     RECT  103.056 6.325 103.752 7.427 ;
     RECT  110.112 7.189 111.72 7.475 ;
     RECT  108.048 6.805 109.032 7.621 ;
     RECT  112.896 6.899 112.92 7.909 ;
     RECT  115.056 6.277 116.112 8.341 ;
     RECT  117.216 7.189 117.24 8.341 ;
     RECT  110.4 7.475 111.72 8.435 ;
     RECT  115.056 8.341 117.24 8.435 ;
     RECT  94.2 7.333 95.544 8.437 ;
     RECT  202.2 2.151 202.512 8.437 ;
     RECT  107.712 7.621 109.032 8.819 ;
     RECT  108.384 8.819 109.032 8.821 ;
     RECT  110.4 8.435 111.096 8.821 ;
     RECT  105 7.043 105.312 8.917 ;
     RECT  112.8 7.909 112.92 9.011 ;
     RECT  108.384 8.821 111.096 9.059 ;
     RECT  99.6 5.219 99.912 9.061 ;
     RECT  15.36 8.437 15.384 9.155 ;
     RECT  108.384 9.059 110.712 9.155 ;
     RECT  115.056 8.435 116.28 9.155 ;
     RECT  112.896 9.011 112.92 9.731 ;
     RECT  105 8.917 106.008 9.827 ;
     RECT  115.056 9.155 116.232 9.827 ;
     RECT  109.68 9.155 110.712 9.923 ;
     RECT  99.12 9.061 100.296 10.019 ;
     RECT  201.456 8.437 202.512 10.309 ;
     RECT  199.872 6.613 200.04 10.597 ;
     RECT  199.824 10.597 200.04 11.125 ;
     RECT  94.08 8.437 95.544 11.171 ;
     RECT  199.728 11.125 200.04 11.173 ;
     RECT  201.408 10.309 202.512 11.173 ;
     RECT  92.256 6.805 92.28 11.699 ;
     RECT  16.464 7.141 20.808 12.229 ;
     RECT  199.728 11.173 202.512 12.277 ;
     RECT  94.08 11.171 95.496 12.517 ;
     RECT  16.464 12.229 20.856 12.757 ;
     RECT  24 5.797 24.408 13.139 ;
     RECT  16.464 12.757 21 13.141 ;
     RECT  16.368 13.141 21 13.285 ;
     RECT  21.984 5.221 22.008 13.285 ;
     RECT  101.328 7.045 101.88 13.331 ;
     RECT  103.056 7.427 103.08 13.331 ;
     RECT  16.368 13.285 22.008 13.381 ;
     RECT  13.2 2.151 13.512 13.621 ;
     RECT  84.816 2.821 84.84 14.387 ;
     RECT  99.12 10.019 100.152 14.435 ;
     RECT  93.408 12.517 95.496 14.483 ;
     RECT  110.4 9.923 110.712 14.677 ;
     RECT  105 9.827 105.312 14.917 ;
     RECT  98.064 6.229 98.088 15.059 ;
     RECT  105 14.917 105.816 15.059 ;
     RECT  101.328 13.331 101.352 15.635 ;
     RECT  16.368 13.381 22.584 15.733 ;
     RECT  13.2 13.621 13.608 16.261 ;
     RECT  16.368 15.733 22.728 16.501 ;
     RECT  57.84 16.645 57.864 16.883 ;
     RECT  199.728 12.277 202.632 17.653 ;
     RECT  115.056 9.827 116.112 17.747 ;
     RECT  196.8 2.151 197.112 17.893 ;
     RECT  149.76 17.605 149.784 17.941 ;
     RECT  196.8 17.893 197.736 18.133 ;
     RECT  149.76 17.941 149.88 18.179 ;
     RECT  93.408 14.483 95.352 18.707 ;
     RECT  7.8 2.151 8.112 18.709 ;
     RECT  196.704 18.133 197.736 18.805 ;
     RECT  199.056 17.653 202.632 18.805 ;
     RECT  9.408 18.757 9.432 19.237 ;
     RECT  7.248 18.709 8.112 19.285 ;
     RECT  45.6 2.151 45.912 19.525 ;
     RECT  47.088 3.301 47.112 19.525 ;
     RECT  15.216 19.573 15.24 19.813 ;
     RECT  16.32 16.501 22.728 19.813 ;
     RECT  7.008 19.285 8.112 19.861 ;
     RECT  9.408 19.237 10.056 19.909 ;
     RECT  196.704 18.805 202.632 20.099 ;
     RECT  15.216 19.813 22.728 20.101 ;
     RECT  9.408 19.909 10.584 20.437 ;
     RECT  45.6 19.525 47.112 20.579 ;
     RECT  99.12 14.435 99.912 20.627 ;
     RECT  6.864 19.861 8.112 20.629 ;
     RECT  9.36 20.437 10.584 20.629 ;
     RECT  93.408 18.707 94.512 20.675 ;
     RECT  5.616 19.333 5.64 20.677 ;
     RECT  148.2 2.151 148.512 20.821 ;
     RECT  149.76 18.179 149.784 20.821 ;
     RECT  148.2 20.821 149.784 20.867 ;
     RECT  15.072 20.101 22.728 20.869 ;
     RECT  5.184 20.677 5.64 20.917 ;
     RECT  6.864 20.629 10.584 20.917 ;
     RECT  207.6 2.151 207.912 20.917 ;
     RECT  108.384 9.155 108.408 21.155 ;
     RECT  110.4 14.677 111.432 21.155 ;
     RECT  148.2 20.867 149.592 21.155 ;
     RECT  76.368 19.909 76.392 21.251 ;
     RECT  149.568 21.155 149.592 21.443 ;
     RECT  3.984 20.821 4.008 21.445 ;
     RECT  5.184 20.917 10.584 21.445 ;
     RECT  45.6 20.579 45.912 21.541 ;
     RECT  11.712 21.493 11.736 22.261 ;
     RECT  12.768 16.261 13.608 22.261 ;
     RECT  11.712 22.261 13.608 22.309 ;
     RECT  45.6 21.541 46.728 23.363 ;
     RECT  3.984 21.445 10.584 23.365 ;
     RECT  11.664 22.309 13.608 23.365 ;
     RECT  15.072 20.869 22.776 24.517 ;
     RECT  15.072 24.517 22.824 24.707 ;
     RECT  3.984 23.365 13.608 27.923 ;
     RECT  15.072 24.707 22.68 28.549 ;
     RECT  15.072 28.549 22.728 28.597 ;
     RECT  15.072 28.597 22.824 28.787 ;
     RECT  15.072 28.787 22.68 29.603 ;
     RECT  15.072 29.603 22.536 31.333 ;
     RECT  15.072 31.333 22.824 31.523 ;
     RECT  196.8 20.099 202.632 32.339 ;
     RECT  199.248 32.339 202.632 32.531 ;
     RECT  199.488 32.531 202.632 32.915 ;
     RECT  196.8 32.339 197.784 33.299 ;
     RECT  15.072 31.523 22.536 35.845 ;
     RECT  14.64 35.845 22.536 35.941 ;
     RECT  14.64 35.941 22.824 36.131 ;
     RECT  14.64 36.131 22.488 37.091 ;
     RECT  15.072 37.091 22.488 40.453 ;
     RECT  15.072 40.453 22.824 40.643 ;
     RECT  2.4 2.151 2.712 42.133 ;
     RECT  3.984 27.923 13.512 42.133 ;
     RECT  15.072 40.643 22.488 42.227 ;
     RECT  0.192 43.093 0.216 43.285 ;
     RECT  0.144 43.285 0.216 43.669 ;
     RECT  0.144 43.669 0.504 44.387 ;
     RECT  17.28 42.227 22.488 45.061 ;
     RECT  17.28 45.061 22.824 45.347 ;
     RECT  2.4 42.133 13.512 45.445 ;
     RECT  17.28 45.347 22.728 45.587 ;
     RECT  15.072 42.227 16.2 45.637 ;
     RECT  17.28 45.587 22.488 45.637 ;
     RECT  15.072 45.637 22.488 45.683 ;
     RECT  0.192 44.387 0.504 46.115 ;
     RECT  205.2 45.253 205.224 46.259 ;
     RECT  0.24 46.115 0.504 47.365 ;
     RECT  206.592 11.413 206.616 47.701 ;
     RECT  0.24 47.365 0.552 47.845 ;
     RECT  15.072 45.683 17.304 48.373 ;
     RECT  196.8 33.299 197.736 48.373 ;
     RECT  15.072 48.373 17.352 48.419 ;
     RECT  196.8 48.373 197.88 48.563 ;
     RECT  206.496 47.701 206.616 48.997 ;
     RECT  207.6 20.917 208.872 48.997 ;
     RECT  206.496 48.997 208.872 49.045 ;
     RECT  17.28 48.419 17.352 49.091 ;
     RECT  206.496 49.045 209.448 49.091 ;
     RECT  206.592 49.091 209.448 49.235 ;
     RECT  2.304 45.445 13.512 49.573 ;
     RECT  199.68 32.915 202.632 49.859 ;
     RECT  207.6 49.235 209.448 50.147 ;
     RECT  0.144 47.845 0.552 50.867 ;
     RECT  2.304 49.573 13.608 50.965 ;
     RECT  199.728 49.859 202.632 51.011 ;
     RECT  18.6 45.683 22.488 51.877 ;
     RECT  0.432 50.867 0.552 51.971 ;
     RECT  206.592 49.235 206.616 52.069 ;
     RECT  207.6 50.147 208.872 52.069 ;
     RECT  17.28 49.091 17.304 52.499 ;
     RECT  214.32 52.645 214.344 52.787 ;
     RECT  0.528 51.971 0.552 53.029 ;
     RECT  0.144 53.029 0.552 53.315 ;
     RECT  0.288 53.315 0.552 54.517 ;
     RECT  206.592 52.069 208.872 54.803 ;
     RECT  0.144 54.517 0.552 54.899 ;
     RECT  207.6 54.803 208.872 55.333 ;
     RECT  207.6 55.333 209.16 55.379 ;
     RECT  18.432 51.877 22.488 55.717 ;
     RECT  2.304 50.965 13.656 56.341 ;
     RECT  15.072 48.419 16.2 56.341 ;
     RECT  0.192 54.899 0.552 56.531 ;
     RECT  218.256 56.437 218.28 56.627 ;
     RECT  0.288 56.531 0.552 56.675 ;
     RECT  206.592 54.803 206.616 57.301 ;
     RECT  207.6 55.379 207.912 57.301 ;
     RECT  206.592 57.301 207.912 57.443 ;
     RECT  2.304 56.341 16.2 57.491 ;
     RECT  199.776 51.011 202.632 57.587 ;
     RECT  0.288 56.675 0.408 57.589 ;
     RECT  2.304 57.491 13.656 57.635 ;
     RECT  2.4 57.635 13.656 57.683 ;
     RECT  218.256 57.925 218.28 58.163 ;
     RECT  2.4 57.683 13.608 58.211 ;
     RECT  207.6 57.443 207.912 58.693 ;
     RECT  206.592 57.443 206.616 58.741 ;
     RECT  206.496 58.741 206.616 59.315 ;
     RECT  207.6 58.693 208.008 59.315 ;
     RECT  214.32 59.701 214.344 59.843 ;
     RECT  206.592 59.315 206.616 59.987 ;
     RECT  0.144 57.589 0.408 60.035 ;
     RECT  17.568 55.717 22.488 60.035 ;
     RECT  199.776 57.587 202.512 60.323 ;
     RECT  2.4 58.211 13.512 61.331 ;
     RECT  214.32 61.333 214.344 61.523 ;
     RECT  2.4 61.331 3.192 61.619 ;
     RECT  199.776 60.323 199.8 61.667 ;
     RECT  196.8 48.563 197.112 61.813 ;
     RECT  0.384 60.035 0.408 61.859 ;
     RECT  2.4 61.619 2.712 62.677 ;
     RECT  4.272 61.331 13.512 62.677 ;
     RECT  0.144 62.677 0.168 62.867 ;
     RECT  2.4 62.677 13.512 63.061 ;
     RECT  2.304 63.061 13.512 63.203 ;
     RECT  2.4 63.203 13.512 63.299 ;
     RECT  211.152 62.629 211.176 63.299 ;
     RECT  196.8 61.813 197.736 63.781 ;
     RECT  15.072 57.491 16.2 63.827 ;
     RECT  200.928 60.323 202.512 63.827 ;
     RECT  196.8 63.781 197.88 63.971 ;
     RECT  217.104 64.021 217.128 64.259 ;
     RECT  18.48 60.035 22.488 64.355 ;
     RECT  201.456 63.827 202.512 64.355 ;
     RECT  18.48 64.355 20.328 64.451 ;
     RECT  20.304 64.451 20.328 64.643 ;
     RECT  21.36 64.355 22.488 64.883 ;
     RECT  2.4 63.299 10.008 65.027 ;
     RECT  2.4 65.027 2.712 65.509 ;
     RECT  209.136 55.379 209.16 65.603 ;
     RECT  196.8 63.971 197.784 65.653 ;
     RECT  207.6 59.315 207.912 66.037 ;
     RECT  2.304 65.509 2.712 66.085 ;
     RECT  3.696 65.027 10.008 66.085 ;
     RECT  10.992 63.299 13.512 66.179 ;
     RECT  0.144 65.221 0.168 66.421 ;
     RECT  196.8 65.653 198.072 66.517 ;
     RECT  2.304 66.085 10.008 66.755 ;
     RECT  10.992 66.179 11.976 66.755 ;
     RECT  207.6 66.037 208.008 67.187 ;
     RECT  21.36 64.883 21.96 67.715 ;
     RECT  6.672 66.755 9.816 67.763 ;
     RECT  196.8 66.517 198.264 67.765 ;
     RECT  9.792 67.763 9.816 67.859 ;
     RECT  0.144 66.421 0.264 67.909 ;
     RECT  0.144 67.909 0.36 68.147 ;
     RECT  21.888 67.715 21.96 68.243 ;
     RECT  15.072 63.827 15.672 68.675 ;
     RECT  6.672 67.763 8.808 68.917 ;
     RECT  11.088 66.755 11.976 68.917 ;
     RECT  21.888 68.243 21.912 69.059 ;
     RECT  2.304 66.755 5.688 69.349 ;
     RECT  6.672 68.917 9.24 69.349 ;
     RECT  2.304 69.349 9.24 69.493 ;
     RECT  15.648 68.675 15.672 69.827 ;
     RECT  0.144 68.147 0.168 70.021 ;
     RECT  13.2 66.179 13.512 70.117 ;
     RECT  14.784 70.069 14.808 70.117 ;
     RECT  0.144 70.021 0.264 70.211 ;
     RECT  2.304 69.493 9.672 70.261 ;
     RECT  11.088 68.917 12.216 70.261 ;
     RECT  196.8 67.765 198.312 70.261 ;
     RECT  2.304 70.261 12.216 70.355 ;
     RECT  13.2 70.117 14.808 70.787 ;
     RECT  2.304 70.355 10.296 71.075 ;
     RECT  11.952 70.355 12.216 71.363 ;
     RECT  14.784 70.787 14.808 72.131 ;
     RECT  0.144 70.211 0.168 72.469 ;
     RECT  0.144 72.469 0.312 72.659 ;
     RECT  2.304 71.075 9.672 72.995 ;
     RECT  12.192 71.363 12.216 73.283 ;
     RECT  6.768 72.995 9.672 74.053 ;
     RECT  6.624 74.053 9.672 74.723 ;
     RECT  2.304 72.995 5.64 75.299 ;
     RECT  2.304 75.299 2.712 75.443 ;
     RECT  3.936 75.299 5.64 90.659 ;
     RECT  9.648 74.723 9.672 95.219 ;
     RECT  18.48 64.451 18.912 95.219 ;
     RECT  4.464 90.659 5.64 96.467 ;
     RECT  21.072 95.701 21.096 96.515 ;
     RECT  94.2 20.675 94.512 96.517 ;
     RECT  93.648 96.517 94.512 96.709 ;
     RECT  6.624 74.723 8.112 100.835 ;
     RECT  78 2.151 78.312 101.317 ;
     RECT  196.8 70.261 198.36 106.211 ;
     RECT  5.328 96.467 5.64 106.259 ;
     RECT  198.096 106.211 198.36 106.307 ;
     RECT  5.328 106.259 5.496 107.027 ;
     RECT  78 101.317 79.272 107.219 ;
     RECT  10.368 95.701 10.392 107.315 ;
     RECT  198.096 106.307 198.12 107.555 ;
     RECT  6.912 100.835 8.112 107.843 ;
     RECT  5.328 107.027 5.4 107.891 ;
     RECT  5.376 107.891 5.4 108.323 ;
     RECT  93.312 96.709 94.512 108.899 ;
     RECT  2.4 75.443 2.712 114.489 ;
     RECT  7.8 107.843 8.112 114.489 ;
     RECT  13.2 70.787 13.512 114.489 ;
     RECT  18.6 95.219 18.912 114.489 ;
     RECT  24 13.139 24.312 114.489 ;
     RECT  29.4 2.151 29.712 114.489 ;
     RECT  34.8 2.151 35.112 114.489 ;
     RECT  40.2 2.151 40.512 114.489 ;
     RECT  45.6 23.363 45.912 114.489 ;
     RECT  51 2.151 51.312 114.489 ;
     RECT  56.4 2.151 56.712 114.489 ;
     RECT  61.8 2.151 62.112 114.489 ;
     RECT  67.2 2.151 67.512 114.489 ;
     RECT  72.6 2.151 72.912 114.489 ;
     RECT  78 107.219 78.312 114.489 ;
     RECT  83.4 2.151 83.712 114.489 ;
     RECT  88.8 2.151 89.112 114.489 ;
     RECT  94.2 108.899 94.512 114.489 ;
     RECT  99.6 20.627 99.912 114.489 ;
     RECT  105 15.059 105.312 114.489 ;
     RECT  110.4 21.155 110.712 114.489 ;
     RECT  115.8 17.747 116.112 114.489 ;
     RECT  121.2 2.151 121.512 114.489 ;
     RECT  126.6 2.151 126.912 114.489 ;
     RECT  132 2.151 132.312 114.489 ;
     RECT  137.4 2.151 137.712 114.489 ;
     RECT  142.8 2.151 143.112 114.489 ;
     RECT  148.2 21.155 148.512 114.489 ;
     RECT  153.6 2.151 153.912 114.489 ;
     RECT  159 2.151 159.312 114.489 ;
     RECT  164.4 2.151 164.712 114.489 ;
     RECT  169.8 2.151 170.112 114.489 ;
     RECT  175.2 2.151 175.512 114.489 ;
     RECT  180.6 2.151 180.912 114.489 ;
     RECT  186 2.151 186.312 114.489 ;
     RECT  191.4 2.151 191.712 114.489 ;
     RECT  196.8 106.211 197.112 114.489 ;
     RECT  202.2 64.355 202.512 114.489 ;
     RECT  207.6 67.187 207.912 114.489 ;
     RECT  213 2.151 213.312 114.489 ;
     RECT  2.4 114.489 2.52 114.503 ;
     RECT  7.8 114.489 7.92 114.503 ;
     RECT  13.2 114.489 13.32 114.503 ;
     RECT  18.6 114.489 18.72 114.503 ;
     RECT  24 114.489 24.12 114.503 ;
     RECT  29.4 114.489 29.52 114.503 ;
     RECT  34.8 114.489 34.92 114.503 ;
     RECT  40.2 114.489 40.32 114.503 ;
     RECT  45.6 114.489 45.72 114.503 ;
     RECT  51 114.489 51.12 114.503 ;
     RECT  56.4 114.489 56.52 114.503 ;
     RECT  61.8 114.489 61.92 114.503 ;
     RECT  67.2 114.489 67.32 114.503 ;
     RECT  72.6 114.489 72.72 114.503 ;
     RECT  78 114.489 78.12 114.503 ;
     RECT  83.4 114.489 83.52 114.503 ;
     RECT  88.8 114.489 88.92 114.503 ;
     RECT  94.2 114.489 94.32 114.503 ;
     RECT  99.6 114.489 99.72 114.503 ;
     RECT  105 114.489 105.12 114.503 ;
     RECT  110.4 114.489 110.52 114.503 ;
     RECT  115.8 114.489 115.92 114.503 ;
     RECT  121.2 114.489 121.32 114.503 ;
     RECT  126.6 114.489 126.72 114.503 ;
     RECT  132 114.489 132.12 114.503 ;
     RECT  137.4 114.489 137.52 114.503 ;
     RECT  142.8 114.489 142.92 114.503 ;
     RECT  148.2 114.489 148.32 114.503 ;
     RECT  153.6 114.489 153.72 114.503 ;
     RECT  159 114.489 159.12 114.503 ;
     RECT  164.4 114.489 164.52 114.503 ;
     RECT  169.8 114.489 169.92 114.503 ;
     RECT  175.2 114.489 175.32 114.503 ;
     RECT  180.6 114.489 180.72 114.503 ;
     RECT  186 114.489 186.12 114.503 ;
     RECT  191.4 114.489 191.52 114.503 ;
     RECT  196.8 114.489 196.92 114.503 ;
     RECT  202.2 114.489 202.32 114.503 ;
     RECT  207.6 114.489 207.72 114.503 ;
     RECT  213 114.489 213.12 114.503 ;
  END
END hfd_hgi_vm_calendar
END LIBRARY
